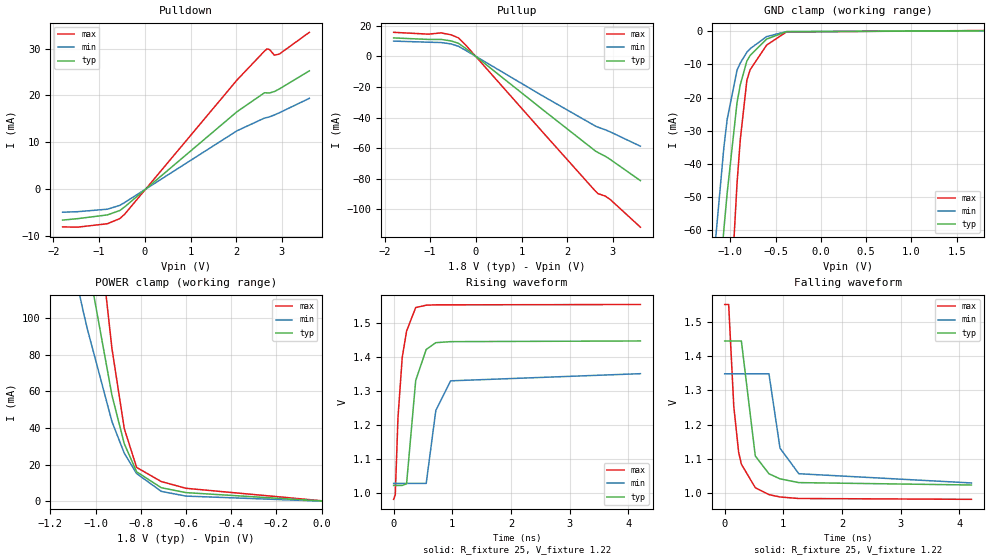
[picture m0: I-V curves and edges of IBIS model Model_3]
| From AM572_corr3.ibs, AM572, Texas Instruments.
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| Model based on original model for BMLBLVDS18_SSCEH
|   Sub model LVDS_TXMODE_5P_1P8
[model]   Model_3
|[Description]  [1.8V-3-STATE-X-8MA, IND, 5%]
|   8MA, ,IND,5%
|[Input Load]
|[Output Drive] 8MA
|Voltage   1.8V
|Mode   3-STATE
Model_type   3-state
Polarity   Non-Inverting
Enable   Active-Low
Cref =   15.0000pF
Rref =   100.0000M
Vref =   0V
Vmeas =   0.9
C_comp   3.4p   3.05p   3.82p
[Temperature Range]   25   125   -40
[Voltage Range]   1.8   1.71   1.89
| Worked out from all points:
|   slope of the pulldown table from 0 to 0.27 V, typ, clamps not added: 120 ohm
|   slope of the pullup table from 0 to 0.27 V, typ, clamps not added: 42.3 ohm
|   GND clamp passes 1 mA (typ) near -0.51 V on its own axis
|   POWER clamp passes 1 mA (typ) near -0.40 V on its own axis
|   rising waveform, R_fixture 25, V_fixture 1.22: 20-80 % time 169ps typ, 202ps min, 132ps max; typ from 1.02 V to 1.45 V
|   falling waveform, R_fixture 25, V_fixture 1.22: 20-80 % time 201ps typ, 234ps min, 166ps max; typ from 1.45 V to 1.02 V
[POWER_clamp]
-1.8V     779.9mA    580mA      1.224A
-1.236V   292.1mA    211mA      460.4mA
-1.145V   217.2mA    155.6mA    341.7mA
-1.127V   202.7mA    145mA      318.5mA
-1.055V   145.7mA    103.9mA    227.2mA
-1.036V   131.7mA    93.92mA    204.8mA
-927.3mV  57.78mA    43.44mA    83.3mA
-872.7mV  31.31mA    26.16mA    39.59mA
-818.2mV  16.05mA    15.09mA    18.44mA
-709.1mV  7.358mA    5.377mA    10.73mA
-600mV    4.702mA    2.805mA    7.054mA
0V        145uA      60.2uA     263.6uA
[Pulldown]
-1.8V     -6.635mA   -4.952mA   -8.093mA
-1.473V   -6.328mA   -4.839mA   -8.146mA
-818.2mV  -5.526mA   -4.308mA   -7.413mA
-545.5mV  -4.576mA   -3.477mA   -6.298mA
-436.4mV  -3.768mA   -2.842mA   -5.315mA
2.018V    16.54mA    12.46mA    23.32mA
2.618V    20.58mA    15.17mA    29.48mA
2.673V    20.56mA    15.28mA    29.95mA
2.727V    20.53mA    15.43mA    29.83mA
2.836V    20.85mA    15.84mA    28.61mA
2.945V    21.4mA     16.31mA    28.86mA
3.6V      25.27mA    19.39mA    33.5mA
[Pullup]
-1.8V     12.04mA    9.955mA    15.69mA
-1.036V   11.05mA    9.232mA    14.5mA
-763.6mV  11.06mA    9.014mA    15.32mA
-545.5mV  10.1mA     8.132mA    14.08mA
-381.8mV  8.512mA    6.562mA    12.05mA
-218.2mV  5.085mA    3.82mA     7.21mA
1.473V    -35.08mA   -26.06mA   -49.88mA
2.618V    -61.9mA    -45.6mA    -88.15mA
2.673V    -62.85mA   -46.29mA   -89.7mA
2.836V    -65.33mA   -48.03mA   -91.35mA
2.945V    -67.45mA   -49.42mA   -93.67mA
3.6V      -81.19mA   -58.71mA   -111.6mA
[GND_clamp]
-1.8V     -321.4mA   -309.3mA   -563.6mA
-1.291V   -133.4mA   -105mA     -247.8mA
-1.218V   -107.9mA   -79mA      -204.2mA
-1.073V   -59.81mA   -35.07mA   -120mA
-1.036V   -48.68mA   -26.51mA   -99.87mA
-927.3mV  -21.51mA   -11.72mA   -45.84mA
-890.9mV  -16.08mA   -9.549mA   -32.59mA
-818.2mV  -8.944mA   -6.334mA   -14.72mA
-781.8mV  -7.267mA   -5.252mA   -11.57mA
-600mV    -2.366mA   -1.611mA   -4.175mA
-381.8mV  -124.6uA   -115.9uA   -225uA
1.8V      145uA      89.85uA    222.6uA
[Ramp]
dV/dt_f 0.25647137/0.20081716n 0.19549562/0.23091708n 0.34546341/0.16608129n
dV/dt_r 0.25611571/0.16843214n 0.19698732/0.20168935n 0.34404226/0.13153623n
R_load =  50
[Rising Waveform]
R_fixture =  25
V_fixture =  1.22
V_fixture_min =  1.18
V_fixture_max =  1.28
0s        1.022V     1.028V     981.3mV
27.4ps    1.022V     1.028V     994.4mV
73.5ps    1.022V     1.028V     1.22V
146.2ps   1.022V     1.028V     1.398V
220.5ps   1.027V     1.028V     1.475V
375.8ps   1.33V      1.028V     1.544V
555.2ps   1.421V     1.028V     1.551V
719ps     1.441V     1.242V     1.552V
971.2ps   1.444V     1.329V     1.552V
4.207ns   1.446V     1.35V      1.553V
[Falling Waveform]
R_fixture =  25
V_fixture =  1.22
V_fixture_min =  1.18
V_fixture_max =  1.28
0s        1.445V     1.349V     1.552V
67.8ps    1.445V     1.349V     1.552V
154.8ps   1.445V     1.349V     1.254V
237.1ps   1.445V     1.349V     1.12V
284.4ps   1.445V     1.349V     1.084V
521.7ps   1.108V     1.349V     1.015V
754.5ps   1.056V     1.349V     994.8mV
943.2ps   1.041V     1.131V     987.9mV
1.264ns   1.03V      1.056V     983.4mV
4.207ns   1.023V     1.029V     981mV
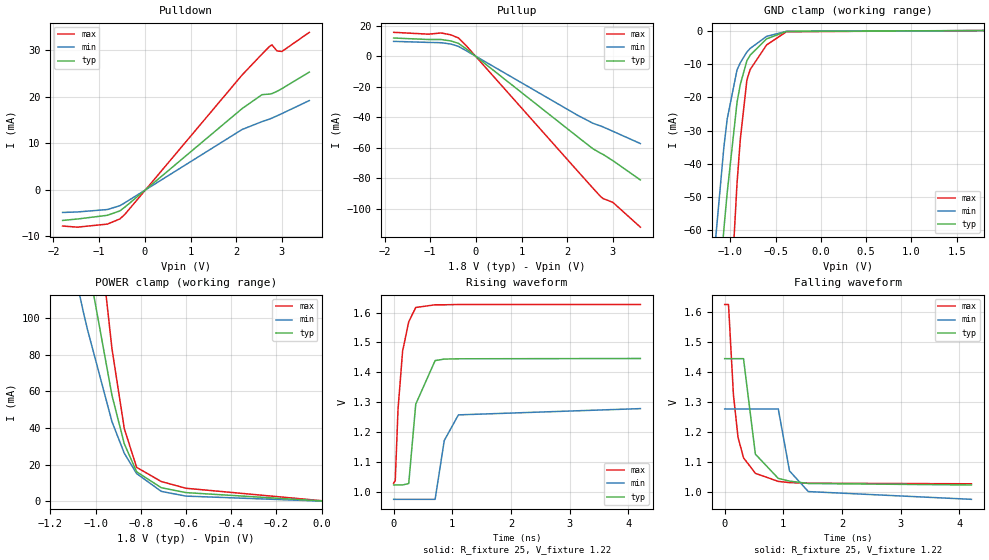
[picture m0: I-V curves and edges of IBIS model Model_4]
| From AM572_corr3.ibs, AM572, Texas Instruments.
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| Model based on original model for BMLBLVDS18_SSCEH
|   Sub model LVDS_TXMODE_10P_1P8
[model]   Model_4
|[Description]  [1.8V-3-STATE-X-8MA, IND, 10%]
|   8MA, ,IND,10%
|[Input Load]
|[Output Drive] 8MA
|Voltage   1.8V
|Mode   3-STATE
Model_type   3-state
Polarity   Non-Inverting
Enable   Active-Low
Cref =   15.0000pF
Rref =   100.0000M
Vref =   0V
Vmeas =   0.9
C_comp   3.4p   3.05p   3.82p
[Temperature Range]   25   125   -40
[Voltage Range]   1.8   1.62   1.98
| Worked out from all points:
|   slope of the pulldown table from 0 to 0.27 V, typ, clamps not added: 120 ohm
|   slope of the pullup table from 0 to 0.27 V, typ, clamps not added: 42.3 ohm
|   GND clamp passes 1 mA (typ) near -0.51 V on its own axis
|   POWER clamp passes 1 mA (typ) near -0.40 V on its own axis
|   rising waveform, R_fixture 25, V_fixture 1.22: 20-80 % time 169ps typ, 199ps min, 133ps max; typ from 1.02 V to 1.45 V
|   falling waveform, R_fixture 25, V_fixture 1.22: 20-80 % time 201ps typ, 230ps min, 167ps max; typ from 1.45 V to 1.02 V
[POWER_clamp]
-1.8V     779.9mA    580mA      1.224A
-1.236V   292.1mA    211mA      460.4mA
-1.145V   217.2mA    155.6mA    341.7mA
-1.127V   202.7mA    145mA      318.5mA
-1.055V   145.7mA    103.9mA    227.2mA
-1.036V   131.7mA    93.91mA    204.8mA
-927.3mV  57.78mA    43.43mA    83.32mA
-872.7mV  31.31mA    26.15mA    39.61mA
-818.2mV  16.05mA    15.08mA    18.46mA
-709.1mV  7.358mA    5.366mA    10.74mA
-600mV    4.702mA    2.795mA    7.071mA
0V        145uA      51.95uA    279uA
[Pulldown]
-1.8V     -6.635mA   -4.922mA   -7.841mA
-1.473V   -6.328mA   -4.812mA   -8.081mA
-818.2mV  -5.526mA   -4.29mA    -7.418mA
-545.5mV  -4.576mA   -3.464mA   -6.304mA
-436.4mV  -3.768mA   -2.831mA   -5.321mA
2.127V    17.4mA     12.91mA    24.62mA
2.564V    20.41mA    14.61mA    29.13mA
2.727V    20.53mA    15.15mA    30.76mA
2.782V    20.64mA    15.37mA    31.11mA
2.891V    21.11mA    15.85mA    29.82mA
3V        21.7mA     16.34mA    29.69mA
3.6V      25.27mA    19.14mA    33.81mA
[Pullup]
-1.8V     12.04mA    9.825mA    15.77mA
-1.036V   11.05mA    9.145mA    14.56mA
-763.6mV  11.06mA    8.945mA    15.36mA
-545.5mV  10.1mA     8.081mA    14.11mA
-381.8mV  8.512mA    6.527mA    12.07mA
-218.2mV  5.085mA    3.802mA    7.215mA
2.236V    -53.09mA   -38.87mA   -75.68mA
2.564V    -60.75mA   -44mA      -86.66mA
2.727V    -63.6mA    -45.71mA   -92.01mA
2.782V    -64.4mA    -46.35mA   -93.39mA
3V        -68.56mA   -49.24mA   -95.96mA
3.6V      -81.19mA   -57.3mA    -112.2mA
[GND_clamp]
-1.8V     -321.4mA   -309.3mA   -563.9mA
-1.291V   -133.4mA   -105mA     -247.9mA
-1.218V   -107.9mA   -79mA      -204.2mA
-1.073V   -59.81mA   -35.07mA   -120mA
-1.036V   -48.68mA   -26.51mA   -99.89mA
-927.3mV  -21.51mA   -11.71mA   -45.86mA
-890.9mV  -16.08mA   -9.545mA   -32.61mA
-818.2mV  -8.944mA   -6.331mA   -14.73mA
-781.8mV  -7.267mA   -5.249mA   -11.59mA
-600mV    -2.366mA   -1.608mA   -4.187mA
-381.8mV  -124.6uA   -112.9uA   -234.8uA
1.8V      145uA      118uA      146.8uA
[Ramp]
dV/dt_f 0.25647119/0.20081769n 0.18465813/0.2297182n 0.36196187/0.16662824n
dV/dt_r  0.2561077/0.16843651n  0.1864017/0.19810172n 0.36039242/0.13273573n
R_load =  50
[Rising Waveform]
R_fixture =  25
V_fixture =  1.22
V_fixture_min =  1.13
V_fixture_max =  1.32
0s        1.022V     973.9mV    1.028V
27.4ps    1.022V     973.9mV    1.037V
74.3ps    1.022V     973.9mV    1.275V
152.8ps   1.022V     973.9mV    1.471V
257ps     1.027V     973.9mV    1.569V
376.8ps   1.293V     973.9mV    1.617V
707ps     1.439V     973.9mV    1.626V
862.9ps   1.444V     1.171V     1.626V
1.104ns   1.445V     1.257V     1.627V
4.207ns   1.446V     1.278V     1.627V
[Falling Waveform]
R_fixture =  25
V_fixture =  1.22
V_fixture_min =  1.13
V_fixture_max =  1.32
0s        1.445V     1.277V     1.626V
64.9ps    1.445V     1.277V     1.626V
149.1ps   1.445V     1.277V     1.324V
227.5ps   1.445V     1.277V     1.182V
321ps     1.445V     1.277V     1.114V
522.9ps   1.126V     1.277V     1.062V
913.9ps   1.045V     1.277V     1.035V
1.105ns   1.036V     1.07V      1.031V
1.426ns   1.028V     1.001V     1.029V
4.207ns   1.023V     975.1mV    1.027V
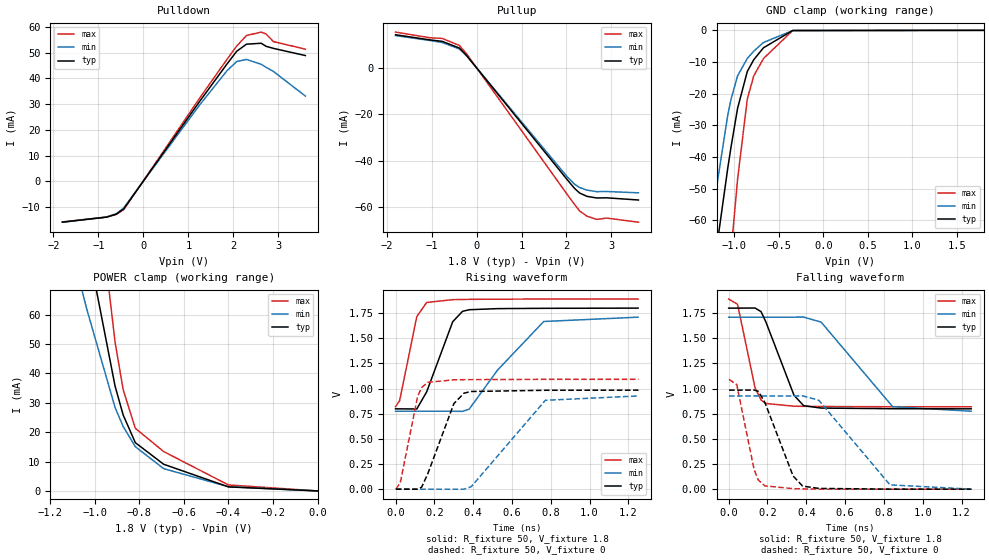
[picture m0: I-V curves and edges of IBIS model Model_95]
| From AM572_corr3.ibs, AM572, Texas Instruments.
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| Model based on original model for DDR_SEIOPB_H
|   Sub model SR011_DRV40_1P8
[model]   Model_95
|[Description]  [1.8V-I/O-X-X]
|   , ,
|[Input Load]
|[Output Drive]
|Voltage   1.8V
|Mode   I/O
Model_type   I/O
Polarity   Non-Inverting
Enable   Active-Low
Vinl =   0.775
Vinh =   1.025
Cref =   15.0000pF
Rref =   100.0000M
Vref =   0V
Vmeas =   0.9
C_comp   2p   2p   2p
[Model Spec]
Vinl   0.78   0.735   0.825
Vinh   1.02   0.975   1.065
[Receiver Thresholds]
Tslew_ac =  0.5n
Vth =  0.9
Vth_max =  0.945
Vth_min =  0.81
Vinh_ac =  0.2
Vinh_dc =  0.125
Vinl_ac =  -0.2
Vinl_dc =  -0.125
[Temperature Range]   25   125   -40
[Voltage Range]   1.8   1.71   1.89
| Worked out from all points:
|   slope of the pulldown table from 0 to 0.27 V, typ, clamps not added: 39.7 ohm
|   slope of the pullup table from 0 to 0.27 V, typ, clamps not added: 41.4 ohm
|   GND clamp passes 1 mA (typ) near -0.48 V on its own axis
|   POWER clamp passes 1 mA (typ) near -0.38 V on its own axis
|   rising waveform, R_fixture 50, V_fixture 1.8: 20-80 % time 115ps typ, 272ps min, 66.2ps max; typ from 0.799 V to 1.8 V
|   rising waveform, R_fixture 50, V_fixture 0: 20-80 % time 112ps typ, 256ps min, 65.7ps max; typ from 0 V to 0.984 V
|   falling waveform, R_fixture 50, V_fixture 1.8: 20-80 % time 119ps typ, 249ps min, 65.8ps max; typ from 1.8 V to 0.799 V
|   falling waveform, R_fixture 50, V_fixture 0: 20-80 % time 116ps typ, 246ps min, 65.9ps max; typ from 0.984 V to 0 V
[POWER_clamp]
-1.8V     464.6mA    344.4mA    740.8mA
-1.273V   197mA      143.3mA    314.4mA
-1.164V   144mA      104.2mA    229mA
-1.145V   135.3mA    97.86mA    215mA
-1.055V   93.25mA    67.59mA    146.5mA
-1.036V   85.18mA    61.89mA    133.3mA
-909.1mV  35.72mA    28.41mA    50.73mA
-872.7mV  25.87mA    21.94mA    34.5mA
-818.2mV  16.45mA    15.08mA    21.33mA
-690.9mV  9.084mA    7.592mA    13.42mA
-400mV    1.38mA     1.43mA     2.039mA
0V        227.3nA    761nA      1.176uA
[Pulldown]
-1.8V     -15.9mA    -15.92mA   -15.81mA
-818.2mV  -13.96mA   -13.89mA   -13.92mA
-600mV    -12.8mA    -12.58mA   -12.84mA
-436.4mV  -10.71mA   -10.33mA   -11.03mA
1.255V    31.16mA    29.78mA    32.45mA
1.855V    45.52mA    42.91mA    47.32mA
2.073V    50.52mA    46.55mA    52.56mA
2.291V    53.3mA     47.36mA    56.66mA
2.618V    53.66mA    45.48mA    58mA
2.727V    52.47mA    44.31mA    57.26mA
2.891V    51.66mA    42.7mA     54.29mA
3.6V      48.88mA    33.12mA    51.37mA
[Pullup]
-1.8V     14.28mA    13.9mA     15.42mA
-1.036V   12.05mA    11.79mA    12.97mA
-763.6mV  11.43mA    10.95mA    12.69mA
-381.8mV  8.556mA    8.124mA    9.674mA
-218.2mV  5.258mA    5.122mA    5.967mA
2.018V    -48.25mA   -46.99mA   -54.63mA
2.182V    -52.02mA   -50.21mA   -58.98mA
2.291V    -53.95mA   -51.57mA   -61.66mA
2.455V    -55.39mA   -52.71mA   -63.95mA
2.673V    -56.09mA   -53.37mA   -65.34mA
2.891V    -56.02mA   -53.3mA    -64.76mA
3.6V      -56.97mA   -53.87mA   -66.53mA
[GND_clamp]
-1.8V     -200.8mA   -187.9mA   -345.9mA
-1.327V   -95.75mA   -76.22mA   -171.1mA
-1.255V   -80.19mA   -60.47mA   -144.9mA
-1.218V   -72.53mA   -52.92mA   -131.9mA
-1.073V   -43.32mA   -26.59mA   -81.54mA
-1.036V   -36.61mA   -21.6mA    -69.55mA
-963.6mV  -24.61mA   -14.37mA   -47.01mA
-854.5mV  -12.98mA   -8.864mA   -21.66mA
-781.8mV  -9.263mA   -6.573mA   -14.36mA
-672.7mV  -5.498mA   -3.827mA   -8.897mA
-345.5mV  -48.81uA   -73.08uA   -79.37uA
1.8V      227.3nA    3.986uA    988nA
[Ramp]
dV/dt_f 0.60157145/0.11917839n 0.56193529/0.24940345n 0.64276181/65.810123p
dV/dt_r 0.59164809/0.11183383n 0.55731319/0.25748775n 0.65630864/65.814305p
R_load =  50
[Rising Waveform]
R_fixture =  50
V_fixture =  1.8
V_fixture_min =  1.71
V_fixture_max =  1.89
0s        798.6mV    774.9mV    820.2mV
21.02ps   798.4mV    774.9mV    879.8mV
109.5ps   797.2mV    774.8mV    1.716V
160.3ps   967.1mV    774.9mV    1.856V
294.7ps   1.665V     774.8mV    1.884V
345.2ps   1.768V     773.1mV    1.886V
379.8ps   1.784V     796.4mV    1.887V
526.2ps   1.795V     1.185V     1.889V
763.6ps   1.798V     1.667V     1.89V
1.25ns    1.8V       1.71V      1.89V
[Rising Waveform]
R_fixture =  50
V_fixture =  0
V_fixture_min =  0
V_fixture_max =  0
1.657ps   0V         0V         0V
24.5ps    0V         0V         64.86mV
113.5ps   0V         0V         919.3mV
134.2ps   18.59mV    0V         1.01V
166ps     152.6mV    0V         1.062V
300.6ps   850.8mV    0V         1.087V
353.1ps   954.7mV    0V         1.089V
389.9ps   971mV      24.27mV    1.089V
772.2ps   983.1mV    883.7mV    1.092V
1.252ns   984.5mV    926.8mV    1.092V
[Falling Waveform]
R_fixture =  50
V_fixture =  1.8
V_fixture_min =  1.71
V_fixture_max =  1.89
0s        1.8V       1.71V      1.89V
45.84ps   1.8V       1.71V      1.838V
135.9ps   1.801V     1.71V      1.008V
166.9ps   1.765V     1.71V      885.6mV
191.7ps   1.663V     1.71V      852mV
336.7ps   933.7mV    1.71V      824.7mV
386.2ps   830.3mV    1.711V     823.2mV
476.4ps   806.1mV    1.661V     821.5mV
845.1ps   799.9mV    820.1mV    819.5mV
1.25ns    798.6mV    774.9mV    819.3mV
[Falling Waveform]
R_fixture =  50
V_fixture =  0
V_fixture_min =  0
V_fixture_max =  0
1.657ps   984.5mV    926.8mV    1.092V
41.72ps   984.7mV    926.8mV    1.039V
131.3ps   985.5mV    926.9mV    192.5mV
153.1ps   972.6mV    926.9mV    89.75mV
186.6ps   862mV      926.8mV    33.17mV
331.9ps   131.2mV    926.6mV    4.76mV
381.1ps   30.54mV    927.3mV    3.153mV
464.5ps   7.614mV    883.9mV    0V
831.3ps   0V         42.71mV    0V
1.252ns   0V         0V         0V
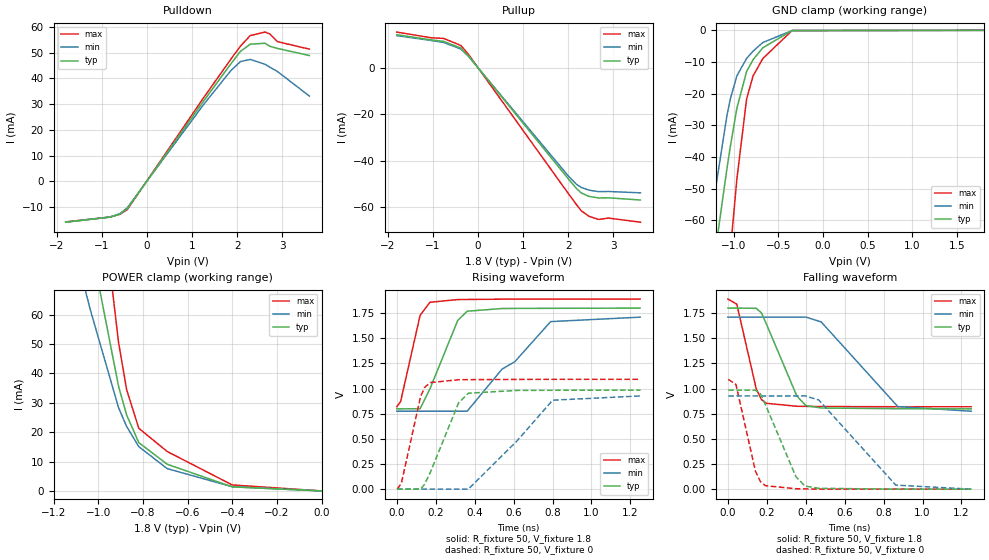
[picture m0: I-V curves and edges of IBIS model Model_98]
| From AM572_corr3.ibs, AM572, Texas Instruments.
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| Model based on original model for DDR_SEIOPB_H
|   Sub model SR100_DRV40_1P8
[model]   Model_98
|[Description]  [1.8V-I/O-X-X]
|   , ,
|[Input Load]
|[Output Drive]
|Voltage   1.8V
|Mode   I/O
Model_type   I/O
Polarity   Non-Inverting
Enable   Active-Low
Vinl =   0.775
Vinh =   1.025
Cref =   15.0000pF
Rref =   100.0000M
Vref =   0V
Vmeas =   0.9
C_comp   2p   2p   2p
[Model Spec]
Vinl   0.78   0.735   0.825
Vinh   1.02   0.975   1.065
[Receiver Thresholds]
Tslew_ac =  0.5n
Vth =  0.9
Vth_max =  0.945
Vth_min =  0.81
Vinh_ac =  0.2
Vinh_dc =  0.125
Vinl_ac =  -0.2
Vinl_dc =  -0.125
[Temperature Range]   25   125   -40
[Voltage Range]   1.8   1.71   1.89
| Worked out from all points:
|   slope of the pulldown table from 0 to 0.27 V, typ, clamps not added: 39.7 ohm
|   slope of the pullup table from 0 to 0.27 V, typ, clamps not added: 41.4 ohm
|   GND clamp passes 1 mA (typ) near -0.48 V on its own axis
|   POWER clamp passes 1 mA (typ) near -0.38 V on its own axis
|   rising waveform, R_fixture 50, V_fixture 1.8: 20-80 % time 128ps typ, 297ps min, 73.7ps max; typ from 0.799 V to 1.8 V
|   rising waveform, R_fixture 50, V_fixture 0: 20-80 % time 123ps typ, 281ps min, 73.1ps max; typ from 0 V to 0.984 V
|   falling waveform, R_fixture 50, V_fixture 1.8: 20-80 % time 132ps typ, 272ps min, 72.6ps max; typ from 1.8 V to 0.799 V
|   falling waveform, R_fixture 50, V_fixture 0: 20-80 % time 129ps typ, 269ps min, 73ps max; typ from 0.984 V to 0 V
[POWER_clamp]
-1.8V     464.6mA    344.4mA    740.8mA
-1.273V   197mA      143.3mA    314.4mA
-1.164V   144mA      104.2mA    229mA
-1.145V   135.3mA    97.86mA    215mA
-1.055V   93.25mA    67.59mA    146.5mA
-1.036V   85.18mA    61.89mA    133.3mA
-909.1mV  35.72mA    28.41mA    50.73mA
-872.7mV  25.87mA    21.94mA    34.5mA
-818.2mV  16.45mA    15.08mA    21.33mA
-690.9mV  9.084mA    7.592mA    13.42mA
-400mV    1.38mA     1.43mA     2.039mA
0V        227.3nA    761nA      1.176uA
[Pulldown]
-1.8V     -15.9mA    -15.92mA   -15.81mA
-818.2mV  -13.96mA   -13.89mA   -13.92mA
-600mV    -12.8mA    -12.58mA   -12.84mA
-436.4mV  -10.71mA   -10.33mA   -11.03mA
1.255V    31.16mA    29.78mA    32.45mA
1.855V    45.52mA    42.91mA    47.32mA
2.073V    50.52mA    46.55mA    52.56mA
2.291V    53.3mA     47.36mA    56.66mA
2.618V    53.66mA    45.48mA    58mA
2.727V    52.47mA    44.31mA    57.26mA
2.891V    51.66mA    42.7mA     54.29mA
3.6V      48.88mA    33.12mA    51.37mA
[Pullup]
-1.8V     14.28mA    13.9mA     15.42mA
-1.036V   12.05mA    11.79mA    12.97mA
-763.6mV  11.43mA    10.95mA    12.69mA
-381.8mV  8.556mA    8.124mA    9.674mA
-218.2mV  5.258mA    5.122mA    5.967mA
2.018V    -48.25mA   -46.99mA   -54.63mA
2.182V    -52.02mA   -50.21mA   -58.98mA
2.291V    -53.95mA   -51.57mA   -61.66mA
2.455V    -55.39mA   -52.71mA   -63.95mA
2.673V    -56.09mA   -53.37mA   -65.34mA
2.891V    -56.02mA   -53.3mA    -64.76mA
3.6V      -56.97mA   -53.87mA   -66.53mA
[GND_clamp]
-1.8V     -200.8mA   -187.9mA   -345.9mA
-1.327V   -95.75mA   -76.22mA   -171.1mA
-1.255V   -80.19mA   -60.47mA   -144.9mA
-1.218V   -72.53mA   -52.92mA   -131.9mA
-1.073V   -43.32mA   -26.59mA   -81.54mA
-1.036V   -36.61mA   -21.6mA    -69.55mA
-963.6mV  -24.61mA   -14.37mA   -47.01mA
-854.5mV  -12.98mA   -8.864mA   -21.66mA
-781.8mV  -9.263mA   -6.573mA   -14.36mA
-672.7mV  -5.498mA   -3.827mA   -8.897mA
-345.5mV  -48.81uA   -73.08uA   -79.37uA
1.8V      227.3nA    3.986uA    988nA
[Ramp]
dV/dt_f 0.60158367/0.13233123n 0.56198752/0.27252795n 0.64280804/72.653265p
dV/dt_r 0.59171008/0.12349822n 0.55737238/0.28198184n 0.65629545/73.206884p
R_load =  50
[Rising Waveform]
R_fixture =  50
V_fixture =  1.8
V_fixture_min =  1.71
V_fixture_max =  1.89
0s        798.6mV    774.9mV    820.2mV
19.64ps   798.5mV    774.9mV    871.6mV
119.7ps   799.7mV    774.8mV    1.728V
170.5ps   998.5mV    774.9mV    1.858V
312.7ps   1.676V     774.7mV    1.885V
361.5ps   1.769V     774.9mV    1.886V
540.6ps   1.796V     1.193V     1.889V
606.6ps   1.797V     1.268V     1.889V
790.5ps   1.798V     1.666V     1.89V
1.25ns    1.8V       1.71V      1.89V
[Rising Waveform]
R_fixture =  50
V_fixture =  0
V_fixture_min =  0
V_fixture_max =  0
1.773ps   0V         0V         0V
23.19ps   0V         0V         56.98mV
122.7ps   0V         0V         924.9mV
143.5ps   50.92mV    0V         1.013V
172.5ps   168.4mV    0V         1.06V
317.3ps   857mV      0V         1.088V
367.5ps   954.2mV    0V         1.089V
615.8ps   981.7mV    476.1mV    1.091V
800.7ps   983.2mV    884.6mV    1.092V
1.252ns   984.5mV    926.8mV    1.092V
[Falling Waveform]
R_fixture =  50
V_fixture =  1.8
V_fixture_min =  1.71
V_fixture_max =  1.89
0s        1.8V       1.71V      1.89V
45.59ps   1.8V       1.71V      1.839V
145.7ps   1.798V     1.71V      996mV
172.2ps   1.753V     1.71V      891.2mV
197.2ps   1.644V     1.71V      853.9mV
354.1ps   926.4mV    1.71V      824.2mV
400.5ps   831.2mV    1.711V     823mV
479.1ps   806.8mV    1.663V     821.5mV
873.1ps   799.8mV    820.9mV    819.5mV
1.25ns    798.6mV    774.9mV    819.3mV
[Falling Waveform]
R_fixture =  50
V_fixture =  0
V_fixture_min =  0
V_fixture_max =  0
1.773ps   984.5mV    926.8mV    1.092V
41.28ps   984.7mV    926.8mV    1.041V
141.3ps   984.1mV    926.9mV    179.9mV
167.6ps   945.1mV    926.8mV    72.73mV
192.9ps   839.6mV    926.8mV    34.57mV
349.1ps   125mV      926.6mV    4.314mV
395.4ps   31.48mV    927.6mV    2.924mV
466.5ps   8.587mV    887.2mV    0V
862.5ps   0V         40.19mV    0V
1.252ns   0V         0V         0V
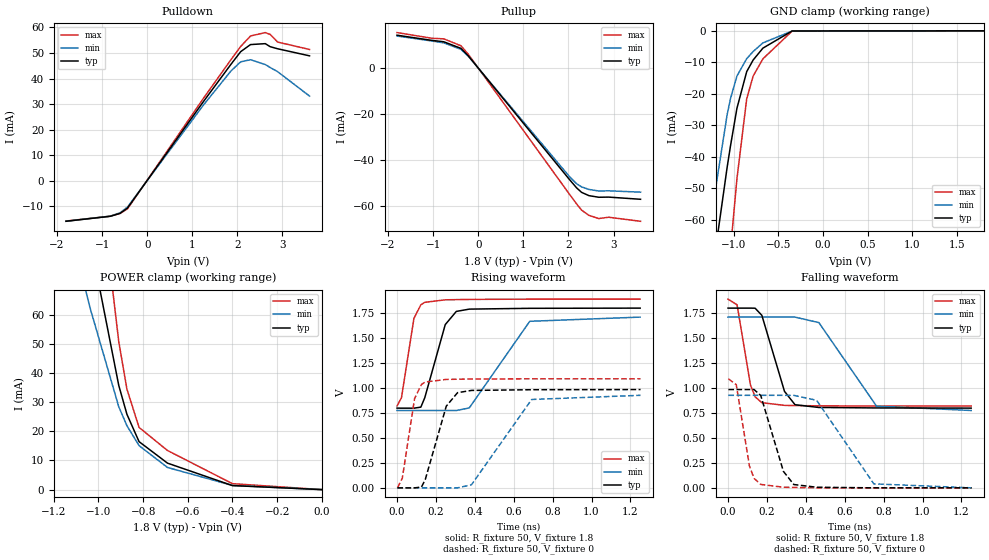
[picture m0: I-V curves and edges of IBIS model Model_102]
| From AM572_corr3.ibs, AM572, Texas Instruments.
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| Model based on original model for DDR_SEIOPB_H
|   Sub model SR000_DRV40_1P8
[model]   Model_102
|[Description]  [1.8V-I/O-X-X]
|   , ,
|[Input Load]
|[Output Drive]
|Voltage   1.8V
|Mode   I/O
Model_type   I/O
Polarity   Non-Inverting
Enable   Active-Low
Vinl =   0.775
Vinh =   1.025
Cref =   15.0000pF
Rref =   100.0000M
Vref =   0V
Vmeas =   0.9
C_comp   2p   2p   2p
[Model Spec]
Vinl   0.78   0.735   0.825
Vinh   1.02   0.975   1.065
[Receiver Thresholds]
Tslew_ac =  0.5n
Vth =  0.9
Vth_max =  0.945
Vth_min =  0.81
Vinh_ac =  0.2
Vinh_dc =  0.125
Vinl_ac =  -0.2
Vinl_dc =  -0.125
[Temperature Range]   25   125   -40
[Voltage Range]   1.8   1.71   1.89
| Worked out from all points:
|   slope of the pulldown table from 0 to 0.27 V, typ, clamps not added: 39.7 ohm
|   slope of the pullup table from 0 to 0.27 V, typ, clamps not added: 41.4 ohm
|   GND clamp passes 1 mA (typ) near -0.48 V on its own axis
|   POWER clamp passes 1 mA (typ) near -0.38 V on its own axis
|   rising waveform, R_fixture 50, V_fixture 1.8: 20-80 % time 83.9ps typ, 201ps min, 49.9ps max; typ from 0.799 V to 1.8 V
|   rising waveform, R_fixture 50, V_fixture 0: 20-80 % time 82.9ps typ, 191ps min, 49.8ps max; typ from 0 V to 0.984 V
|   falling waveform, R_fixture 50, V_fixture 1.8: 20-80 % time 87.8ps typ, 186ps min, 51.9ps max; typ from 1.8 V to 0.799 V
|   falling waveform, R_fixture 50, V_fixture 0: 20-80 % time 85.8ps typ, 182ps min, 51.3ps max; typ from 0.984 V to 0 V
[POWER_clamp]
-1.8V     464.6mA    344.4mA    740.8mA
-1.273V   197mA      143.3mA    314.4mA
-1.164V   144mA      104.2mA    229mA
-1.145V   135.3mA    97.86mA    215mA
-1.055V   93.25mA    67.59mA    146.5mA
-1.036V   85.18mA    61.89mA    133.3mA
-909.1mV  35.72mA    28.41mA    50.73mA
-872.7mV  25.87mA    21.94mA    34.5mA
-818.2mV  16.45mA    15.08mA    21.33mA
-690.9mV  9.084mA    7.592mA    13.42mA
-400mV    1.38mA     1.43mA     2.039mA
0V        227.3nA    761nA      1.176uA
[Pulldown]
-1.8V     -15.9mA    -15.92mA   -15.81mA
-818.2mV  -13.96mA   -13.89mA   -13.92mA
-600mV    -12.8mA    -12.58mA   -12.84mA
-436.4mV  -10.71mA   -10.33mA   -11.03mA
1.255V    31.16mA    29.78mA    32.45mA
1.855V    45.52mA    42.91mA    47.32mA
2.073V    50.52mA    46.55mA    52.56mA
2.291V    53.3mA     47.36mA    56.66mA
2.618V    53.66mA    45.48mA    58mA
2.727V    52.47mA    44.31mA    57.26mA
2.891V    51.66mA    42.7mA     54.29mA
3.6V      48.88mA    33.12mA    51.37mA
[Pullup]
-1.8V     14.28mA    13.9mA     15.42mA
-1.036V   12.05mA    11.79mA    12.97mA
-763.6mV  11.43mA    10.95mA    12.69mA
-381.8mV  8.556mA    8.124mA    9.674mA
-218.2mV  5.258mA    5.122mA    5.967mA
2.018V    -48.25mA   -46.99mA   -54.63mA
2.182V    -52.02mA   -50.21mA   -58.98mA
2.291V    -53.95mA   -51.57mA   -61.66mA
2.455V    -55.39mA   -52.71mA   -63.95mA
2.673V    -56.09mA   -53.37mA   -65.34mA
2.891V    -56.02mA   -53.3mA    -64.76mA
3.6V      -56.97mA   -53.87mA   -66.53mA
[GND_clamp]
-1.8V     -200.8mA   -187.9mA   -345.9mA
-1.327V   -95.75mA   -76.22mA   -171.1mA
-1.255V   -80.19mA   -60.47mA   -144.9mA
-1.218V   -72.53mA   -52.92mA   -131.9mA
-1.073V   -43.32mA   -26.59mA   -81.54mA
-1.036V   -36.61mA   -21.6mA    -69.55mA
-963.6mV  -24.61mA   -14.37mA   -47.01mA
-854.5mV  -12.98mA   -8.864mA   -21.66mA
-781.8mV  -9.263mA   -6.573mA   -14.36mA
-672.7mV  -5.498mA   -3.827mA   -8.897mA
-345.5mV  -48.81uA   -73.08uA   -79.37uA
1.8V      227.3nA    3.986uA    988nA
[Ramp]
dV/dt_f 0.60152695/87.856657p 0.56188703/0.18590935n 0.64274256/51.891391p
dV/dt_r 0.59179499/83.073453p 0.55709331/0.19106712n 0.65655366/49.898971p
R_load =  50
[Rising Waveform]
R_fixture =  50
V_fixture =  1.8
V_fixture_min =  1.71
V_fixture_max =  1.89
0s        798.6mV    774.9mV    820.1mV
22.93ps   798.1mV    774.8mV    902.7mV
86.93ps   797.8mV    774.8mV    1.697V
122.5ps   808.4mV    774.8mV    1.833V
142.8ps   902.9mV    774.8mV    1.858V
248ps     1.635V     774.6mV    1.883V
304.9ps   1.767V     774.1mV    1.885V
371.5ps   1.79V      800.7mV    1.887V
682.4ps   1.798V     1.668V     1.89V
1.25ns    1.8V       1.71V      1.89V
[Rising Waveform]
R_fixture =  50
V_fixture =  0
V_fixture_min =  0
V_fixture_max =  0
1.951ps   0V         0V         0V
27.09ps   0V         0V         94.7mV
90.25ps   0V         0V         894.2mV
125.6ps   7.783mV    0V         1.035V
145.2ps   82.49mV    0V         1.06V
253.2ps   817.8mV    0V         1.086V
311.1ps   953.1mV    0V         1.088V
382.6ps   975.8mV    30.5mV     1.09V
692.2ps   982.8mV    885.1mV    1.092V
1.252ns   984.5mV    926.8mV    1.092V
[Falling Waveform]
R_fixture =  50
V_fixture =  1.8
V_fixture_min =  1.71
V_fixture_max =  1.89
0s        1.8V       1.71V      1.89V
46.56ps   1.8V       1.71V      1.833V
115.5ps   1.8V       1.71V      1.029V
139.3ps   1.799V     1.71V      911.9mV
173.9ps   1.728V     1.71V      852.8mV
290.4ps   966.1mV    1.71V      826.1mV
344.5ps   832.6mV    1.71V      824mV
467ps     805mV      1.655V     821.4mV
763.5ps   800.3mV    818.1mV    819.6mV
1.25ns    798.6mV    774.9mV    819.3mV
[Falling Waveform]
R_fixture =  50
V_fixture =  0
V_fixture_min =  0
V_fixture_max =  0
1.951ps   984.5mV    926.8mV    1.092V
42.52ps   984.7mV    926.9mV    1.033V
110ps     984.3mV    926.9mV    219.7mV
133.8ps   984.9mV    926.9mV    95.32mV
168.3ps   924.8mV    926.8mV    34.21mV
284.8ps   165.1mV    926.8mV    6.377mV
338.4ps   33.29mV    926.5mV    4.066mV
455.5ps   6.319mV    876.8mV    0V
749.5ps   0V         40.08mV    0V
1.252ns   0V         0V         0V
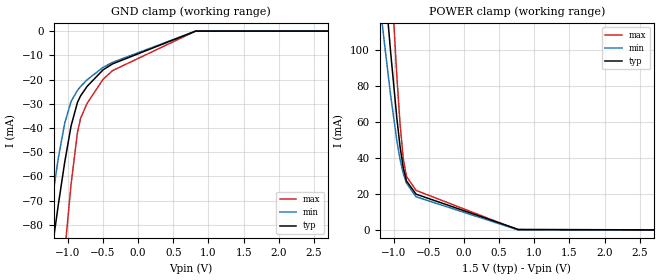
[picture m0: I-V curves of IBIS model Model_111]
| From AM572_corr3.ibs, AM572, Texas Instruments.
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| Model based on original model for DDR_SEIOPB_H
|   Sub model DDR3_ODT_80_1P5
[model]   Model_111
|[Description]  [1.5V-INPUT-X-X]
|   , ,
|[Input Load]
|[Output Drive]
|Voltage   1.5V
|Mode   INPUT
Model_type   Input
Polarity   Non-Inverting
Vinl =  0.65
Vinh =  0.85
C_comp   1p   0.5p   1.75p
[Receiver Thresholds]
Tslew_ac =  0.5n
Vth =  0.75
Vth_max =  0.7875
Vth_min =  0.675
Vinh_ac =  0.175
Vinh_dc =  0.1
Vinl_ac =  -0.175
Vinl_dc =  -0.1
[Temperature Range]   25   125   -40
[Voltage Range]   1.5   1.425   1.575
[POWER_clamp]
-1.5V     321.5mA    239.1mA    504.1mA
-1.273V   207.5mA    154mA      322.2mA
-1.182V   163.2mA    121.3mA    251mA
-1.136V   141.5mA    105.5mA    215.9mA
-1.045V   99.69mA    75.49mA    147.8mA
-954.5mV  61.97mA    49.55mA    85.22mA
-909.1mV  46.34mA    39.28mA    58.86mA
-863.6mV  34.59mA    31.51mA    39.68mA
-818.2mV  27.29mA    26.07mA    29.85mA
-681.8mV  19.94mA    18.49mA    22.04mA
772.7mV   298.5uA    0A         0A
3V        0A         0A         0A
[GND_clamp]
-1.5V     -149.8mA   -131mA     -254mA
-1.273V   -100.1mA   -79.6mA    -170.8mA
-1.136V   -71.71mA   -52.39mA   -122.3mA
-1.045V   -54.15mA   -38.06mA   -91.43mA
-954.5mV  -39.16mA   -29.03mA   -63.18mA
-863.6mV  -29.44mA   -24.45mA   -41.86mA
-818.2mV  -26.69mA   -22.85mA   -35.96mA
-727.3mV  -22.86mA   -20.13mA   -29.89mA
-500mV    -16.02mA   -14.99mA   -19.91mA
-363.6mV  -13.53mA   -12.9mA    -16.31mA
818.2mV   0A         0A         0A
3V        0A         0A         0A
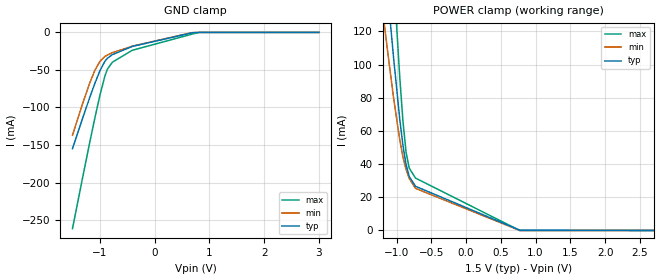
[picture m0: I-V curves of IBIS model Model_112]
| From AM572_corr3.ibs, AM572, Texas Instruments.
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| Model based on original model for DDR_SEIOPB_H
|   Sub model DDR3_ODT_60_1P5
[model]   Model_112
|[Description]  [1.5V-INPUT-X-X]
|   , ,
|[Input Load]
|[Output Drive]
|Voltage   1.5V
|Mode   INPUT
Model_type   Input
Polarity   Non-Inverting
Vinl =  0.65
Vinh =  0.85
C_comp   1p   0.5p   1.75p
[Receiver Thresholds]
Tslew_ac =  0.5n
Vth =  0.75
Vth_max =  0.7875
Vth_min =  0.675
Vinh_ac =  0.175
Vinh_dc =  0.1
Vinl_ac =  -0.175
Vinl_dc =  -0.1
[Temperature Range]   25   125   -40
[Voltage Range]   1.5   1.425   1.575
[POWER_clamp]
-1.5V     326.8mA    243.6mA    511.7mA
-1.273V   212.8mA    158.9mA    329.7mA
-1.182V   168.5mA    126.3mA    258.4mA
-1.136V   146.8mA    110.5mA    223.4mA
-1.045V   105mA      80.6mA     155.2mA
-954.5mV  67.22mA    54.75mA    92.67mA
-909.1mV  51.6mA     44.53mA    66.37mA
-863.6mV  39.88mA    36.8mA     47.32mA
-818.2mV  32.6mA     31.4mA     37.6mA
-727.3mV  26.63mA    25.37mA    31.57mA
772.7mV   163.5uA    0A         0A
3V        0A         0A         0A
[GND_clamp]
-1.5V     -155mA     -137.1mA   -261.5mA
-1.318V   -115.1mA   -95.5mA    -194.6mA
-1.182V   -86.12mA   -66.87mA   -145.6mA
-1.091V   -67.85mA   -50.57mA   -114mA
-1V       -51.29mA   -38.67mA   -84.1mA
-909.1mV  -38.58mA   -32.19mA   -58.44mA
-863.6mV  -34.54mA   -30.21mA   -49.17mA
-772.7mV  -29.68mA   -27.09mA   -39.76mA
-409.1mV  -18.72mA   -18.39mA   -23.84mA
681.8mV   -586.4uA   -300uA     -2.343mA
818.2mV   0A         0A         0A
3V        0A         0A         0A
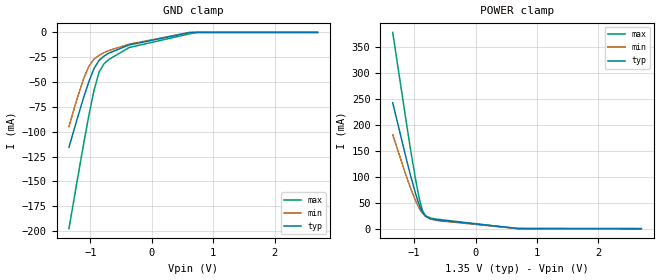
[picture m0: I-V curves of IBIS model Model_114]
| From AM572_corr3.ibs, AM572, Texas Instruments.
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| Model based on original model for DDR_SEIOPB_H
|   Sub model DDR3L_ODT_80_1P35
[model]   Model_114
|[Description]  [1.35V-INPUT-X-X]
|   , ,
|[Input Load]
|[Output Drive]
|Voltage   1.35V
|Mode   INPUT
Model_type   Input
Polarity   Non-Inverting
Vinl =  0.585
Vinh =  0.765
C_comp   1p   0.5p   1.75p
[Receiver Thresholds]
Tslew_ac =  5n
Vth =  0.675
Vth_max =  0.709
Vth_min =  0.608
Vinh_ac =  0.175
Vinh_dc =  0.1
Vinl_ac =  -0.175
Vinl_dc =  -0.1
[Temperature Range]   25   125   -40
[Voltage Range]   1.35   1.2825   1.4175
[POWER_clamp]
-1.35V    242.9mA    181.2mA    378.4mA
-1.145V   142.6mA    107mA      217.7mA
-1.064V   104.6mA    79.6mA     156mA
-981.8mV  69.39mA    54.98mA    98.09mA
-940.9mV  53.78mA    44.47mA    71.92mA
-900mV    40.49mA    35.74mA    49.52mA
-859.1mV  30.56mA    29.07mA    33.54mA
-818.2mV  24.29mA    24.28mA    25.28mA
-736.4mV  19.06mA    18.69mA    20.43mA
-613.6mV  16.66mA    15.53mA    18.01mA
695.5mV   302.9uA    0A         33.14uA
2.7V      0A         0A         0A
[GND_clamp]
-1.35V    -115.6mA   -94.89mA   -197.5mA
-1.227V   -89.36mA   -68.54mA   -153.1mA
-1.105V   -64.31mA   -45.5mA    -110mA
-1.023V   -49.02mA   -33.92mA   -82.75mA
-940.9mV  -36.24mA   -26.85mA   -58.09mA
-859.1mV  -28.07mA   -23.04mA   -39.84mA
-777.3mV  -23.77mA   -20.37mA   -31.48mA
-695.5mV  -20.72mA   -18.12mA   -27.05mA
-368.2mV  -12.61mA   -11.9mA    -15.17mA
613.6mV   -211.8uA   -17.74uA   -1.47mA
736.4mV   0A         0A         0A
2.7V      0A         0A         0A
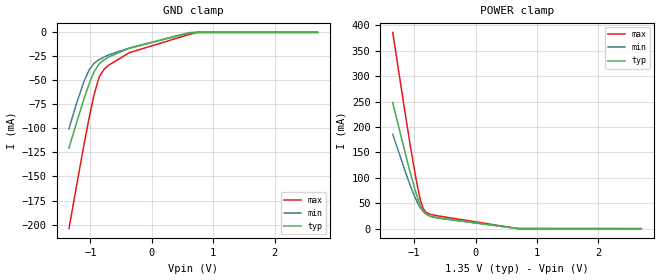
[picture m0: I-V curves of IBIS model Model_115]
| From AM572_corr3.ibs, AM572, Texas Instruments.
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| Model based on original model for DDR_SEIOPB_H
|   Sub model DDR3L_ODT_60_1P35
[model]   Model_115
|[Description]  [1.35V-INPUT-X-X]
|   , ,
|[Input Load]
|[Output Drive]
|Voltage   1.35V
|Mode   INPUT
Model_type   Input
Polarity   Non-Inverting
Vinl =  0.585
Vinh =  0.765
C_comp   1p   0.5p   1.75p
[Receiver Thresholds]
Tslew_ac =  5n
Vth =  0.675
Vth_max =  0.709
Vth_min =  0.608
Vinh_ac =  0.175
Vinh_dc =  0.1
Vinl_ac =  -0.175
Vinl_dc =  -0.1
[Temperature Range]   25   125   -40
[Voltage Range]   1.35   1.2825   1.4175
[POWER_clamp]
-1.35V    248.3mA    186mA      386.1mA
-1.145V   147.9mA    112.1mA    225.3mA
-1.064V   109.9mA    84.74mA    163.7mA
-981.8mV  74.73mA    60.2mA     105.7mA
-940.9mV  59.11mA    49.74mA    79.54mA
-900mV    45.83mA    41.05mA    57.19mA
-859.1mV  35.91mA    34.42mA    41.31mA
-818.2mV  29.64mA    29.66mA    33.12mA
-736.4mV  24.31mA    24.06mA    28.13mA
-613.6mV  21.57mA    20.69mA    25.17mA
695.5mV   192.5uA    0A         46.51uA
2.7V      0A         0A         0A
[GND_clamp]
-1.35V    -120.4mA   -100.3mA   -204.3mA
-1.227V   -94.15mA   -73.96mA   -159.9mA
-1.105V   -69.07mA   -50.89mA   -116.8mA
-1.023V   -53.77mA   -39.29mA   -89.53mA
-940.9mV  -40.99mA   -32.2mA    -64.86mA
-859.1mV  -32.82mA   -28.33mA   -46.64mA
-777.3mV  -28.49mA   -25.59mA   -38.29mA
-695.5mV  -25.39mA   -23.24mA   -33.8mA
-368.2mV  -16.65mA   -16.22mA   -21.15mA
613.6mV   -480.4uA   -182uA     -2.055mA
736.4mV   0A         0A         0A
2.7V      0A         0A         0A
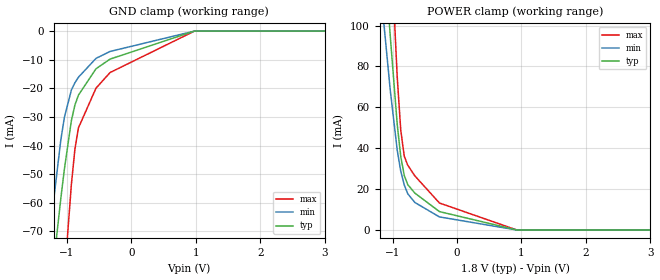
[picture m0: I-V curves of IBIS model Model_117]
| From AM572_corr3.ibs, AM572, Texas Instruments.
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| Model based on original model for DDR_SEIOPB_H
|   Sub model DDR2_ODT_120_1P8
[model]   Model_117
|[Description]  [1.8V-INPUT-X-X]
|   , ,
|[Input Load]
|[Output Drive]
|Voltage   1.8V
|Mode   INPUT
Model_type   Input
Polarity   Non-Inverting
Vinl =   0.775
Vinh =   1.025
C_comp   1p   0.5p   1.75p
[Receiver Thresholds]
Tslew_ac =  0.5n
Vth =  0.9
Vth_max =  0.945
Vth_min =  0.81
Vinh_ac =  0.2
Vinh_dc =  0.125
Vinl_ac =  -0.2
Vinl_dc =  -0.125
[Temperature Range]   25   125   -40
[Voltage Range]   1.8   1.71   1.89
[POWER_clamp]
-1.8V     474.5mA    350.2mA    754.4mA
-1.255V   198.1mA    143.2mA    313.9mA
-1.145V   145.3mA    104.5mA    228.9mA
-1.036V   95.16mA    68.6mA     147.2mA
-927.3mV  51.66mA    39.06mA    74.83mA
-872.7mV  35.98mA    28.8mA     48.91mA
-818.2mV  26.63mA    21.98mA    36.05mA
-763.6mV  22.16mA    17.7mA     31.65mA
-654.5mV  18.06mA    13.46mA    26.48mA
-272.7mV  8.986mA    6.385mA    13.19mA
927.3mV   0A         0A         0A
3.6V      0A         0A         0A
[GND_clamp]
-1.8V     -212.7mA   -196.7mA   -362.9mA
-1.364V   -115.4mA   -92.95mA   -201.1mA
-1.255V   -91.86mA   -69.05mA   -161.6mA
-1.091V   -58.37mA   -37.94mA   -104.2mA
-1.036V   -48.16mA   -30.14mA   -86.07mA
-927.3mV  -31.24mA   -20.56mA   -53.45mA
-872.7mV  -25.81mA   -18.04mA   -41.24mA
-818.2mV  -22.39mA   -16.12mA   -33.81mA
-545.5mV  -13.16mA   -9.523mA   -19.93mA
-327.3mV  -9.78mA    -7.117mA   -14.48mA
981.8mV   0A         0A         0A
3.6V      0A         0A         0A
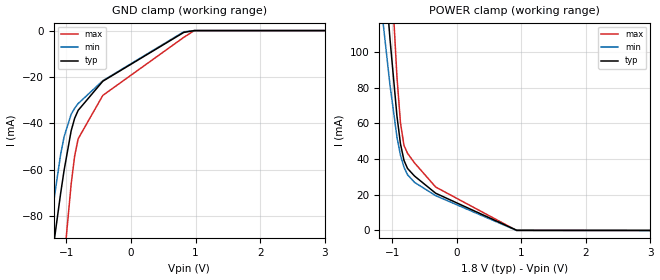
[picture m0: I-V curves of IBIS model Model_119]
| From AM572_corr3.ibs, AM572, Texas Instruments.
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| Model based on original model for DDR_SEIOPB_H
|   Sub model DDR2_ODT_60_1P8
[model]   Model_119
|[Description]  [1.8V-INPUT-X-X]
|   , ,
|[Input Load]
|[Output Drive]
|Voltage   1.8V
|Mode   INPUT
Model_type   Input
Polarity   Non-Inverting
Vinl =   0.775
Vinh =   1.025
C_comp   1p   0.5p   1.75p
[Receiver Thresholds]
Tslew_ac =  0.5n
Vth =  0.9
Vth_max =  0.945
Vth_min =  0.81
Vinh_ac =  0.2
Vinh_dc =  0.125
Vinl_ac =  -0.2
Vinl_dc =  -0.125
[Temperature Range]   25   125   -40
[Voltage Range]   1.8   1.71   1.89
[POWER_clamp]
-1.8V     487.3mA    361.5mA    766.2mA
-1.255V   210.7mA    155.8mA    325.3mA
-1.145V   157.9mA    117.3mA    240.2mA
-1.036V   107.6mA    81.63mA    158.4mA
-927.3mV  64.13mA    52.3mA     86.06mA
-872.7mV  48.51mA    42.14mA    60.31mA
-818.2mV  39.22mA    35.41mA    47.62mA
-763.6mV  34.73mA    31.19mA    43.2mA
-654.5mV  30.45mA    26.93mA    37.81mA
-327.3mV  20.84mA    19.47mA    24.31mA
927.3mV   112.6uA    0A         0A
3.6V      0A         0A         0A
[GND_clamp]
-1.8V     -225.3mA   -213.2mA   -377.3mA
-1.364V   -127.7mA   -109mA     -214.7mA
-1.255V   -104.1mA   -84.92mA   -175mA
-1.091V   -70.51mA   -53.64mA   -117.4mA
-1.036V   -60.27mA   -45.81mA   -99.14mA
-927.3mV  -43.31mA   -36.14mA   -66.38mA
-872.7mV  -37.87mA   -33.53mA   -54.14mA
-818.2mV  -34.42mA   -31.49mA   -46.7mA
-436.4mV  -21.86mA   -21.64mA   -27.98mA
818.2mV   -789.7uA   -517.4uA   -2.91mA
981.8mV   0A         0A         0A
3.6V      0A         0A         0A
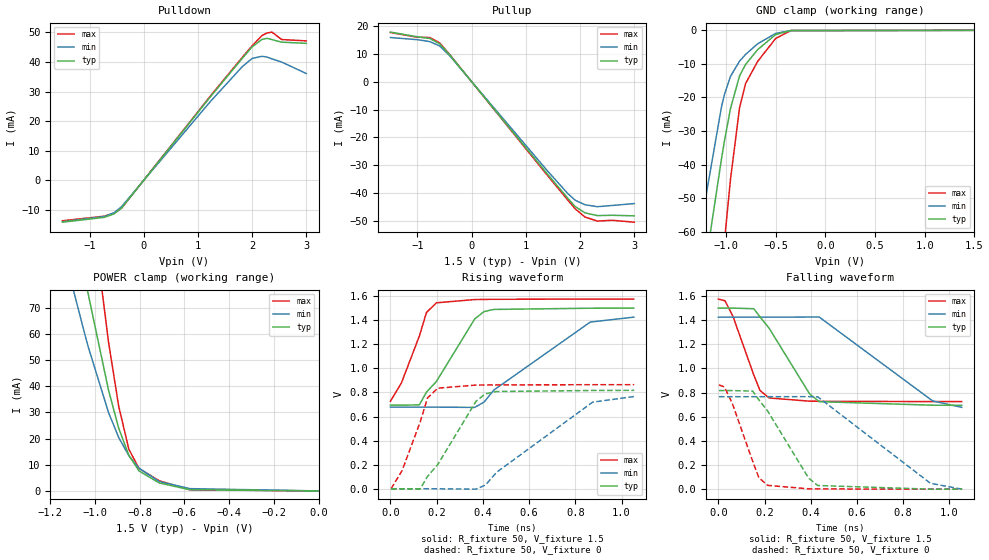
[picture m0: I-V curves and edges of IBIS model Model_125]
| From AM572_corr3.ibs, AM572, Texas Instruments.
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| Model based on original model for DDR_SEIOPB_H
|   Sub model SR111_DRV40_1P5
[model]   Model_125
|[Description]  [1.5V-I/O-X-X]
|   , ,
|[Input Load]
|[Output Drive]
|Voltage   1.5V
|Mode   I/O
Model_type   I/O
Polarity   Non-Inverting
Enable   Active-Low
Vinl =   0.65
Vinh =   0.85
Cref =   15.0000pF
Rref =   100.0000M
Vref =   0V
Vmeas =   0.75
C_comp   2p   2p   2p
[Model Spec]
Vinl   0.65   0.6125   0.6875
Vinh   0.85   0.8125   0.8875
[Receiver Thresholds]
Tslew_ac =  0.5n
Vth =  0.75
Vth_max =  0.7875
Vth_min =  0.675
Vinh_ac =  0.175
Vinh_dc =  0.1
Vinl_ac =  -0.175
Vinl_dc =  -0.1
[Temperature Range]   25   125   -40
[Voltage Range]   1.5   1.425   1.575
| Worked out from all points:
|   slope of the pulldown table from 0 to 0.225 V, typ, clamps not added: 43 ohm
|   slope of the pullup table from 0 to 0.225 V, typ, clamps not added: 41.7 ohm
|   GND clamp passes 1 mA (typ) near -0.48 V on its own axis
|   POWER clamp passes 1 mA (typ) near -0.62 V on its own axis
|   rising waveform, R_fixture 50, V_fixture 1.5: 20-80 % time 165ps typ, 358ps min, 92.8ps max; typ from 0.695 V to 1.5 V
|   rising waveform, R_fixture 50, V_fixture 0: 20-80 % time 162ps typ, 350ps min, 92.7ps max; typ from 0 V to 0.817 V
|   falling waveform, R_fixture 50, V_fixture 1.5: 20-80 % time 160ps typ, 327ps min, 92.2ps max; typ from 1.5 V to 0.695 V
|   falling waveform, R_fixture 50, V_fixture 0: 20-80 % time 162ps typ, 339ps min, 92.9ps max; typ from 0.817 V to 0 V
[POWER_clamp]
-1.5V     302.8mA    223.9mA    484.4mA
-1.242V   174.3mA    127.3mA    279.1mA
-1.136V   123.3mA    89.68mA    196.8mA
-1.045V   81.65mA    59.62mA    128.8mA
-1.03V    75mA       54.92mA    117.8mA
-939.4mV  38.44mA    29.91mA    56.84mA
-893.9mV  23.93mA    20.41mA    32.31mA
-848.5mV  13.61mA    13.43mA    15.91mA
-803mV    7.623mA    8.663mA    8.564mA
-712.1mV  3.022mA    3.561mA    3.877mA
-575.8mV  470.5uA    872uA      449uA
0V        112.6nA    435.6nA    613.8nA
[Pulldown]
-1.5V     -14.18mA   -14.05mA   -13.7mA
-727.3mV  -12.54mA   -12.27mA   -12.15mA
-545.5mV  -11.35mA   -10.95mA   -11.1mA
-409.1mV  -9.378mA   -8.925mA   -9.416mA
1.227V    28.16mA    26.58mA    28.43mA
1.818V    41.23mA    38.42mA    41.56mA
2V        45.11mA    41.2mA     45.49mA
2.182V    47.62mA    41.92mA    48.94mA
2.273V    47.99mA    41.65mA    49.78mA
2.364V    47.57mA    41.06mA    50.1mA
2.545V    46.7mA     39.96mA    47.58mA
3V        46.28mA    36.09mA    47.12mA
[Pullup]
-1.5V     17.97mA    16.01mA    17.82mA
-1V       16.28mA    15.23mA    16.1mA
-772.7mV  15.66mA    14.54mA    16.02mA
-590.9mV  13.75mA    12.97mA    14.08mA
-409.1mV  9.799mA    9.534mA    9.955mA
1.409V    -33.42mA   -32.26mA   -33.94mA
1.773V    -41.87mA   -40.19mA   -42.52mA
1.909V    -44.87mA   -42.6mA    -45.68mA
2.091V    -47.15mA   -44.23mA   -48.65mA
2.318V    -48.13mA   -44.93mA   -50.11mA
2.591V    -48.02mA   -44.49mA   -49.82mA
3V        -48.22mA   -43.8mA    -50.51mA
[GND_clamp]
-1.5V     -133.6mA   -115.7mA   -234.3mA
-1.288V   -87.29mA   -67.59mA   -156.8mA
-1.197V   -68.11mA   -48.64mA   -124.4mA
-1.045V   -38.25mA   -22.77mA   -72.51mA
-1.015V   -32.88mA   -19.1mA    -62.74mA
-954.5mV  -23.3mA    -13.72mA   -44.4mA
-863.6mV  -13.6mA    -9.192mA   -23.11mA
-803mV    -10.18mA   -7.193mA   -15.89mA
-681.8mV  -5.771mA   -4.027mA   -9.287mA
-500mV    -1.264mA   -914.7uA   -2.429mA
-348.5mV  -52.39uA   -75.11uA   -85.87uA
1.5V      112.6nA    528.1nA    514.5nA
[Ramp]
dV/dt_f 0.48384451/0.16049541n 0.44934776/0.32888063n 0.51011652/92.273319p
dV/dt_r 0.49182961/0.16302577n 0.46154893/0.35197798n  0.5195987/92.892453p
R_load =  50
[Rising Waveform]
R_fixture =  50
V_fixture =  1.5
V_fixture_min =  1.425
V_fixture_max =  1.575
0s        694.7mV    677.7mV    726.4mV
47.82ps   694.1mV    677.6mV    879.5mV
125.2ps   696.7mV    677.6mV    1.267V
156.2ps   802.7mV    677.6mV    1.464V
199.2ps   891.1mV    677.7mV    1.544V
364.8ps   1.41V      675.7mV    1.571V
404.9ps   1.471V     719.4mV    1.572V
447.9ps   1.489V     819.9mV    1.573V
864.6ps   1.499V     1.384V     1.575V
1.053ns   1.5V       1.425V     1.575V
[Rising Waveform]
R_fixture =  50
V_fixture =  0
V_fixture_min =  0
V_fixture_max =  0
2.649ps   0V         0V         0V
50.37ps   0V         0V         150.4mV
129.3ps   0V         0V         556.2mV
160.4ps   102.5mV    0V         753.3mV
204.5ps   200mV      0V         835.2mV
370.6ps   727mV      -3.13mV    861.1mV
411.6ps   789.3mV    31.55mV    861.8mV
459.9ps   807.4mV    137.8mV    862.4mV
874.9ps   816.2mV    719.2mV    864mV
1.055ns   817.1mV    766.1mV    864.1mV
[Falling Waveform]
R_fixture =  50
V_fixture =  1.5
V_fixture_min =  1.425
V_fixture_max =  1.575
0s        1.5V       1.425V     1.575V
28.72ps   1.5V       1.425V     1.561V
63.22ps   1.5V       1.425V     1.433V
153.5ps   1.495V     1.425V     945.8mV
180ps     1.428V     1.425V     818.4mV
219.3ps   1.335V     1.425V     755.8mV
394.6ps   790.3mV    1.426V     729mV
436.6ps   724.8mV    1.426V     728.1mV
927ps     695.6mV    731.3mV    725.5mV
1.053ns   694.7mV    677.7mV    725.4mV
[Falling Waveform]
R_fixture =  50
V_fixture =  0
V_fixture_min =  0
V_fixture_max =  0
2.649ps   817.1mV    766.1mV    864.1mV
26.41ps   817.2mV    766.1mV    846.4mV
60.32ps   817.2mV    766.1mV    711.9mV
149.1ps   812mV      766.2mV    228.9mV
175.8ps   739.1mV    766.1mV    94.06mV
213.8ps   646.5mV    766.1mV    31.37mV
390.6ps   91.49mV    766.4mV    2.84mV
430.2ps   30.35mV    764.7mV    2.009mV
917.7ps   0V         48.58mV    0V
1.055ns   0V         0V         0V
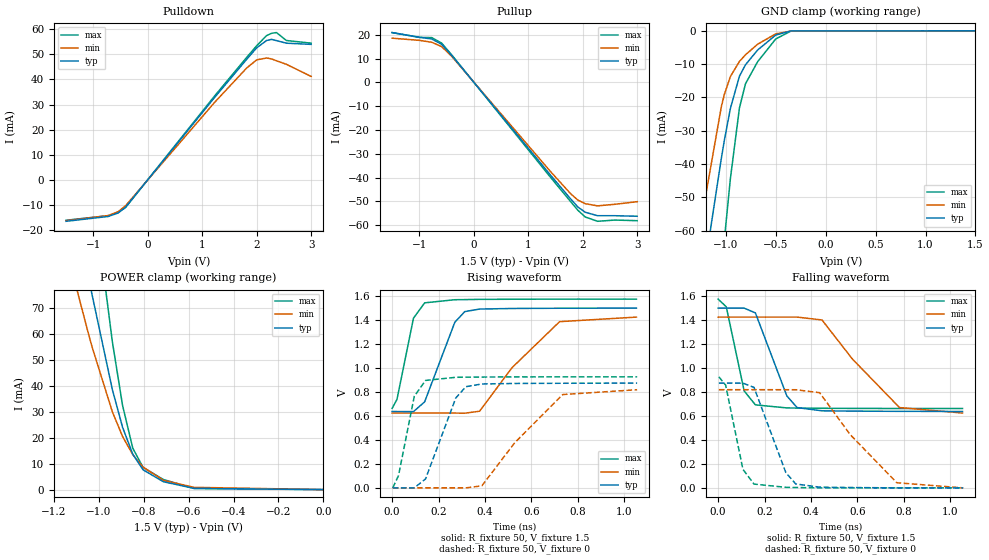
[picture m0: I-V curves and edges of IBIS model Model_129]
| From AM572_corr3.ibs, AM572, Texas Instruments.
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| Model based on original model for DDR_SEIOPB_H
|   Sub model SR010_DRV34_1P5
[model]   Model_129
|[Description]  [1.5V-I/O-X-X]
|   , ,
|[Input Load]
|[Output Drive]
|Voltage   1.5V
|Mode   I/O
Model_type   I/O
Polarity   Non-Inverting
Enable   Active-Low
Vinl =   0.65
Vinh =   0.85
Cref =   15.0000pF
Rref =   100.0000M
Vref =   0V
Vmeas =   0.75
C_comp   2p   2p   2p
[Model Spec]
Vinl   0.65   0.6125   0.6875
Vinh   0.85   0.8125   0.8875
[Receiver Thresholds]
Tslew_ac =  0.5n
Vth =  0.75
Vth_max =  0.7875
Vth_min =  0.675
Vinh_ac =  0.175
Vinh_dc =  0.1
Vinl_ac =  -0.175
Vinl_dc =  -0.1
[Temperature Range]   25   125   -40
[Voltage Range]   1.5   1.425   1.575
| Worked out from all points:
|   slope of the pulldown table from 0 to 0.225 V, typ, clamps not added: 36.8 ohm
|   slope of the pullup table from 0 to 0.225 V, typ, clamps not added: 35.8 ohm
|   GND clamp passes 1 mA (typ) near -0.48 V on its own axis
|   POWER clamp passes 1 mA (typ) near -0.62 V on its own axis
|   rising waveform, R_fixture 50, V_fixture 1.5: 20-80 % time 100ps typ, 242ps min, 55.8ps max; typ from 0.637 V to 1.5 V
|   rising waveform, R_fixture 50, V_fixture 0: 20-80 % time 99.3ps typ, 236ps min, 56ps max; typ from 0 V to 0.874 V
|   falling waveform, R_fixture 50, V_fixture 1.5: 20-80 % time 99.7ps typ, 222ps min, 57.6ps max; typ from 1.5 V to 0.637 V
|   falling waveform, R_fixture 50, V_fixture 0: 20-80 % time 99.9ps typ, 227ps min, 57.1ps max; typ from 0.874 V to 0 V
[POWER_clamp]
-1.5V     302.8mA    223.9mA    484.4mA
-1.242V   174.3mA    127.3mA    279.1mA
-1.136V   123.3mA    89.68mA    196.8mA
-1.045V   81.65mA    59.62mA    128.8mA
-1.03V    75mA       54.92mA    117.8mA
-939.4mV  38.44mA    29.91mA    56.84mA
-893.9mV  23.93mA    20.41mA    32.31mA
-848.5mV  13.61mA    13.43mA    15.91mA
-803mV    7.623mA    8.663mA    8.564mA
-712.1mV  3.022mA    3.561mA    3.877mA
-575.8mV  470.5uA    872uA      449uA
0V        112.6nA    435.6nA    613.8nA
[Pulldown]
-1.5V     -16.54mA   -16.32mA   -16.11mA
-727.3mV  -14.62mA   -14.26mA   -14.29mA
-545.5mV  -13.24mA   -12.72mA   -13.05mA
-409.1mV  -10.94mA   -10.36mA   -11.07mA
1.227V    32.84mA    30.87mA    33.41mA
1.818V    48.09mA    44.61mA    48.84mA
2V        52.62mA    47.82mA    53.46mA
2.182V    55.55mA    48.58mA    57.5mA
2.273V    55.99mA    48.2mA     58.42mA
2.364V    55.5mA     47.46mA    58.71mA
2.545V    54.48mA    46.06mA    55.55mA
3V        54mA       41.23mA    54.49mA
[Pullup]
-1.5V     20.96mA    18.6mA     20.95mA
-1V       19mA       17.69mA    18.93mA
-772.7mV  18.26mA    16.89mA    18.84mA
-590.9mV  16.04mA    15.07mA    16.54mA
-409.1mV  11.43mA    11.07mA    11.7mA
1.409V    -38.97mA   -37.46mA   -39.88mA
1.773V    -48.83mA   -46.66mA   -49.96mA
1.909V    -52.33mA   -49.44mA   -53.68mA
2.045V    -54.57mA   -50.97mA   -56.55mA
2.273V    -56.03mA   -51.89mA   -58.38mA
2.591V    -56.03mA   -51.23mA   -57.86mA
3V        -56.26mA   -50.14mA   -58.12mA
[GND_clamp]
-1.5V     -133.6mA   -115.7mA   -234.3mA
-1.288V   -87.29mA   -67.59mA   -156.8mA
-1.197V   -68.11mA   -48.64mA   -124.4mA
-1.045V   -38.25mA   -22.77mA   -72.51mA
-1.015V   -32.88mA   -19.1mA    -62.74mA
-954.5mV  -23.3mA    -13.72mA   -44.4mA
-863.6mV  -13.6mA    -9.192mA   -23.11mA
-803mV    -10.18mA   -7.193mA   -15.89mA
-681.8mV  -5.771mA   -4.027mA   -9.287mA
-500mV    -1.264mA   -914.7uA   -2.429mA
-348.5mV  -52.39uA   -75.11uA   -85.87uA
1.5V      112.6nA    528.1nA    514.5nA
[Ramp]
dV/dt_f 0.51818867/99.763667p 0.48136236/0.22283151n 0.54803399/57.607376p
dV/dt_r 0.52646955/99.76841p  0.49342891/0.23750758n 0.55793354/56.100375p
R_load =  50
[Rising Waveform]
R_fixture =  50
V_fixture =  1.5
V_fixture_min =  1.425
V_fixture_max =  1.575
0s        637.3mV    624.3mV    663.1mV
21.04ps   636.8mV    624.2mV    738.2mV
92.12ps   636.3mV    624.2mV    1.416V
140.2ps   717.7mV    624.2mV    1.544V
270.3ps   1.382V     624.1mV    1.57V
313.2ps   1.471V     623.1mV    1.571V
376.7ps   1.492V     639.5mV    1.573V
516.9ps   1.497V     1.003V     1.574V
721.7ps   1.499V     1.387V     1.575V
1.053ns   1.5V       1.425V     1.575V
[Rising Waveform]
R_fixture =  50
V_fixture =  0
V_fixture_min =  0
V_fixture_max =  0
2.954ps   0V         0V         0V
27.64ps   0V         0V         102.4mV
95.61ps   0V         0V         764.4mV
144.2ps   74.87mV    0V         896.6mV
274.4ps   749.8mV    0V         922.5mV
317.8ps   844.3mV    0V         923.7mV
386.8ps   866.9mV    16.92mV    924.8mV
528ps     871.2mV    375.6mV    926mV
735.3ps   872.9mV    778.8mV    926.5mV
1.056ns   874.1mV    819mV      926.7mV
[Falling Waveform]
R_fixture =  50
V_fixture =  1.5
V_fixture_min =  1.425
V_fixture_max =  1.575
0s        1.5V       1.425V     1.575V
35.09ps   1.5V       1.425V     1.511V
112.1ps   1.5V       1.425V     809.3mV
160.6ps   1.46V      1.425V     692.6mV
296.2ps   766.9mV    1.425V     667.1mV
340.4ps   669.7mV    1.425V     665.9mV
447.6ps   643.1mV    1.401V     664.1mV
579.1ps   640.3mV    1.074V     663mV
781.6ps   638.6mV    670.1mV    662.5mV
1.053ns   637.3mV    624.3mV    662.3mV
[Falling Waveform]
R_fixture =  50
V_fixture =  0
V_fixture_min =  0
V_fixture_max =  0
2.954ps   874.1mV    819mV      926.7mV
32.39ps   874.3mV    819.1mV    857.4mV
106.9ps   873.9mV    819.1mV    154.5mV
154.7ps   838.3mV    819.1mV    31.55mV
291.9ps   126.8mV    819mV      4.347mV
334.5ps   32.42mV    818.8mV    3.031mV
437.3ps   5.854mV    794.2mV    0V
569.4ps   2.773mV    443.8mV    0V
770.1ps   0V         42.46mV    0V
1.056ns   0V         0V         0V
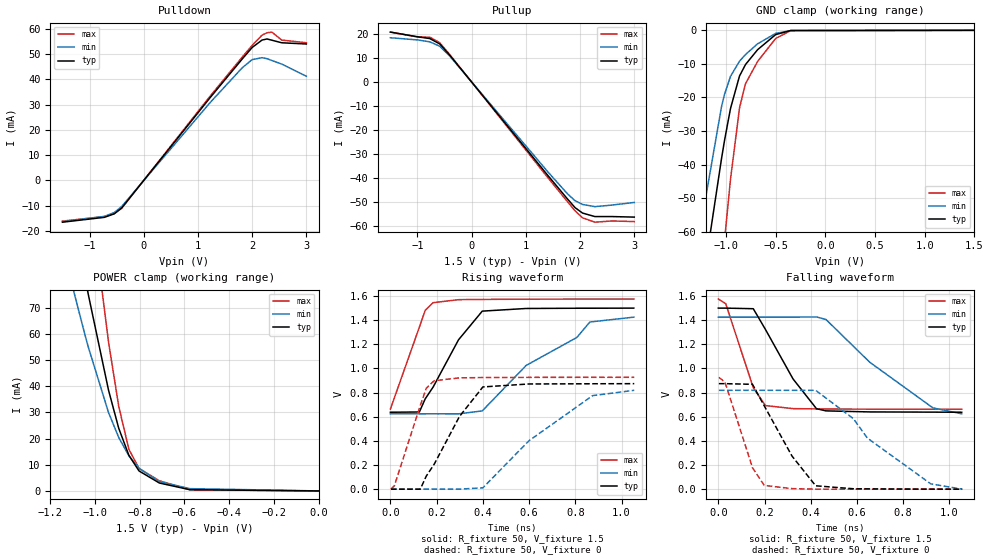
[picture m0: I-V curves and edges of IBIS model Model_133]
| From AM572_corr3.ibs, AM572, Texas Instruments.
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| Model based on original model for DDR_SEIOPB_H
|   Sub model SR111_DRV34_1P5
[model]   Model_133
|[Description]  [1.5V-I/O-X-X]
|   , ,
|[Input Load]
|[Output Drive]
|Voltage   1.5V
|Mode   I/O
Model_type   I/O
Polarity   Non-Inverting
Enable   Active-Low
Vinl =   0.65
Vinh =   0.85
Cref =   15.0000pF
Rref =   100.0000M
Vref =   0V
Vmeas =   0.75
C_comp   2p   2p   2p
[Model Spec]
Vinl   0.65   0.6125   0.6875
Vinh   0.85   0.8125   0.8875
[Receiver Thresholds]
Tslew_ac =  0.5n
Vth =  0.75
Vth_max =  0.7875
Vth_min =  0.675
Vinh_ac =  0.175
Vinh_dc =  0.1
Vinl_ac =  -0.175
Vinl_dc =  -0.1
[Temperature Range]   25   125   -40
[Voltage Range]   1.5   1.425   1.575
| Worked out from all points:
|   slope of the pulldown table from 0 to 0.225 V, typ, clamps not added: 36.8 ohm
|   slope of the pullup table from 0 to 0.225 V, typ, clamps not added: 35.8 ohm
|   GND clamp passes 1 mA (typ) near -0.48 V on its own axis
|   POWER clamp passes 1 mA (typ) near -0.62 V on its own axis
|   rising waveform, R_fixture 50, V_fixture 1.5: 20-80 % time 173ps typ, 368ps min, 93.9ps max; typ from 0.637 V to 1.5 V
|   rising waveform, R_fixture 50, V_fixture 0: 20-80 % time 170ps typ, 362ps min, 92.8ps max; typ from 0 V to 0.874 V
|   falling waveform, R_fixture 50, V_fixture 1.5: 20-80 % time 166ps typ, 346ps min, 92.9ps max; typ from 1.5 V to 0.637 V
|   falling waveform, R_fixture 50, V_fixture 0: 20-80 % time 168ps typ, 352ps min, 93.2ps max; typ from 0.874 V to 0 V
[POWER_clamp]
-1.5V     302.8mA    223.9mA    484.4mA
-1.242V   174.3mA    127.3mA    279.1mA
-1.136V   123.3mA    89.68mA    196.8mA
-1.045V   81.65mA    59.62mA    128.8mA
-1.03V    75mA       54.92mA    117.8mA
-939.4mV  38.44mA    29.91mA    56.84mA
-893.9mV  23.93mA    20.41mA    32.31mA
-848.5mV  13.61mA    13.43mA    15.91mA
-803mV    7.623mA    8.663mA    8.564mA
-712.1mV  3.022mA    3.561mA    3.877mA
-575.8mV  470.5uA    872uA      449uA
0V        112.6nA    435.6nA    613.8nA
[Pulldown]
-1.5V     -16.54mA   -16.32mA   -16.11mA
-727.3mV  -14.62mA   -14.26mA   -14.29mA
-545.5mV  -13.24mA   -12.72mA   -13.05mA
-409.1mV  -10.94mA   -10.36mA   -11.07mA
1.227V    32.84mA    30.87mA    33.41mA
1.818V    48.09mA    44.61mA    48.84mA
2V        52.62mA    47.82mA    53.46mA
2.182V    55.55mA    48.58mA    57.5mA
2.273V    55.99mA    48.2mA     58.42mA
2.364V    55.5mA     47.46mA    58.71mA
2.545V    54.48mA    46.06mA    55.55mA
3V        54mA       41.23mA    54.49mA
[Pullup]
-1.5V     20.96mA    18.6mA     20.95mA
-1V       19mA       17.69mA    18.93mA
-772.7mV  18.26mA    16.89mA    18.84mA
-590.9mV  16.04mA    15.07mA    16.54mA
-409.1mV  11.43mA    11.07mA    11.7mA
1.409V    -38.97mA   -37.46mA   -39.88mA
1.773V    -48.83mA   -46.66mA   -49.96mA
1.909V    -52.33mA   -49.44mA   -53.68mA
2.045V    -54.57mA   -50.97mA   -56.55mA
2.273V    -56.03mA   -51.89mA   -58.38mA
2.591V    -56.03mA   -51.23mA   -57.86mA
3V        -56.26mA   -50.14mA   -58.12mA
[GND_clamp]
-1.5V     -133.6mA   -115.7mA   -234.3mA
-1.288V   -87.29mA   -67.59mA   -156.8mA
-1.197V   -68.11mA   -48.64mA   -124.4mA
-1.045V   -38.25mA   -22.77mA   -72.51mA
-1.015V   -32.88mA   -19.1mA    -62.74mA
-954.5mV  -23.3mA    -13.72mA   -44.4mA
-863.6mV  -13.6mA    -9.192mA   -23.11mA
-803mV    -10.18mA   -7.193mA   -15.89mA
-681.8mV  -5.771mA   -4.027mA   -9.287mA
-500mV    -1.264mA   -914.7uA   -2.429mA
-348.5mV  -52.39uA   -75.11uA   -85.87uA
1.5V      112.6nA    528.1nA    514.5nA
[Ramp]
dV/dt_f  0.5184208/0.16650507n 0.48157253/0.34697508n 0.54815265/93.048661p
dV/dt_r 0.52643212/0.17117935n 0.49371973/0.36366008n 0.55768225/93.202655p
R_load =  50
[Rising Waveform]
R_fixture =  50
V_fixture =  1.5
V_fixture_min =  1.425
V_fixture_max =  1.575
0s        637.3mV    624.3mV    663.3mV
125.3ps   639.4mV    624.2mV    1.342V
150.7ps   748.5mV    624.2mV    1.482V
184.8ps   845.7mV    624.3mV    1.545V
294.6ps   1.237V     624.1mV    1.57V
397.4ps   1.475V     648.4mV    1.572V
587.2ps   1.497V     1.025V     1.574V
806.7ps   1.499V     1.257V     1.575V
863ps     1.499V     1.385V     1.575V
1.053ns   1.5V       1.425V     1.575V
[Rising Waveform]
R_fixture =  50
V_fixture =  0
V_fixture_min =  0
V_fixture_max =  0
2.527ps   0V         0V         0V
17.3ps    0V         0V         28.41mV
129.3ps   0V         0V         692.7mV
155.4ps   108.7mV    0V         836.6mV
189.3ps   206mV      0V         898.3mV
298.9ps   602.4mV    0V         922.3mV
400.2ps   847mV      11.22mV    924.6mV
598.9ps   871.5mV    400.3mV    926.2mV
874.9ps   873.3mV    775mV      926.6mV
1.055ns   874.1mV    819mV      926.7mV
[Falling Waveform]
R_fixture =  50
V_fixture =  1.5
V_fixture_min =  1.425
V_fixture_max =  1.575
0s        1.5V       1.425V     1.575V
32.03ps   1.5V       1.425V     1.537V
151.3ps   1.495V     1.425V     840.6mV
203.7ps   1.324V     1.425V     692.6mV
323.2ps   913.4mV    1.425V     667.3mV
424.6ps   667mV      1.427V     664.8mV
465.6ps   648.6mV    1.406V     664.2mV
655ps     640mV      1.052V     662.8mV
928.1ps   638.2mV    673.7mV    662.4mV
1.053ns   637.3mV    624.3mV    662.3mV
[Falling Waveform]
R_fixture =  50
V_fixture =  0
V_fixture_min =  0
V_fixture_max =  0
2.527ps   874.1mV    819mV      926.7mV
29.11ps   874.2mV    819mV      886mV
147.9ps   868.5mV    819.1mV    177.5mV
198.6ps   690.9mV    819mV      31.08mV
319ps     273.7mV    818.8mV    4.462mV
421.2ps   27.92mV    819mV      0V
584ps     3.393mV    584.3mV    0V
645ps     2.456mV    423.3mV    0V
918.9ps   0V         44.12mV    0V
1.055ns   0V         0V         0V
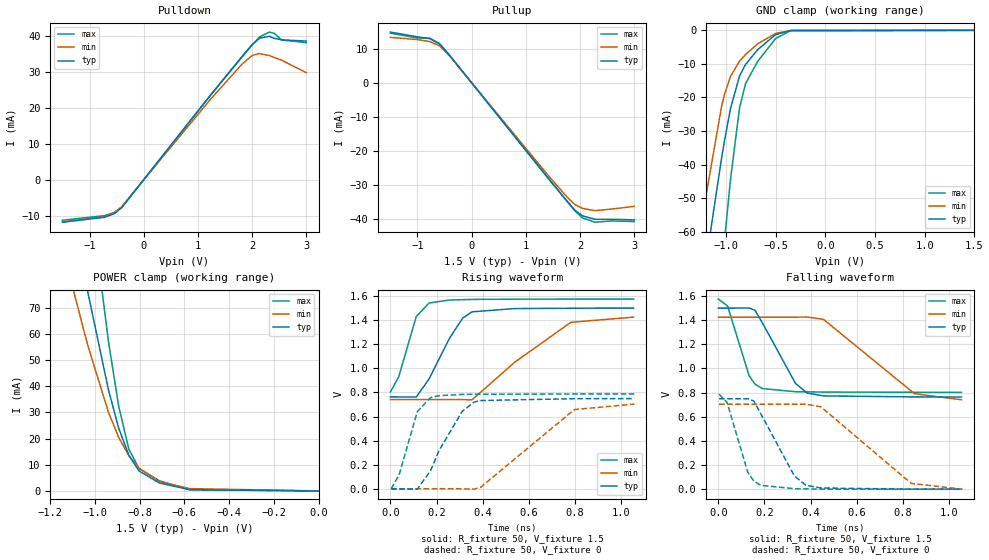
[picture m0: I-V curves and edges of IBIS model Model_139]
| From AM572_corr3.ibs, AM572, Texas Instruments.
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| Model based on original model for DDR_SEIOPB_H
|   Sub model SR100_DRV48_1P5
[model]   Model_139
|[Description]  [1.5V-I/O-X-X]
|   , ,
|[Input Load]
|[Output Drive]
|Voltage   1.5V
|Mode   I/O
Model_type   I/O
Polarity   Non-Inverting
Enable   Active-Low
Vinl =   0.65
Vinh =   0.85
Cref =   15.0000pF
Rref =   100.0000M
Vref =   0V
Vmeas =   0.75
C_comp   2p   2p   2p
[Model Spec]
Vinl   0.65   0.6125   0.6875
Vinh   0.85   0.8125   0.8875
[Receiver Thresholds]
Tslew_ac =  0.5n
Vth =  0.75
Vth_max =  0.7875
Vth_min =  0.675
Vinh_ac =  0.175
Vinh_dc =  0.1
Vinl_ac =  -0.175
Vinl_dc =  -0.1
[Temperature Range]   25   125   -40
[Voltage Range]   1.5   1.425   1.575
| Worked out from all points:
|   slope of the pulldown table from 0 to 0.225 V, typ, clamps not added: 51.5 ohm
|   slope of the pullup table from 0 to 0.225 V, typ, clamps not added: 50.1 ohm
|   GND clamp passes 1 mA (typ) near -0.48 V on its own axis
|   POWER clamp passes 1 mA (typ) near -0.62 V on its own axis
|   rising waveform, R_fixture 50, V_fixture 1.5: 20-80 % time 126ps typ, 301ps min, 69.5ps max; typ from 0.763 V to 1.5 V
|   rising waveform, R_fixture 50, V_fixture 0: 20-80 % time 125ps typ, 295ps min, 69.8ps max; typ from 0 V to 0.749 V
|   falling waveform, R_fixture 50, V_fixture 1.5: 20-80 % time 125ps typ, 281ps min, 71ps max; typ from 1.5 V to 0.763 V
|   falling waveform, R_fixture 50, V_fixture 0: 20-80 % time 126ps typ, 287ps min, 70.4ps max; typ from 0.749 V to 0 V
[POWER_clamp]
-1.5V     302.8mA    223.9mA    484.4mA
-1.242V   174.3mA    127.3mA    279.1mA
-1.136V   123.3mA    89.68mA    196.8mA
-1.045V   81.65mA    59.62mA    128.8mA
-1.03V    75mA       54.92mA    117.8mA
-939.4mV  38.44mA    29.91mA    56.84mA
-893.9mV  23.93mA    20.41mA    32.31mA
-848.5mV  13.61mA    13.43mA    15.91mA
-803mV    7.623mA    8.663mA    8.564mA
-712.1mV  3.022mA    3.561mA    3.877mA
-575.8mV  470.5uA    872uA      449uA
0V        112.6nA    435.6nA    613.8nA
[Pulldown]
-1.5V     -11.81mA   -11.79mA   -11.27mA
-727.3mV  -10.45mA   -10.3mA    -10mA
-545.5mV  -9.463mA   -9.189mA   -9.136mA
-409.1mV  -7.817mA   -7.49mA    -7.751mA
1.227V    23.47mA    22.31mA    23.4mA
1.818V    34.37mA    32.24mA    34.22mA
2V        37.61mA    34.55mA    37.45mA
2.136V    39.37mA    35.1mA     39.71mA
2.318V    39.9mA     34.55mA    41.07mA
2.409V    39.32mA    34mA       40.72mA
2.545V    38.91mA    33.26mA    38.88mA
3V        38.57mA    29.76mA    38.14mA
[Pullup]
-1.5V     14.98mA    13.43mA    14.66mA
-1V       13.57mA    12.78mA    13.25mA
-772.7mV  13.05mA    12.2mA     13.19mA
-590.9mV  11.46mA    10.89mA    11.59mA
-409.1mV  8.169mA    8.001mA    8.195mA
1.409V    -27.86mA   -27.07mA   -27.94mA
1.773V    -34.91mA   -33.72mA   -35mA
1.909V    -37.4mA    -35.72mA   -37.61mA
2.045V    -38.99mA   -36.82mA   -39.6mA
2.273V    -40.02mA   -37.48mA   -40.87mA
2.591V    -40.02mA   -37mA      -40.5mA
3V        -40.19mA   -36.21mA   -40.69mA
[GND_clamp]
-1.5V     -133.6mA   -115.7mA   -234.3mA
-1.288V   -87.29mA   -67.59mA   -156.8mA
-1.197V   -68.11mA   -48.64mA   -124.4mA
-1.045V   -38.25mA   -22.77mA   -72.51mA
-1.015V   -32.88mA   -19.1mA    -62.74mA
-954.5mV  -23.3mA    -13.72mA   -44.4mA
-863.6mV  -13.6mA    -9.192mA   -23.11mA
-803mV    -10.18mA   -7.193mA   -15.89mA
-681.8mV  -5.771mA   -4.027mA   -9.287mA
-500mV    -1.264mA   -914.7uA   -2.429mA
-348.5mV  -52.39uA   -75.11uA   -85.87uA
1.5V      112.6nA    528.1nA    514.5nA
[Ramp]
dV/dt_f 0.44251968/0.12525455n 0.41138958/0.28219457n 0.46379358/71.007829p
dV/dt_r 0.45069069/0.12510149n 0.42380059/0.29644022n  0.4737608/69.91952p
R_load =  50
[Rising Waveform]
R_fixture =  50
V_fixture =  1.5
V_fixture_min =  1.425
V_fixture_max =  1.575
0s        763.3mV    740.8mV    803.2mV
35.8ps    762.6mV    740.7mV    928.9mV
112ps     761.6mV    740.7mV    1.43V
167.2ps   911.3mV    740.8mV    1.542V
255.2ps   1.247V     740.4mV    1.567V
313.2ps   1.417V     740.3mV    1.57V
353.7ps   1.469V     738.8mV    1.572V
538.5ps   1.496V     1.051V     1.574V
781.4ps   1.499V     1.382V     1.575V
1.053ns   1.5V       1.425V     1.575V
[Rising Waveform]
R_fixture =  50
V_fixture =  0
V_fixture_min =  0
V_fixture_max =  0
3.237ps   0V         0V         0V
38.52ps   0V         0V         119.7mV
116.4ps   -2.411mV   0V         640.4mV
173.3ps   147.5mV    0V         756.4mV
211.1ps   319mV      0V         773.5mV
310.3ps   640.7mV    0V         783.2mV
361.1ps   719mV      -3.069mV   784.6mV
390.4ps   732.7mV    12.1mV     785.1mV
796.6ps   747.7mV    657.5mV    787.2mV
1.056ns   748.7mV    703.3mV    787.3mV
[Falling Waveform]
R_fixture =  50
V_fixture =  1.5
V_fixture_min =  1.425
V_fixture_max =  1.575
0s        1.5V       1.425V     1.575V
40.04ps   1.5V       1.425V     1.518V
133.6ps   1.501V     1.425V     938.2mV
159.1ps   1.482V     1.425V     869.7mV
190.5ps   1.379V     1.425V     833.6mV
334.3ps   876.1mV    1.425V     807.3mV
385.1ps   795.9mV    1.426V     805.9mV
455.3ps   772.7mV    1.407V     804.6mV
849.7ps   764.4mV    790.7mV    802.7mV
1.053ns   763.3mV    740.8mV    802.5mV
[Falling Waveform]
R_fixture =  50
V_fixture =  0
V_fixture_min =  0
V_fixture_max =  0
3.237ps   748.7mV    703.3mV    787.3mV
38.01ps   748.9mV    703.3mV    718.8mV
127.6ps   749mV      703.3mV    140.3mV
153.7ps   730.9mV    703.3mV    67.46mV
183.9ps   624.8mV    703.3mV    31.81mV
329.6ps   109.3mV    703.1mV    4.025mV
379.1ps   32mV       703.6mV    2.58mV
444ps     9.837mV    682.7mV    0V
835.1ps   0V         47.74mV    0V
1.056ns   0V         0V         0V
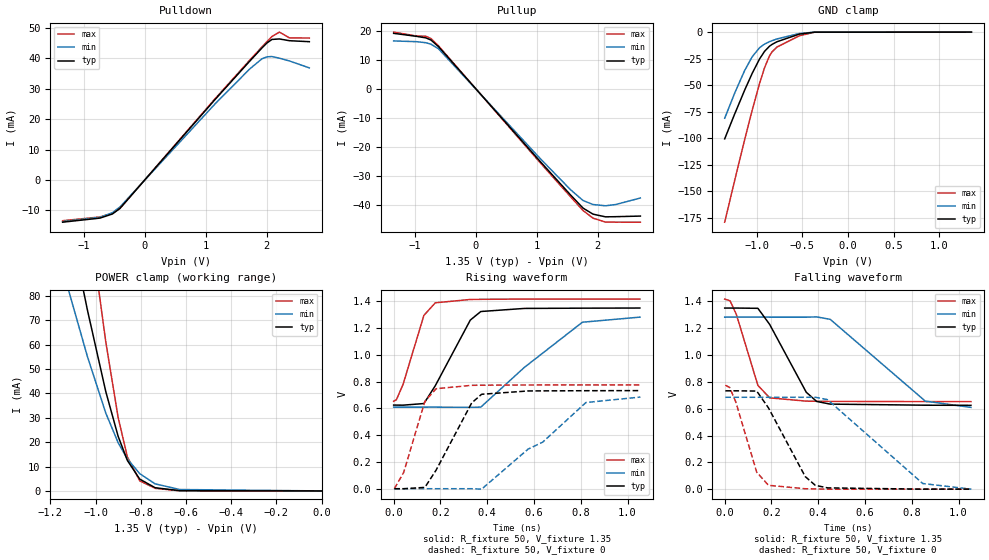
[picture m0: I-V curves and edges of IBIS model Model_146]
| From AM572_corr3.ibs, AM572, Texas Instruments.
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| Model based on original model for DDR_SEIOPB_H
|   Sub model SR101_DRV40_1P35
[model]   Model_146
|[Description]  [1.35V-I/O-X-X]
|   , ,
|[Input Load]
|[Output Drive]
|Voltage   1.35V
|Mode   I/O
Model_type   I/O
Polarity   Non-Inverting
Enable   Active-Low
Vinl =   0.585
Vinh =   0.765
Cref =   15.0000pF
Rref =   100.0000M
Vref =   0V
Vmeas =   0.675
C_comp   2p   2p   2p
[Model Spec]
Vinl   0.585   0.55125   0.61875
Vinh   0.765   0.73125   0.79875
[Receiver Thresholds]
Tslew_ac =  5n
Vth =  0.675
Vth_max =  0.709
Vth_min =  0.608
Vinh_ac =  0.175
Vinh_dc =  0.1
Vinl_ac =  -0.175
Vinl_dc =  -0.1
[Temperature Range]   25   125   -40
[Voltage Range]   1.35   1.2825   1.4175
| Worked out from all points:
|   slope of the pulldown table from 0 to 0.203 V, typ, clamps not added: 43 ohm
|   slope of the pullup table from 0 to 0.203 V, typ, clamps not added: 42 ohm
|   GND clamp passes 1 mA (typ) near -0.48 V on its own axis
|   POWER clamp passes 1 mA (typ) near -0.72 V on its own axis
|   rising waveform, R_fixture 50, V_fixture 1.35: 20-80 % time 135ps typ, 304ps min, 78ps max; typ from 0.625 V to 1.35 V
|   rising waveform, R_fixture 50, V_fixture 0: 20-80 % time 134ps typ, 294ps min, 77.9ps max; typ from 0 V to 0.733 V
|   falling waveform, R_fixture 50, V_fixture 1.35: 20-80 % time 133ps typ, 278ps min, 77.7ps max; typ from 1.35 V to 0.625 V
|   falling waveform, R_fixture 50, V_fixture 0: 20-80 % time 134ps typ, 288ps min, 77.8ps max; typ from 0.733 V to 0 V
[POWER_clamp]
-1.35V    224.4mA    165.8mA    358.5mA
-1.214V   157mA      115.5mA    250.8mA
-1.132V   117.8mA    86.59mA    187.7mA
-1.118V   111.4mA    81.92mA    177.3mA
-1.036V   74.26mA    55.16mA    116.8mA
-954.5mV  40.7mA     31.91mA    61.06mA
-900mV    22.42mA    19.79mA    30.14mA
-859.1mV  12.48mA    13.09mA    13.96mA
-804.5mV  4.85mA     7.084mA    4.132mA
-736.4mV  1.313mA    2.9mA      1.073mA
-627.3mV  101.6uA    577.3uA    45.9uA
0V        75.63nA    322.4nA    418.5nA
[Pulldown]
-1.35V    -13.93mA   -13.71mA   -13.45mA
-736.4mV  -12.58mA   -12.32mA   -12.19mA
-531.8mV  -11.22mA   -10.8mA    -10.99mA
-409.1mV  -9.378mA   -8.926mA   -9.416mA
1.145V    26.32mA    24.88mA    26.57mA
1.718V    39.05mA    36.49mA    39.37mA
1.923V    43.49mA    39.91mA    43.83mA
2.005V    45.12mA    40.54mA    45.58mA
2.086V    46.28mA    40.65mA    47.24mA
2.209V    46.44mA    40.1mA     48.7mA
2.373V    45.86mA    39.19mA    46.8mA
2.7V      45.54mA    36.91mA    46.74mA
[Pullup]
-1.35V    19.14mA    16.53mA    19.57mA
-981.8mV  18.13mA    16.28mA    18.23mA
-818.2mV  17.57mA    15.91mA    18.13mA
-736.4mV  16.82mA    15.4mA     17.33mA
-613.6mV  14.56mA    13.83mA    14.83mA
1.064V    -25.08mA   -24.06mA   -25.52mA
1.555V    -36.41mA   -34.6mA    -37.03mA
1.759V    -40.9mA    -38.29mA   -41.73mA
1.923V    -42.98mA   -39.67mA   -44.36mA
2.127V    -43.9mA    -40.1mA    -45.7mA
2.291V    -43.85mA   -39.69mA   -45.73mA
2.7V      -43.64mA   -37.43mA   -45.74mA
[GND_clamp]
-1.35V    -100.7mA   -81.27mA   -179.3mA
-1.241V   -77.31mA   -57.61mA   -140mA
-1.132V   -54.83mA   -36.31mA   -101.6mA
-1.05V    -39.08mA   -23.36mA   -74mA
-968.2mV  -25.28mA   -14.71mA   -48.34mA
-913.6mV  -18.13mA   -11.32mA   -33.52mA
-859.1mV  -13.28mA   -9.024mA   -22.35mA
-831.8mV  -11.61mA   -8.091mA   -18.64mA
-777.3mV  -9.078mA   -6.444mA   -14.07mA
-531.8mV  -1.871mA   -1.307mA   -3.441mA
-368.2mV  -88.76uA   -111.2uA   -158uA
1.35V     75.63nA    385.5nA    349.4nA
[Ramp]
dV/dt_f  0.4356587/0.13353681n  0.4049041/0.27902799n 0.45939591/77.72189p
dV/dt_r 0.44156972/0.13493078n 0.41316128/0.29739635n 0.46698286/78.200743p
R_load =  50
[Rising Waveform]
R_fixture =  50
V_fixture =  1.35
V_fixture_min =  1.2825
V_fixture_max =  1.4175
0s        624.9mV    609.4mV    653.2mV
11.86ps   624.8mV    609.3mV    665.2mV
40.03ps   624.3mV    609.3mV    778.4mV
129.3ps   636.3mV    609.3mV    1.295V
178ps     769.6mV    609.4mV    1.389V
327.8ps   1.26V      608.4mV    1.414V
372.6ps   1.324V     609.6mV    1.415V
558.4ps   1.347V     905.8mV    1.417V
807.1ps   1.349V     1.244V     1.417V
1.053ns   1.35V      1.282V     1.417V
[Rising Waveform]
R_fixture =  50
V_fixture =  0
V_fixture_min =  0
V_fixture_max =  0
2.737ps   0V         0V         0V
42.6ps    0V         0V         120.3mV
133.5ps   9.957mV    0V         652.4mV
181.3ps   138.1mV    0V         747.2mV
333.6ps   640.8mV    0V         772.5mV
376ps     705.6mV    -3.334mV   773.4mV
574.8ps   730.4mV    295.8mV    775.1mV
637.6ps   731.1mV    348.2mV    775.3mV
822.1ps   732.2mV    643.9mV    775.6mV
1.055ns   733mV      684.9mV    775.7mV
[Falling Waveform]
R_fixture =  50
V_fixture =  1.35
V_fixture_min =  1.2825
V_fixture_max =  1.4175
0s        1.35V      1.282V     1.417V
23.06ps   1.35V      1.283V     1.404V
49.72ps   1.35V      1.283V     1.303V
142ps     1.348V     1.283V     773.4mV
192.3ps   1.228V     1.282V     680.7mV
348.7ps   722.6mV    1.282V     656.2mV
393.4ps   653.7mV    1.284V     655.2mV
451.2ps   634mV      1.266V     654.4mV
857.7ps   625.8mV    656.4mV    652.6mV
1.053ns   624.9mV    609.4mV    652.5mV
[Falling Waveform]
R_fixture =  50
V_fixture =  0
V_fixture_min =  0
V_fixture_max =  0
2.737ps   733mV      684.9mV    774.8mV
21.1ps    733.1mV    685mV      758.2mV
46.79ps   733.2mV    685mV      653.2mV
136.9ps   731.2mV    685mV      126.3mV
187.1ps   606mV      684.9mV    28.84mV
344.5ps   93.55mV    684.8mV    3.117mV
387.3ps   28.56mV    685.3mV    2.142mV
439.6ps   9.697mV    667.4mV    0V
847ps     0V         42.05mV    0V
1.055ns   0V         0V         0V
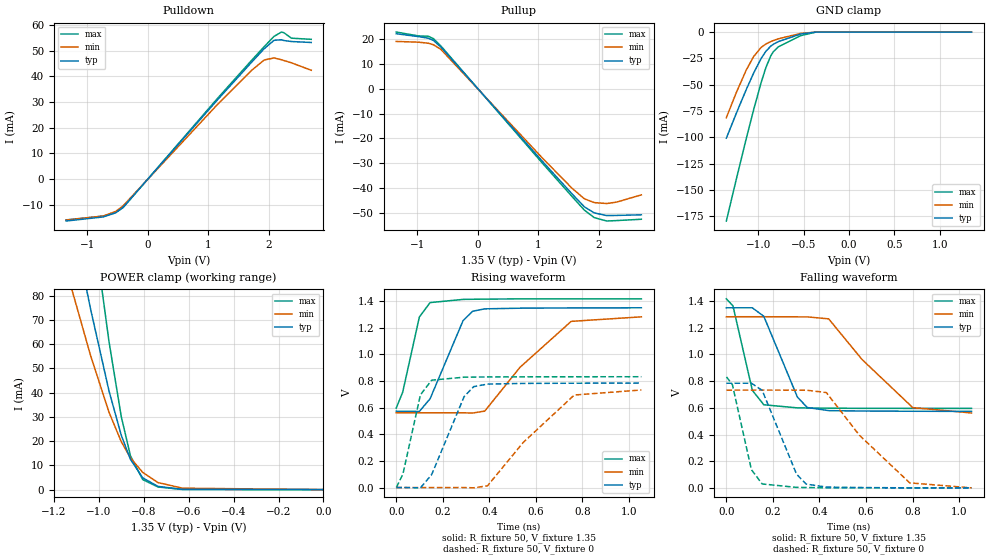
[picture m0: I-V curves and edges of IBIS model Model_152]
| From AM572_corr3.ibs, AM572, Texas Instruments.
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| Model based on original model for DDR_SEIOPB_H
|   Sub model SR011_DRV34_1P35
[model]   Model_152
|[Description]  [1.35V-I/O-X-X]
|   , ,
|[Input Load]
|[Output Drive]
|Voltage   1.35V
|Mode   I/O
Model_type   I/O
Polarity   Non-Inverting
Enable   Active-Low
Vinl =   0.585
Vinh =   0.765
Cref =   15.0000pF
Rref =   100.0000M
Vref =   0V
Vmeas =   0.675
C_comp   2p   2p   2p
[Model Spec]
Vinl   0.585   0.55125   0.61875
Vinh   0.765   0.73125   0.79875
[Receiver Thresholds]
Tslew_ac =  5n
Vth =  0.675
Vth_max =  0.709
Vth_min =  0.608
Vinh_ac =  0.175
Vinh_dc =  0.1
Vinl_ac =  -0.175
Vinl_dc =  -0.1
[Temperature Range]   25   125   -40
[Voltage Range]   1.35   1.2825   1.4175
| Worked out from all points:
|   slope of the pulldown table from 0 to 0.203 V, typ, clamps not added: 36.8 ohm
|   slope of the pullup table from 0 to 0.203 V, typ, clamps not added: 36 ohm
|   GND clamp passes 1 mA (typ) near -0.48 V on its own axis
|   POWER clamp passes 1 mA (typ) near -0.72 V on its own axis
|   rising waveform, R_fixture 50, V_fixture 1.35: 20-80 % time 112ps typ, 264ps min, 61.3ps max; typ from 0.573 V to 1.35 V
|   rising waveform, R_fixture 50, V_fixture 0: 20-80 % time 110ps typ, 257ps min, 61.5ps max; typ from 0 V to 0.784 V
|   falling waveform, R_fixture 50, V_fixture 1.35: 20-80 % time 110ps typ, 244ps min, 62.6ps max; typ from 1.35 V to 0.573 V
|   falling waveform, R_fixture 50, V_fixture 0: 20-80 % time 111ps typ, 250ps min, 62.3ps max; typ from 0.784 V to 0 V
[POWER_clamp]
-1.35V    224.4mA    165.8mA    358.5mA
-1.214V   157mA      115.5mA    250.8mA
-1.132V   117.8mA    86.59mA    187.7mA
-1.118V   111.4mA    81.92mA    177.3mA
-1.036V   74.26mA    55.16mA    116.8mA
-954.5mV  40.7mA     31.91mA    61.06mA
-900mV    22.42mA    19.79mA    30.14mA
-859.1mV  12.48mA    13.09mA    13.96mA
-804.5mV  4.85mA     7.084mA    4.132mA
-736.4mV  1.313mA    2.9mA      1.073mA
-627.3mV  101.6uA    577.3uA    45.9uA
0V        75.63nA    322.4nA    418.5nA
[Pulldown]
-1.35V    -16.25mA   -15.93mA   -15.81mA
-736.4mV  -14.67mA   -14.31mA   -14.33mA
-531.8mV  -13.09mA   -12.54mA   -12.91mA
-409.1mV  -10.94mA   -10.36mA   -11.07mA
1.145V    30.69mA    28.89mA    31.23mA
1.718V    45.54mA    42.37mA    46.27mA
1.923V    50.72mA    46.33mA    51.51mA
2.086V    53.98mA    47.12mA    55.52mA
2.209V    54.19mA    46.41mA    57.19mA
2.25V     53.89mA    46.1mA     56.9mA
2.373V    53.5mA     45.23mA    54.8mA
2.7V      53.13mA    42.33mA    54.36mA
[Pullup]
-1.35V    22.33mA    19.2mA     23.01mA
-981.8mV  21.15mA    18.91mA    21.43mA
-818.2mV  20.5mA     18.48mA    21.31mA
-736.4mV  19.62mA    17.88mA    20.36mA
-613.6mV  16.97mA    16.06mA    17.42mA
1.064V    -29.25mA   -27.93mA   -29.99mA
1.555V    -42.46mA   -40.17mA   -43.52mA
1.759V    -47.7mA    -44.45mA   -49.03mA
1.923V    -50.14mA   -45.98mA   -52.07mA
2.127V    -51.21mA   -46.35mA   -53.42mA
2.291V    -51.16mA   -45.77mA   -53.24mA
2.7V      -50.91mA   -42.85mA   -52.71mA
[GND_clamp]
-1.35V    -100.7mA   -81.27mA   -179.3mA
-1.241V   -77.31mA   -57.61mA   -140mA
-1.132V   -54.83mA   -36.31mA   -101.6mA
-1.05V    -39.08mA   -23.36mA   -74mA
-968.2mV  -25.28mA   -14.71mA   -48.34mA
-913.6mV  -18.13mA   -11.32mA   -33.52mA
-859.1mV  -13.28mA   -9.024mA   -22.35mA
-831.8mV  -11.61mA   -8.091mA   -18.64mA
-777.3mV  -9.078mA   -6.444mA   -14.07mA
-531.8mV  -1.871mA   -1.307mA   -3.441mA
-368.2mV  -88.76uA   -111.2uA   -158uA
1.35V     75.63nA    385.5nA    349.4nA
[Ramp]
dV/dt_f 0.46672115/0.11007541n 0.43377401/0.24462721n 0.49354383/62.641404p
dV/dt_r 0.47300492/0.11067813n 0.44212263/0.2589168n 0.50141977/61.686788p
R_load =  50
[Rising Waveform]
R_fixture =  50
V_fixture =  1.35
V_fixture_min =  1.2825
V_fixture_max =  1.4175
0s        573.3mV    561.4mV    596.7mV
27.72ps   572.5mV    561.3mV    715.2mV
99.5ps    571.6mV    561.3mV    1.281V
145.6ps   667mV      561.3mV    1.389V
287ps     1.253V     561.3mV    1.413V
328ps     1.324V     559.5mV    1.414V
380.2ps   1.342V     573.9mV    1.415V
532.1ps   1.347V     903.7mV    1.417V
751.5ps   1.349V     1.248V     1.417V
1.053ns   1.35V      1.282V     1.417V
[Rising Waveform]
R_fixture =  50
V_fixture =  0
V_fixture_min =  0
V_fixture_max =  0
545.6fs   0V         0V         0V
28.9ps    0V         0V         101.1mV
104ps     -2.399mV   0V         696.6mV
152.4ps   97.06mV    0V         806.3mV
291.7ps   683mV      0V         828.8mV
332.7ps   757.7mV    -2.182mV   829.6mV
392.2ps   777.1mV    12.89mV    830.5mV
545ps     781.9mV    337.3mV    831.5mV
764.8ps   783.5mV    694.8mV    832mV
1.053ns   784.4mV    732.7mV    832.1mV
[Falling Waveform]
R_fixture =  50
V_fixture =  1.35
V_fixture_min =  1.2825
V_fixture_max =  1.4175
0s        1.35V      1.282V     1.417V
28.39ps   1.35V      1.283V     1.365V
111.7ps   1.35V      1.283V     731.1mV
161.1ps   1.286V     1.283V     622.9mV
305.1ps   681.2mV    1.282V     599.7mV
347.6ps   602.2mV    1.282V     598.7mV
439.6ps   579.1mV    1.267V     597.3mV
582.8ps   576mV      962.5mV    596.3mV
800.8ps   574.3mV    601.5mV    595.8mV
1.053ns   573.3mV    561.4mV    595.7mV
[Falling Waveform]
R_fixture =  50
V_fixture =  0
V_fixture_min =  0
V_fixture_max =  0
545.6fs   784.4mV    732.7mV    832.1mV
26ps      784.6mV    732.7mV    773.8mV
107.7ps   784.3mV    732.8mV    136.2mV
154.1ps   730.7mV    732.8mV    29.11mV
301.4ps   103.2mV    732.6mV    3.484mV
342.5ps   28.23mV    732.6mV    2.451mV
429.5ps   5.832mV    714.4mV    0V
571.6ps   2.449mV    394.2mV    0V
787.7ps   0V         37.36mV    0V
1.053ns   0V         0V         0V
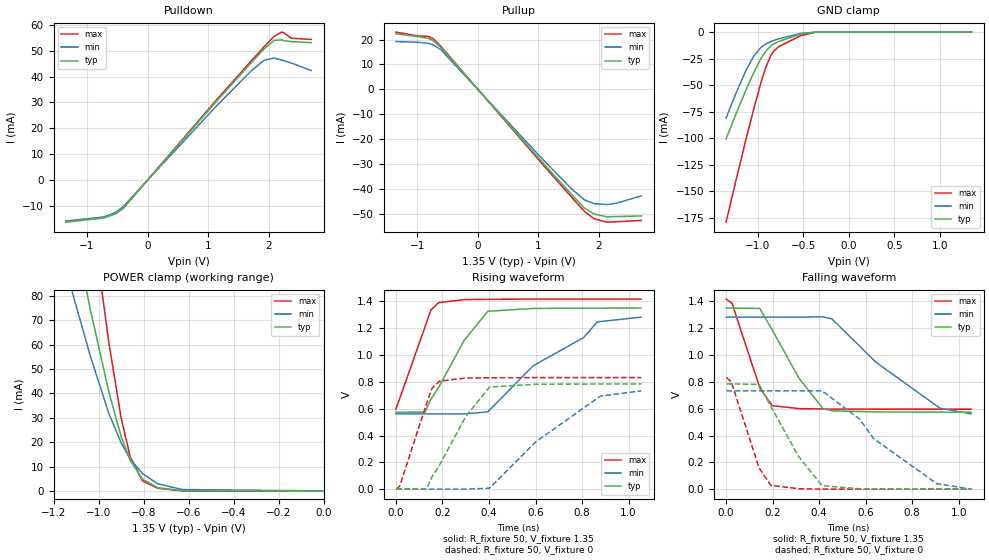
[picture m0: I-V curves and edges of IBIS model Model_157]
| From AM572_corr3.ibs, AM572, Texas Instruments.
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| Model based on original model for DDR_SEIOPB_H
|   Sub model SR111_DRV34_1P35
[model]   Model_157
|[Description]  [1.35V-I/O-X-X]
|   , ,
|[Input Load]
|[Output Drive]
|Voltage   1.35V
|Mode   I/O
Model_type   I/O
Polarity   Non-Inverting
Enable   Active-Low
Vinl =   0.585
Vinh =   0.765
Cref =   15.0000pF
Rref =   100.0000M
Vref =   0V
Vmeas =   0.675
C_comp   2p   2p   2p
[Model Spec]
Vinl   0.585   0.55125   0.61875
Vinh   0.765   0.73125   0.79875
[Receiver Thresholds]
Tslew_ac =  5n
Vth =  0.675
Vth_max =  0.709
Vth_min =  0.608
Vinh_ac =  0.175
Vinh_dc =  0.1
Vinl_ac =  -0.175
Vinl_dc =  -0.1
[Temperature Range]   25   125   -40
[Voltage Range]   1.35   1.2825   1.4175
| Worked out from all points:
|   slope of the pulldown table from 0 to 0.203 V, typ, clamps not added: 36.8 ohm
|   slope of the pullup table from 0 to 0.203 V, typ, clamps not added: 36 ohm
|   GND clamp passes 1 mA (typ) near -0.48 V on its own axis
|   POWER clamp passes 1 mA (typ) near -0.72 V on its own axis
|   rising waveform, R_fixture 50, V_fixture 1.35: 20-80 % time 172ps typ, 365ps min, 93.5ps max; typ from 0.573 V to 1.35 V
|   rising waveform, R_fixture 50, V_fixture 0: 20-80 % time 169ps typ, 359ps min, 92.2ps max; typ from 0 V to 0.784 V
|   falling waveform, R_fixture 50, V_fixture 1.35: 20-80 % time 166ps typ, 346ps min, 92.5ps max; typ from 1.35 V to 0.573 V
|   falling waveform, R_fixture 50, V_fixture 0: 20-80 % time 169ps typ, 352ps min, 93ps max; typ from 0.784 V to 0 V
[POWER_clamp]
-1.35V    224.4mA    165.8mA    358.5mA
-1.214V   157mA      115.5mA    250.8mA
-1.132V   117.8mA    86.59mA    187.7mA
-1.118V   111.4mA    81.92mA    177.3mA
-1.036V   74.26mA    55.16mA    116.8mA
-954.5mV  40.7mA     31.91mA    61.06mA
-900mV    22.42mA    19.79mA    30.14mA
-859.1mV  12.48mA    13.09mA    13.96mA
-804.5mV  4.85mA     7.084mA    4.132mA
-736.4mV  1.313mA    2.9mA      1.073mA
-627.3mV  101.6uA    577.3uA    45.9uA
0V        75.63nA    322.4nA    418.5nA
[Pulldown]
-1.35V    -16.25mA   -15.93mA   -15.81mA
-736.4mV  -14.67mA   -14.31mA   -14.33mA
-531.8mV  -13.09mA   -12.54mA   -12.91mA
-409.1mV  -10.94mA   -10.36mA   -11.07mA
1.145V    30.69mA    28.89mA    31.23mA
1.718V    45.54mA    42.37mA    46.27mA
1.923V    50.72mA    46.33mA    51.51mA
2.086V    53.98mA    47.12mA    55.52mA
2.209V    54.19mA    46.41mA    57.19mA
2.25V     53.89mA    46.1mA     56.9mA
2.373V    53.5mA     45.23mA    54.8mA
2.7V      53.13mA    42.33mA    54.36mA
[Pullup]
-1.35V    22.33mA    19.2mA     23.01mA
-981.8mV  21.15mA    18.91mA    21.43mA
-818.2mV  20.5mA     18.48mA    21.31mA
-736.4mV  19.62mA    17.88mA    20.36mA
-613.6mV  16.97mA    16.06mA    17.42mA
1.064V    -29.25mA   -27.93mA   -29.99mA
1.555V    -42.46mA   -40.17mA   -43.52mA
1.759V    -47.7mA    -44.45mA   -49.03mA
1.923V    -50.14mA   -45.98mA   -52.07mA
2.127V    -51.21mA   -46.35mA   -53.42mA
2.291V    -51.16mA   -45.77mA   -53.24mA
2.7V      -50.91mA   -42.85mA   -52.71mA
[GND_clamp]
-1.35V    -100.7mA   -81.27mA   -179.3mA
-1.241V   -77.31mA   -57.61mA   -140mA
-1.132V   -54.83mA   -36.31mA   -101.6mA
-1.05V    -39.08mA   -23.36mA   -74mA
-968.2mV  -25.28mA   -14.71mA   -48.34mA
-913.6mV  -18.13mA   -11.32mA   -33.52mA
-859.1mV  -13.28mA   -9.024mA   -22.35mA
-831.8mV  -11.61mA   -8.091mA   -18.64mA
-777.3mV  -9.078mA   -6.444mA   -14.07mA
-531.8mV  -1.871mA   -1.307mA   -3.441mA
-368.2mV  -88.76uA   -111.2uA   -158uA
1.35V     75.63nA    385.5nA    349.4nA
[Ramp]
dV/dt_f 0.46691983/0.16666767n 0.43398012/0.34713634n 0.49366203/92.612673p
dV/dt_r 0.47297721/0.17035039n 0.44240153/0.36100759n 0.50126717/92.733963p
R_load =  50
[Rising Waveform]
R_fixture =  50
V_fixture =  1.35
V_fixture_min =  1.2825
V_fixture_max =  1.4175
0s        573.3mV    561.4mV    596.5mV
125.6ps   574.8mV    561.3mV    1.212V
150.2ps   670.1mV    561.3mV    1.335V
183.6ps   757.8mV    561.4mV    1.39V
293.6ps   1.11V      561.2mV    1.413V
395.3ps   1.326V     576.1mV    1.415V
589.2ps   1.347V     919.3mV    1.417V
806.9ps   1.349V     1.13V      1.417V
865.8ps   1.349V     1.247V     1.417V
1.053ns   1.35V      1.282V     1.417V
[Rising Waveform]
R_fixture =  50
V_fixture =  0
V_fixture_min =  0
V_fixture_max =  0
2.047ps   0V         0V         0V
16.53ps   0V         0V         24.55mV
130.9ps   0V         0V         633.4mV
154.9ps   92.09mV    0V         751.2mV
187.4ps   179mV      0V         805.3mV
298.7ps   537.9mV    0V         828.2mV
402.1ps   760.9mV    7.129mV    830.3mV
603.2ps   782.1mV    355.8mV    831.7mV
879.5ps   783.7mV    694.2mV    832.1mV
1.055ns   784.4mV    732.7mV    832.1mV
[Falling Waveform]
R_fixture =  50
V_fixture =  1.35
V_fixture_min =  1.2825
V_fixture_max =  1.4175
0s        1.35V      1.282V     1.417V
25.54ps   1.35V      1.283V     1.386V
145.2ps   1.347V     1.283V     755.1mV
197.8ps   1.189V     1.282V     622.8mV
314.6ps   823.9mV    1.282V     600.2mV
417.4ps   600mV      1.285V     597.9mV
455.3ps   584.1mV    1.269V     597.4mV
644.3ps   575.8mV    946.2mV    596.2mV
918.8ps   574mV      604.5mV    595.8mV
1.053ns   573.3mV    561.4mV    595.7mV
[Falling Waveform]
R_fixture =  50
V_fixture =  0
V_fixture_min =  0
V_fixture_max =  0
2.047ps   784.4mV    732.7mV    832.1mV
22.57ps   784.5mV    732.7mV    799.4mV
141.9ps   780.5mV    732.8mV    158.6mV
192.6ps   617.1mV    732.7mV    27.77mV
311.1ps   245.8mV    732.6mV    4.011mV
412.4ps   26.14mV    732.8mV    0V
574.1ps   3.055mV    522.4mV    0V
634.2ps   2.212mV    377.1mV    0V
905.2ps   0V         41.56mV    0V
1.055ns   0V         0V         0V
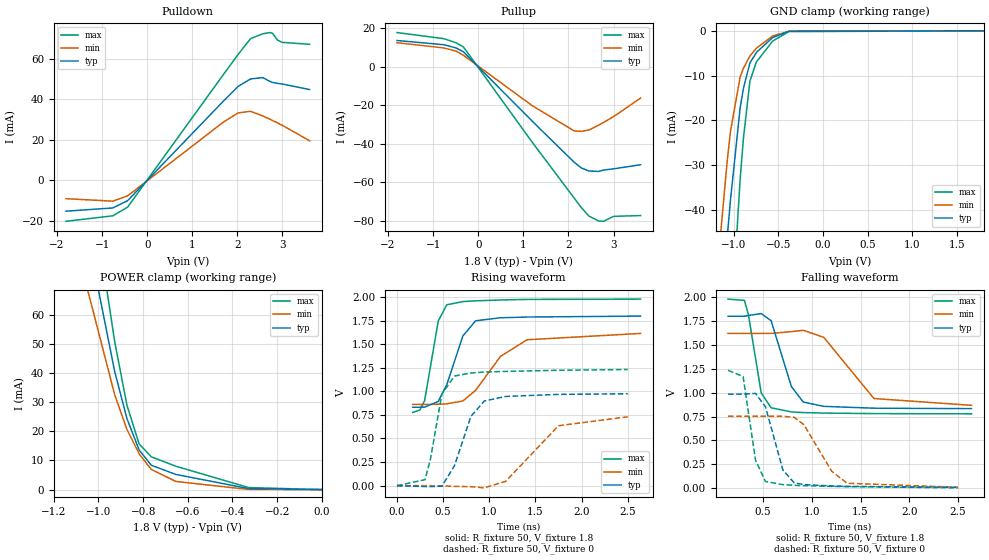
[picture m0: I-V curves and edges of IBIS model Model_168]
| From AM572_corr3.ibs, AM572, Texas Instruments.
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| Model based on original model for BC1833DV40DCPBFBP1811_SSCEH
|   Sub model BC40D_H_10P_!SC1_1P8
[model]   Model_168
|[Description]  [1.8V-I/O-X-40D CLASS MODE FAST MODE, IND, 10 PERCENT%]
|   40D CLASS MODE FAST MODE, ,IND,10 PERCENT%
|[Input Load]
|[Output Drive] 40D CLASS MODE FAST MODE
|Voltage   1.8V
|Mode   I/O
Model_type   I/O
Polarity   Non-Inverting
Enable   Active-Low
Vinl =   0.63
Vinh =   1.17
Cref =   15pF
Rref =   100.0000M
Vref =   0V
Vmeas =   0.9
C_comp   2.29p   1.81p   2.77p
[Model Spec]
Vinl   0.63   0.567   0.693
Vinh   1.17   1.053   1.287
D_overshoot_ampl_h 0.36 0.36 0.36
D_overshoot_ampl_l 0.36 0.36 0.36
D_overshoot_area_h 0.33n 0.33n 0.33n
D_overshoot_area_l 0.33n 0.33n 0.33n
D_overshoot_high 2.16 2.16 2.16
D_overshoot_low -0.36 -0.36 -0.36
D_overshoot_time 1n 1n 1n
S_overshoot_high 1.8 1.8 1.8
S_overshoot_low 0 0 0
[Temperature Range]   25   125   -40
[Voltage Range]   1.8   1.62   1.98
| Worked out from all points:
|   slope of the pulldown table from 0 to 0.27 V, typ, clamps not added: 42.1 ohm
|   slope of the pullup table from 0 to 0.27 V, typ, clamps not added: 41.1 ohm
|   GND clamp passes 1 mA (typ) near -0.52 V on its own axis
|   POWER clamp passes 1 mA (typ) near -0.39 V on its own axis
|   rising waveform, R_fixture 50, V_fixture 1.8: 20-80 % time 200ps typ, 395ps min, 119ps max; typ from 0.832 V to 1.8 V
|   rising waveform, R_fixture 50, V_fixture 0: 20-80 % time 207ps typ, 379ps min, 135ps max; typ from -0.001 V to 0.975 V
|   falling waveform, R_fixture 50, V_fixture 1.8: 20-80 % time 171ps typ, 314ps min, 113ps max; typ from 1.8 V to 0.833 V
|   falling waveform, R_fixture 50, V_fixture 0: 20-80 % time 157ps typ, 265ps min, 101ps max; typ from 0.985 V to 0.01 V
[POWER_clamp]
-1.8V     435.3mA    358.7mA    550.4mA
-1.182V   145.1mA    115.2mA    186mA
-1.164V   136.9mA    108.6mA    175.7mA
-1.109V   112.9mA    89.04mA    145.1mA
-1.055V   89.59mA    70.35mA    115.1mA
-927.3mV  40.44mA    32.49mA    50.68mA
-872.7mV  24.38mA    20.69mA    29mA
-818.2mV  13.61mA    12.29mA    15.69mA
-763.6mV  8.369mA    6.955mA    11.25mA
-654.5mV  5.219mA    2.81mA     8.042mA
-327.3mV  349.6uA    49.2uA     692.7uA
0V        2.268uA    679.7nA    6.102uA
[Pulldown]
-1.8V     -15.33mA   -9.14mA    -20.33mA
-763.6mV  -13.73mA   -10.37mA   -17.62mA
-436.4mV  -10.18mA   -7.79mA    -13.39mA
1.691V    39.13mA    28.75mA    52.28mA
2.018V    46.42mA    33.29mA    62.25mA
2.291V    50.07mA    34.07mA    69.98mA
2.564V    50.73mA    31.75mA    72.43mA
2.727V    48.74mA    30.06mA    73mA
2.782V    48.33mA    29.5mA     72.56mA
2.891V    47.87mA    28.33mA    69.24mA
3V        47.56mA    27.08mA    68.14mA
3.6V      44.82mA    19.5mA     67.2mA
[Pullup]
-1.8V     13.52mA    12.37mA    17.64mA
-763.6mV  11.34mA    9.658mA    14.48mA
-490.9mV  9.653mA    8.014mA    12.35mA
-327.3mV  7.63mA     5.831mA    10.16mA
1.2V      -28.46mA   -20.36mA   -39.39mA
2.127V    -49.69mA   -33.41mA   -68.31mA
2.291V    -52.74mA   -33.68mA   -73.37mA
2.455V    -54.25mA   -32.94mA   -77.67mA
2.673V    -54.49mA   -30.44mA   -80.24mA
2.782V    -53.74mA   -28.99mA   -80.39mA
3V        -53.15mA   -26.05mA   -77.82mA
3.6V      -51.01mA   -16.37mA   -77.4mA
[GND_clamp]
-1.8V     -241.7mA   -231.6mA   -367.4mA
-1.255V   -91.62mA   -71.7mA    -149.9mA
-1.182V   -72.85mA   -53.19mA   -122mA
-1.073V   -46.19mA   -29.16mA   -81.51mA
-1.036V   -37.83mA   -22.49mA   -68.45mA
-927.3mV  -17.13mA   -10.25mA   -33.06mA
-890.9mV  -12.84mA   -8.372mA   -24.01mA
-818.2mV  -7.187mA   -5.618mA   -11.22mA
-745.5mV  -4.828mA   -3.892mA   -6.943mA
-563.6mV  -1.493mA   -1.146mA   -2.288mA
-381.8mV  -98.54uA   -88.38uA   -167.6uA
1.8V      2.268uA    1.69uA     5.679uA
[Ramp]
dV/dt_f   0.598188/0.1761616n   0.47937/0.33312052n   0.734418/0.11520802n
dV/dt_r  0.5998296/0.21395821n   0.467568/0.41234441n   0.747435/0.13680708n
R_load =  50
[Rising Waveform]
R_fixture =  50
V_fixture =  1.8
V_fixture_min =  1.62
V_fixture_max =  1.98
170.3ps   831.8mV    861.1mV    776.7mV
248.9ps   831.8mV    861.1mV    803.1mV
299.3ps   832.5mV    861.1mV    902.7mV
447.1ps   893.2mV    863.2mV    1.747V
539.2ps   1.071V     867.5mV    1.919V
713.2ps   1.587V     898mV      1.953V
850.9ps   1.749V     1.01V      1.961V
1.121ns   1.781V     1.371V     1.97V
1.41ns    1.789V     1.548V     1.976V
2.639ns   1.799V     1.615V     1.979V
[Rising Waveform]
R_fixture =  50
V_fixture =  0
V_fixture_min =  0
V_fixture_max =  0
0s        -803.9uV   -555.5uV   -671.6uV
303.6ps   -10.07mV   -555.5uV   62.82mV
362.4ps   -10.43mV   -781.2uV   279.7mV
486ps     -6.689mV   -2.602mV   970.8mV
623.1ps   211.6mV    -8.259mV   1.163V
800.8ps   734.6mV    -11.44mV   1.195V
945.6ps   897.6mV    -24.07mV   1.205V
1.177ns   946.2mV    44.99mV    1.212V
1.75ns    968.1mV    635.4mV    1.224V
2.5ns     974.5mV    730.1mV    1.232V
[Falling Waveform]
R_fixture =  50
V_fixture =  1.8
V_fixture_min =  1.62
V_fixture_max =  1.98
139.5ps   1.8V       1.62V      1.979V
307.8ps   1.8V       1.62V      1.966V
349ps     1.808V     1.62V      1.816V
480ps     1.828V     1.62V      997.6mV
581.9ps   1.753V     1.62V      841.5mV
790ps     1.064V     1.639V     798.6mV
912.8ps   901.3mV    1.653V     791.6mV
1.123ns   856.5mV    1.578V     786.1mV
1.637ns   837.5mV    938.7mV    780.9mV
2.639ns   832.7mV    867.3mV    778.5mV
[Falling Waveform]
R_fixture =  50
V_fixture =  0
V_fixture_min =  0
V_fixture_max =  0
139.7ps   985mV      752.9mV    1.234V
294.4ps   985mV      752.9mV    1.169V
421.8ps   992.4mV    752.9mV    292.8mV
524ps     851.6mV    752.9mV    70.23mV
702.8ps   190.8mV    752.9mV    37.24mV
818.7ps   56.37mV    742.1mV    30.3mV
918.4ps   37.43mV    664.7mV    26.37mV
1.203ns   23.29mV    178.3mV    19.25mV
1.361ns   18.77mV    51.75mV    16.84mV
2.5ns     9.698mV    9.733mV    3.625mV
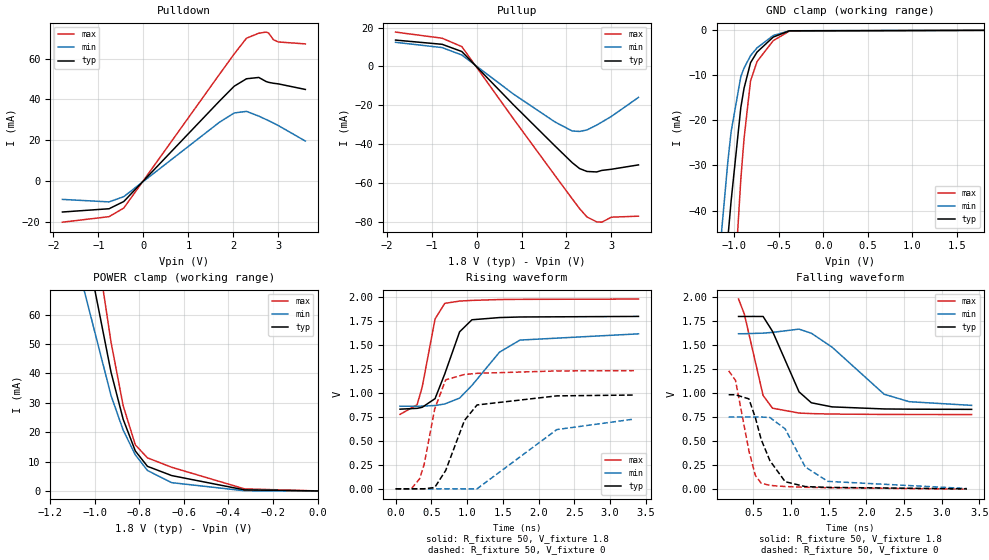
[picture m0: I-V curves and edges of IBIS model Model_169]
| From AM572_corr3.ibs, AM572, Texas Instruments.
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| Model based on original model for BC1833DV40DCPBFBP1811_SSCEH
|   Sub model BC40D_H_10P_SC1_1P8
[model]   Model_169
|[Description]  [1.8V-I/O-X-40C CLASS MODE SLOW MODE, IND, 10 PERCENT%]
|   40C CLASS MODE SLOW MODE, ,IND,10 PERCENT%
|[Input Load]
|[Output Drive] 40C CLASS MODE SLOW MODE
|Voltage   1.8V
|Mode   I/O
Model_type   I/O
Polarity   Non-Inverting
Enable   Active-Low
Vinl =   0.63
Vinh =   1.17
Cref =   15pF
Rref =   100.0000M
Vref =   0V
Vmeas =   0.9
C_comp   2.29p   1.81p   2.77p
[Model Spec]
Vinl   0.63   0.567   0.693
Vinh   1.17   1.053   1.287
D_overshoot_ampl_h 0.36 0.36 0.36
D_overshoot_ampl_l 0.36 0.36 0.36
D_overshoot_area_h 0.33n 0.33n 0.33n
D_overshoot_area_l 0.33n 0.33n 0.33n
D_overshoot_high 2.16 2.16 2.16
D_overshoot_low -0.36 -0.36 -0.36
D_overshoot_time 1n 1n 1n
S_overshoot_high 1.8 1.8 1.8
S_overshoot_low 0 0 0
[Temperature Range]   25   125   -40
[Voltage Range]   1.8   1.62   1.98
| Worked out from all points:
|   slope of the pulldown table from 0 to 0.27 V, typ, clamps not added: 42.1 ohm
|   slope of the pullup table from 0 to 0.27 V, typ, clamps not added: 41.1 ohm
|   GND clamp passes 1 mA (typ) near -0.52 V on its own axis
|   POWER clamp passes 1 mA (typ) near -0.39 V on its own axis
|   rising waveform, R_fixture 50, V_fixture 1.8: 20-80 % time 272ps typ, 525ps min, 182ps max; typ from 0.831 V to 1.8 V
|   rising waveform, R_fixture 50, V_fixture 0: 20-80 % time 316ps typ, 681ps min, 204ps max; typ from 0 V to 0.979 V
|   falling waveform, R_fixture 50, V_fixture 1.8: 20-80 % time 321ps typ, 619ps min, 206ps max; typ from 1.8 V to 0.832 V
|   falling waveform, R_fixture 50, V_fixture 0: 20-80 % time 285ps typ, 355ps min, 186ps max; typ from 0.985 V to 0.004 V
[POWER_clamp]
-1.8V     435.3mA    358.7mA    550.4mA
-1.182V   145.1mA    115.2mA    186mA
-1.164V   136.9mA    108.6mA    175.7mA
-1.109V   112.9mA    89.04mA    145.1mA
-1.055V   89.59mA    70.35mA    115.1mA
-927.3mV  40.44mA    32.49mA    50.68mA
-872.7mV  24.38mA    20.69mA    29mA
-818.2mV  13.61mA    12.29mA    15.69mA
-763.6mV  8.369mA    6.955mA    11.25mA
-654.5mV  5.219mA    2.81mA     8.042mA
-327.3mV  349.6uA    49.2uA     692.6uA
0V        2.268uA    677.1nA    6.102uA
[Pulldown]
-1.8V     -15.33mA   -9.14mA    -20.33mA
-763.6mV  -13.73mA   -10.37mA   -17.62mA
-436.4mV  -10.18mA   -7.79mA    -13.39mA
1.691V    39.13mA    28.75mA    52.28mA
2.018V    46.42mA    33.29mA    62.25mA
2.291V    50.08mA    34.08mA    69.99mA
2.564V    50.73mA    31.76mA    72.44mA
2.727V    48.74mA    30.08mA    73mA
2.782V    48.34mA    29.52mA    72.57mA
2.891V    47.88mA    28.34mA    69.24mA
3V        47.57mA    27.1mA     68.15mA
3.6V      44.84mA    19.51mA    67.21mA
[Pullup]
-1.8V     13.52mA    12.37mA    17.64mA
-763.6mV  11.34mA    9.658mA    14.48mA
-327.3mV  7.63mA     5.831mA    10.16mA
818.2mV   -19.75mA   -14.25mA   -26.96mA
1.745V    -41.04mA   -28.68mA   -56.27mA
2.127V    -49.63mA   -33.31mA   -68.26mA
2.291V    -52.67mA   -33.55mA   -73.31mA
2.455V    -54.17mA   -32.78mA   -77.6mA
2.673V    -54.4mA    -30.24mA   -80.15mA
2.782V    -53.64mA   -28.77mA   -80.3mA
3V        -53.02mA   -25.78mA   -77.71mA
3.6V      -50.78mA   -16mA      -77.2mA
[GND_clamp]
-1.8V     -241.7mA   -231.6mA   -367.4mA
-1.255V   -91.62mA   -71.7mA    -149.9mA
-1.182V   -72.85mA   -53.19mA   -122mA
-1.073V   -46.19mA   -29.16mA   -81.51mA
-1.036V   -37.83mA   -22.49mA   -68.45mA
-927.3mV  -17.13mA   -10.25mA   -33.06mA
-890.9mV  -12.84mA   -8.372mA   -24.01mA
-818.2mV  -7.187mA   -5.618mA   -11.22mA
-745.5mV  -4.828mA   -3.892mA   -6.943mA
-563.6mV  -1.493mA   -1.146mA   -2.288mA
-381.8mV  -98.54uA   -88.38uA   -167.6uA
1.8V      2.268uA    1.69uA     5.679uA
[Ramp]
dV/dt_f   0.60786/0.33658904n   0.485022/0.67689754n   0.734136/0.21016618n
dV/dt_r 0.59655024/0.32255753n  0.4585296/0.72528553n 0.74531052/0.20572598n
R_load =  50
[Rising Waveform]
R_fixture =  50
V_fixture =  1.8
V_fixture_min =  1.62
V_fixture_max =  1.98
62.4ps    831.2mV    861.7mV    776.7mV
301.9ps   839.8mV    861.7mV    878mV
372.6ps   850.7mV    863mV      1.062V
552.3ps   941.1mV    869.2mV    1.772V
687.5ps   1.198V     885.4mV    1.935V
895.3ps   1.638V     946.8mV    1.959V
1.068ns   1.764V     1.079V     1.966V
1.453ns   1.787V     1.426V     1.975V
1.739ns   1.793V     1.552V     1.977V
3.396ns   1.799V     1.617V     1.98V
[Rising Waveform]
R_fixture =  50
V_fixture =  0
V_fixture_min =  0
V_fixture_max =  0
0s        211.6uV    170.7uV    -794.3uV
215.9ps   211.6uV    170.7uV    -3.557mV
336.3ps   211.6uV    170.7uV    104.8mV
399.4ps   211.6uV    170.7uV    252.5mV
547.5ps   13.93mV    170.7uV    834.2mV
700.2ps   190.7mV    170.7uV    1.137V
963.7ps   714.1mV    170.7uV    1.193V
1.139ns   875mV      170.7uV    1.205V
2.255ns   969.9mV    618.4mV    1.23V
3.333ns   978.6mV    727.5mV    1.233V
[Falling Waveform]
R_fixture =  50
V_fixture =  1.8
V_fixture_min =  1.62
V_fixture_max =  1.98
304ps     1.8V       1.62V      1.981V
380.2ps   1.8V       1.62V      1.826V
629.3ps   1.8V       1.626V     977.4mV
754.4ps   1.645V     1.634V     844.3mV
1.106ns   1.015V     1.668V     793.7mV
1.27ns    900.6mV    1.625V     788mV
1.545ns   858mV      1.48V      783.2mV
2.236ns   836.4mV    989.5mV    779.2mV
2.57ns    834.2mV    911.8mV    778.7mV
3.396ns   832.1mV    873.7mV    778.1mV
[Falling Waveform]
R_fixture =  50
V_fixture =  0
V_fixture_min =  0
V_fixture_max =  0
172.8ps   984.5mV    752.2mV    1.234V
263.8ps   984.5mV    752.2mV    1.133V
441ps     941.3mV    752.2mV    401.5mV
527.9ps   742.6mV    752.2mV    142.2mV
604ps     518.6mV    752.2mV    63.48mV
719.9ps   297.6mV    747.4mV    39.92mV
922.4ps   78.78mV    628.8mV    28.37mV
1.189ns   27.81mV    232.3mV    20.65mV
1.489ns   19.62mV    81.99mV    15.83mV
3.333ns   4.016mV    7.702mV    914.8uV
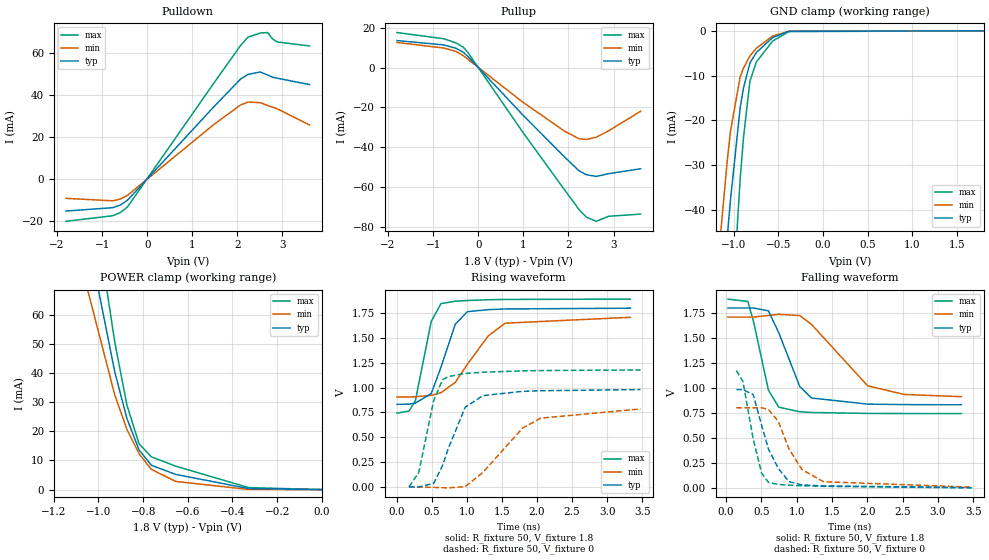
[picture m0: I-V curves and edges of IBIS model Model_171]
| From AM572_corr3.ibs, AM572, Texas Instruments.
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| Model based on original model for BC1833DV40DCPBFBP1811_SSCEH
|   Sub model BC40D_H_5P_SC1_1P8
[model]   Model_171
|[Description]  [1.8V-I/O-X-40C CLASS MODE SLOW MODE, IND, 5 PERCENT%]
|   40C CLASS MODE SLOW MODE, ,IND,5 PERCENT%
|[Input Load]
|[Output Drive] 40C CLASS MODE SLOW MODE
|Voltage   1.8V
|Mode   I/O
Model_type   I/O
Polarity   Non-Inverting
Enable   Active-Low
Vinl =   0.63
Vinh =   1.17
Cref =   15pF
Rref =   100.0000M
Vref =   0V
Vmeas =   0.9
C_comp   2.29p   1.81p   2.77p
[Model Spec]
Vinl   0.63   0.5985   0.6615
Vinh   1.17   1.1115   1.2285
D_overshoot_ampl_h 0.36 0.36 0.36
D_overshoot_ampl_l 0.36 0.36 0.36
D_overshoot_area_h 0.33n 0.33n 0.33n
D_overshoot_area_l 0.33n 0.33n 0.33n
D_overshoot_high 2.16 2.16 2.16
D_overshoot_low -0.36 -0.36 -0.36
D_overshoot_time 1n 1n 1n
S_overshoot_high 1.8 1.8 1.8
S_overshoot_low 0 0 0
[Temperature Range]   25   125   -40
[Voltage Range]   1.8   1.71   1.89
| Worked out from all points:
|   slope of the pulldown table from 0 to 0.27 V, typ, clamps not added: 42.1 ohm
|   slope of the pullup table from 0 to 0.27 V, typ, clamps not added: 41.1 ohm
|   GND clamp passes 1 mA (typ) near -0.52 V on its own axis
|   POWER clamp passes 1 mA (typ) near -0.39 V on its own axis
|   rising waveform, R_fixture 50, V_fixture 1.8: 20-80 % time 272ps typ, 495ps min, 183ps max; typ from 0.831 V to 1.8 V
|   rising waveform, R_fixture 50, V_fixture 0: 20-80 % time 317ps typ, 645ps min, 207ps max; typ from 0 V to 0.98 V
|   falling waveform, R_fixture 50, V_fixture 1.8: 20-80 % time 321ps typ, 572ps min, 212ps max; typ from 1.8 V to 0.832 V
|   falling waveform, R_fixture 50, V_fixture 0: 20-80 % time 286ps typ, 349ps min, 196ps max; typ from 0.984 V to 0.003 V
[POWER_clamp]
-1.8V     435.3mA    358.7mA    550.4mA
-1.182V   145.1mA    115.2mA    186mA
-1.164V   136.9mA    108.6mA    175.7mA
-1.109V   112.9mA    89.05mA    145.1mA
-1.055V   89.59mA    70.36mA    115.1mA
-927.3mV  40.44mA    32.49mA    50.68mA
-872.7mV  24.38mA    20.7mA     29mA
-818.2mV  13.61mA    12.29mA    15.69mA
-763.6mV  8.369mA    6.958mA    11.24mA
-654.5mV  5.219mA    2.811mA    8.041mA
-327.3mV  349.6uA    49.45uA    691.6uA
0V        2.268uA    902.8nA    4.994uA
[Pulldown]
-1.8V     -15.33mA   -9.29mA    -20.21mA
-763.6mV  -13.73mA   -10.46mA   -17.56mA
-600mV    -12.51mA   -9.657mA   -16.14mA
-436.4mV  -10.18mA   -7.846mA   -13.35mA
1.473V    34.18mA    25.79mA    45.4mA
2.073V    47.54mA    35.2mA     63.55mA
2.236V    49.7mA     36.52mA    67.46mA
2.509V    50.85mA    36.26mA    69.4mA
2.673V    49.39mA    34.88mA    69.61mA
2.782V    48.34mA    34.07mA    66.5mA
2.891V    47.88mA    33.26mA    65.11mA
3.6V      44.84mA    25.64mA    63.24mA
[Pullup]
-1.8V     13.52mA    12.56mA    17.53mA
-763.6mV  11.34mA    9.77mA     14.43mA
-490.9mV  9.653mA    8.093mA    12.32mA
-327.3mV  7.63mA     5.886mA    10.14mA
-218.2mV  5.3mA      3.95mA     7.201mA
981.8mV   -23.64mA   -17.25mA   -32.22mA
1.909V    -44.75mA   -31.83mA   -61.2mA
2.236V    -51.82mA   -35.76mA   -71.26mA
2.4V      -53.81mA   -36.05mA   -75.08mA
2.618V    -54.62mA   -34.97mA   -77.14mA
2.891V    -53.26mA   -31.76mA   -74.62mA
3.6V      -50.78mA   -21.96mA   -73.53mA
[GND_clamp]
-1.8V     -241.7mA   -231.6mA   -367.4mA
-1.255V   -91.62mA   -71.7mA    -149.9mA
-1.182V   -72.85mA   -53.19mA   -122mA
-1.073V   -46.19mA   -29.16mA   -81.51mA
-1.036V   -37.83mA   -22.49mA   -68.45mA
-927.3mV  -17.13mA   -10.25mA   -33.06mA
-890.9mV  -12.84mA   -8.372mA   -24.01mA
-818.2mV  -7.187mA   -5.618mA   -11.22mA
-745.5mV  -4.828mA   -3.893mA   -6.943mA
-563.6mV  -1.493mA   -1.147mA   -2.288mA
-381.8mV  -98.54uA   -88.42uA   -167.6uA
1.8V      2.268uA    1.016uA    4.793uA
[Ramp]
dV/dt_f   0.60792/0.33665136n   0.513522/0.6205334n   0.701736/0.2159947n
dV/dt_r 0.59654946/0.32261461n   0.487767/0.681746n  0.71105388/0.20869963n
R_load =  50
[Rising Waveform]
R_fixture =  50
V_fixture =  1.8
V_fixture_min =  1.71
V_fixture_max =  1.89
0s        831.2mV    904.4mV    742.9mV
170.6ps   833.2mV    905.5mV    763.3mV
261.8ps   842.8mV    907.3mV    865.8mV
488.9ps   939.7mV    921.8mV    1.665V
627.8ps   1.204V     948.3mV    1.845V
832.9ps   1.638V     1.053V     1.869V
1.006ns   1.764V     1.235V     1.876V
1.302ns   1.784V     1.519V     1.884V
1.545ns   1.791V     1.648V     1.887V
3.333ns   1.799V     1.707V     1.89V
[Rising Waveform]
R_fixture =  50
V_fixture =  0
V_fixture_min =  0
V_fixture_max =  0
170.4ps   212.9uV    -996.3uV   -11.16uV
310.2ps   212.9uV    -2.725mV   144.2mV
522.8ps   35.37mV    -4.885mV   865.9mV
649.9ps   214.2mV    -7.495mV   1.079V
731.4ps   384.4mV    -9.625mV   1.11V
974ps     802.4mV    2.339mV    1.142V
1.227ns   918.9mV    146.4mV    1.154V
1.792ns   961.8mV    591.7mV    1.168V
2.052ns   967.9mV    691.9mV    1.171V
3.478ns   979.8mV    784.6mV    1.177V
[Falling Waveform]
R_fixture =  50
V_fixture =  1.8
V_fixture_min =  1.71
V_fixture_max =  1.89
27.36ps   1.801V     1.71V      1.89V
308.3ps   1.801V     1.71V      1.867V
389.4ps   1.801V     1.711V     1.664V
600.6ps   1.772V     1.726V     976.9mV
746.1ps   1.554V     1.738V     808.6mV
1.044ns   1.015V     1.725V     762.3mV
1.209ns   900.4mV    1.638V     755.1mV
2.006ns   838.8mV    1.022V     745.8mV
2.524ns   834.2mV    935.8mV    744.6mV
3.333ns   832.1mV    913.5mV    744mV
[Falling Waveform]
R_fixture =  50
V_fixture =  0
V_fixture_min =  0
V_fixture_max =  0
144.4ps   984.4mV    802mV      1.176V
238ps     984.4mV    802mV      1.067V
384.6ps   934.2mV    802.2mV    488.1mV
502.9ps   627.8mV    803.6mV    147.8mV
601.3ps   387.9mV    784.2mV    55.03mV
739.7ps   195.2mV    667.3mV    34.75mV
890.3ps   63.02mV    391.5mV    27.29mV
1.074ns   30.37mV    183.6mV    21.66mV
1.382ns   20.02mV    61.96mV    15.97mV
3.478ns   3.035mV    7.773mV    614.5uV
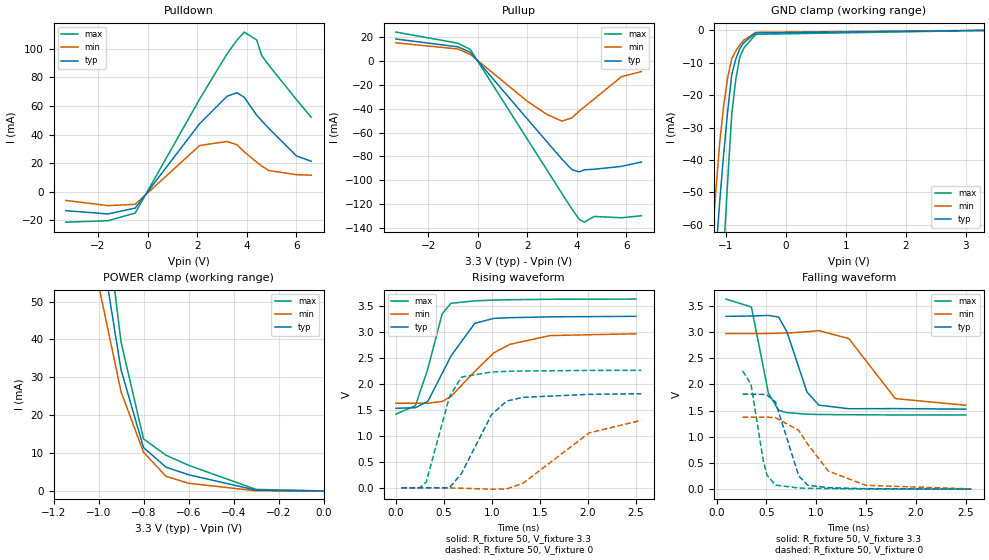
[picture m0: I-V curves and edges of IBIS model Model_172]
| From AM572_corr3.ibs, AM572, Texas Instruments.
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| Model based on original model for BC1833DV40DCPBFBP1811_SSCEH
|   Sub model BC40D_H_10P_!SC1_3P3
[model]   Model_172
|[Description]  [3.3V-I/O-X-40D CLASS MODE FAST MODE, IND, 10 PERCENT%]
|   40D CLASS MODE FAST MODE, ,IND,10 PERCENT%
|[Input Load]
|[Output Drive] 40D CLASS MODE FAST MODE
|Voltage   3.3V
|Mode   I/O
Model_type   I/O
Polarity   Non-Inverting
Enable   Active-Low
Vinl =   0.8V
Vinh =   2V
Cref =   15pF
Rref =   100.0000M
Vref =   0V
Vmeas =   1.65
C_comp   2.155p   1.84p   2.47p
[Model Spec]
Vinl   0.8V   0.8V   0.8V
Vinh   2V   2V   2V
D_overshoot_ampl_h 0.66 0.66 0.66
D_overshoot_ampl_l 0.66 0.66 0.66
D_overshoot_area_h 0.33n 0.33n 0.33n
D_overshoot_area_l 0.33n 0.33n 0.33n
D_overshoot_high 3.96 3.96 3.96
D_overshoot_low -0.66 -0.66 -0.66
D_overshoot_time 1n 1n 1n
S_overshoot_high 3.3 3.3 3.3
S_overshoot_low 0 0 0
[Temperature Range]   25   125   -40
[Voltage Range]   3.3   2.97   3.63
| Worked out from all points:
|   slope of the pulldown table from 0 to 0.495 V, typ, clamps not added: 41.8 ohm
|   slope of the pullup table from 0 to 0.495 V, typ, clamps not added: 40.8 ohm
|   GND clamp passes 1 mA (typ) near -0.52 V on its own axis
|   POWER clamp passes 1 mA (typ) near -0.39 V on its own axis
|   rising waveform, R_fixture 50, V_fixture 3.3: 20-80 % time 324ps typ, 450ps min, 197ps max; typ from 1.53 V to 3.3 V
|   rising waveform, R_fixture 50, V_fixture 0: 20-80 % time 304ps typ, 541ps min, 191ps max; typ from 0.001 V to 1.81 V
|   falling waveform, R_fixture 50, V_fixture 3.3: 20-80 % time 184ps typ, 303ps min, 127ps max; typ from 3.3 V to 1.53 V
|   falling waveform, R_fixture 50, V_fixture 0: 20-80 % time 169ps typ, 342ps min, 115ps max; typ from 1.81 V to 0.002 V
[POWER_clamp]
-3.3V     1.165A     1.155A     1.459A
-1.2V     153.4mA    122mA      196.7mA
-1.167V   138.6mA    109.9mA    177.9mA
-1.1V     109.1mA    85.82mA    140.3mA
-1.067V   95.17mA    74.8mA     122.3mA
-1.033V   81.28mA    63.79mA    104.4mA
-900mV    31.99mA    26.19mA    39.32mA
-800mV    11.44mA    10.22mA    13.73mA
-700mV    6.266mA    3.856mA    9.428mA
-600mV    4.272mA    2.023mA    6.777mA
-300mV    202.9uA    25.56uA    396.8uA
0V        3.057uA    1.011uA    8.442uA
[Pulldown]
-3.3V     -13.13mA   -5.97mA    -21.19mA
-1.6V     -15.43mA   -9.62mA    -20.17mA
-500mV    -11.32mA   -8.666mA   -14.78mA
2.1V      47.73mA    32.41mA    64.9mA
3.2V      66.79mA    35.22mA    96.36mA
3.6V      69.29mA    32.97mA    106mA
3.9V      66.11mA    27.98mA    111.7mA
4.4V      53.6mA     20.79mA    106.2mA
4.6V      49.78mA    18.11mA    95.41mA
4.9V      44.25mA    14.88mA    88.3mA
6V        25.16mA    12.04mA    64.58mA
6.6V      21.4mA     11.7mA     52.2mA
[Pullup]
-3.3V     18.3mA     15.1mA     24.1mA
-800mV    11.75mA    9.951mA    14.8mA
-300mV    7.208mA    5.408mA    9.602mA
2V        -48.63mA   -33.81mA   -65.56mA
2.8V      -67.89mA   -44.94mA   -91.55mA
3.4V      -82.31mA   -50.42mA   -111.1mA
3.8V      -91.08mA   -47.66mA   -124mA
4.1V      -92.88mA   -41.94mA   -132.8mA
4.3V      -91.19mA   -38.5mA    -135mA
4.7V      -90.68mA   -31.83mA   -130.2mA
5.8V      -88.29mA   -13.18mA   -131.3mA
6.6V      -84.62mA   -8.98mA    -129.6mA
[GND_clamp]
-3.3V     -675.1mA   -811.6mA   -985.9mA
-1.233V   -86.22mA   -66.38mA   -141.8mA
-1.167V   -69.2mA    -49.86mA   -116.5mA
-1.1V     -52.6mA    -34.38mA   -91.45mA
-1.033V   -37.65mA   -22.94mA   -67.83mA
-966.7mV  -24.63mA   -14.38mA   -45.95mA
-900mV    -13.56mA   -8.681mA   -25.81mA
-833.3mV  -8.843mA   -6.325mA   -15.09mA
-766.7mV  -5.582mA   -4.435mA   -8.297mA
-700mV    -3.779mA   -3.011mA   -5.442mA
-500mV    -752.8uA   -575uA     -1.188mA
3.3V      3.057uA    52.54uA    8.238uA
[Ramp]
dV/dt_f   1.07604/0.18643003n   0.85734/0.31669656n   1.33506/0.1273343n
dV/dt_r  1.0997358/0.30901203n  0.8429166/0.60758873n   1.362369/0.19249339n
R_load =  50
[Rising Waveform]
R_fixture =  50
V_fixture =  3.3
V_fixture_min =  2.97
V_fixture_max =  3.63
0s        1.528V     1.625V     1.416V
203.3ps   1.539V     1.625V     1.578V
331.9ps   1.66V      1.625V     2.284V
481.4ps   2.196V     1.659V     3.342V
572.7ps   2.531V     1.753V     3.546V
821.6ps   3.162V     2.238V     3.594V
1.021ns   3.257V     2.595V     3.609V
1.188ns   3.27V      2.758V     3.615V
1.605ns   3.286V     2.926V     3.624V
2.5ns     3.296V     2.961V     3.628V
[Rising Waveform]
R_fixture =  50
V_fixture =  0
V_fixture_min =  0
V_fixture_max =  0
57.25ps   717uV      -896.2uV   -137uV
247.4ps   717uV      -896.2uV   -1.986mV
315.9ps   717uV      -896.2uV   111.2mV
558.1ps   821.5uV    -4.384mV   1.753V
683ps     273.5mV    -9.093mV   2.128V
997.5ps   1.41V      -26.99mV   2.226V
1.153ns   1.666V     -23.08mV   2.237V
1.326ns   1.739V     88.83mV    2.245V
2.013ns   1.796V     1.055V     2.256V
2.557ns   1.807V     1.296V     2.258V
[Falling Waveform]
R_fixture =  50
V_fixture =  3.3
V_fixture_min =  2.97
V_fixture_max =  3.63
95.23ps   3.3V       2.97V      3.629V
349.7ps   3.305V     2.97V      3.478V
520.3ps   3.317V     2.972V     1.833V
622.2ps   3.285V     2.977V     1.507V
705.9ps   3.006V     2.981V     1.462V
906.3ps   1.857V     3.005V     1.432V
1.026ns   1.605V     3.027V     1.426V
1.327ns   1.536V     2.874V     1.422V
1.793ns   1.539V     1.73V      1.417V
2.5ns     1.528V     1.602V     1.417V
[Falling Waveform]
R_fixture =  50
V_fixture =  0
V_fixture_min =  0
V_fixture_max =  0
260.7ps   1.815V     1.374V     2.26V
345.4ps   1.815V     1.374V     2.005V
468.8ps   1.81V      1.374V     544.4mV
506.2ps   1.799V     1.374V     266.7mV
590.4ps   1.667V     1.367V     79.03mV
824.5ps   253.1mV    1.122V     23.39mV
913.6ps   77.92mV    860.3mV    17.71mV
1.122ns   28.88mV    346.5mV    12.97mV
1.497ns   11.07mV    74.27mV    4.826mV
2.557ns   2mV        5.918mV    1.072mV
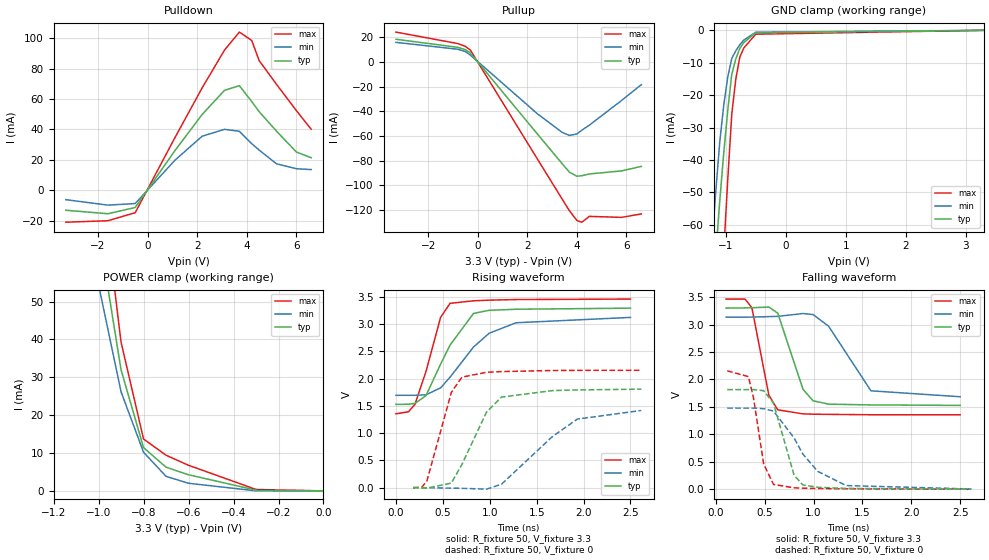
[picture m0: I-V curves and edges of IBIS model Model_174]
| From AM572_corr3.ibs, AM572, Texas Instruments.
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| Model based on original model for BC1833DV40DCPBFBP1811_SSCEH
|   Sub model BC40D_H_5P_!SC1_3P3
[model]   Model_174
|[Description]  [3.3V-I/O-X-40D CLASS MODE FAST MODE, IND, 5 PERCENT%]
|   40D CLASS MODE FAST MODE, ,IND,5 PERCENT%
|[Input Load]
|[Output Drive] 40D CLASS MODE FAST MODE
|Voltage   3.3V
|Mode   I/O
Model_type   I/O
Polarity   Non-Inverting
Enable   Active-Low
Vinl =   0.8V
Vinh =   2V
Cref =   15pF
Rref =   100.0000M
Vref =   0V
Vmeas =   1.65
C_comp   2.155p   1.84p   2.47p
[Model Spec]
Vinl   0.8V   0.8V   0.8V
Vinh   2V   2V   2V
D_overshoot_ampl_h 0.66 0.66 0.66
D_overshoot_ampl_l 0.66 0.66 0.66
D_overshoot_area_h 0.33n 0.33n 0.33n
D_overshoot_area_l 0.33n 0.33n 0.33n
D_overshoot_high 3.96 3.96 3.96
D_overshoot_low -0.66 -0.66 -0.66
D_overshoot_time 1n 1n 1n
S_overshoot_high 3.3 3.3 3.3
S_overshoot_low 0 0 0
[Temperature Range]   25   125   -40
[Voltage Range]   3.3   3.135   3.465
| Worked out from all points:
|   slope of the pulldown table from 0 to 0.495 V, typ, clamps not added: 41.8 ohm
|   slope of the pullup table from 0 to 0.495 V, typ, clamps not added: 40.8 ohm
|   GND clamp passes 1 mA (typ) near -0.52 V on its own axis
|   POWER clamp passes 1 mA (typ) near -0.39 V on its own axis
|   rising waveform, R_fixture 50, V_fixture 3.3: 20-80 % time 324ps typ, 444ps min, 207ps max; typ from 1.53 V to 3.3 V
|   rising waveform, R_fixture 50, V_fixture 0: 20-80 % time 305ps typ, 525ps min, 197ps max; typ from 0 V to 1.81 V
|   falling waveform, R_fixture 50, V_fixture 3.3: 20-80 % time 185ps typ, 286ps min, 128ps max; typ from 3.3 V to 1.53 V
|   falling waveform, R_fixture 50, V_fixture 0: 20-80 % time 169ps typ, 340ps min, 114ps max; typ from 1.81 V to 0.002 V
[POWER_clamp]
-3.3V     1.165A     1.199A     1.459A
-1.2V     153.4mA    122mA      196.7mA
-1.167V   138.6mA    109.9mA    177.9mA
-1.1V     109.1mA    85.82mA    140.3mA
-1.067V   95.17mA    74.81mA    122.3mA
-1.033V   81.28mA    63.8mA     104.4mA
-900mV    31.99mA    26.2mA     39.32mA
-800mV    11.44mA    10.23mA    13.72mA
-700mV    6.266mA    3.859mA    9.425mA
-600mV    4.272mA    2.025mA    6.774mA
-300mV    202.9uA    25.89uA    394.5uA
0V        3.057uA    1.331uA    6.945uA
[Pulldown]
-3.3V     -13.13mA   -6.18mA    -20.99mA
-1.6V     -15.43mA   -9.77mA    -20.04mA
-500mV    -11.32mA   -8.73mA    -14.74mA
1.1V      26.03mA    19.72mA    34.55mA
2.2V      49.83mA    35.55mA    67.32mA
3.1V      65.68mA    40.06mA    92.1mA
3.7V      68.78mA    38.8mA     104mA
4.2V      58.33mA    30.64mA    98.5mA
4.5V      51.67mA    26.43mA    85.24mA
5.2V      38.85mA    17.39mA    69.62mA
6V        25.16mA    14.15mA    52.41mA
6.6V      21.4mA     13.6mA     40.1mA
[Pullup]
-3.3V     18.3mA     15.8mA     24.1mA
-800mV    11.75mA    10.2mA     14.79mA
-500mV    9.91mA     8.354mA    12.52mA
-300mV    7.208mA    5.513mA    9.598mA
2.4V      -58.24mA   -41.91mA   -78.45mA
3.4V      -82.31mA   -57.05mA   -110.9mA
3.7V      -89.31mA   -59.59mA   -120.6mA
4V        -92.6mA    -58.33mA   -128.4mA
4.2V      -92.18mA   -55.34mA   -129.8mA
4.5V      -90.75mA   -51.28mA   -125.1mA
5.8V      -88.29mA   -31.29mA   -125.9mA
6.6V      -84.62mA   -18.44mA   -123.1mA
[GND_clamp]
-3.3V     -675.1mA   -831.9mA   -985.9mA
-1.233V   -86.22mA   -66.38mA   -141.8mA
-1.167V   -69.2mA    -49.86mA   -116.5mA
-1.1V     -52.6mA    -34.38mA   -91.44mA
-1.033V   -37.65mA   -22.95mA   -67.83mA
-966.7mV  -24.63mA   -14.38mA   -45.95mA
-900mV    -13.56mA   -8.682mA   -25.81mA
-833.3mV  -8.843mA   -6.325mA   -15.09mA
-766.7mV  -5.582mA   -4.435mA   -8.297mA
-700mV    -3.779mA   -3.012mA   -5.442mA
-500mV    -752.8uA   -575.1uA   -1.188mA
3.3V      3.057uA    1.928uA    6.853uA
[Ramp]
dV/dt_f   1.07646/0.18731449n   0.91584/0.30391339n   1.2726/0.12886354n
dV/dt_r  1.0997856/0.30956779n  0.9056646/0.57462292n  1.3004274/0.19818034n
R_load =  50
[Rising Waveform]
R_fixture =  50
V_fixture =  3.3
V_fixture_min =  3.135
V_fixture_max =  3.465
0s        1.528V     1.695V     1.356V
132.9ps   1.531V     1.695V     1.392V
204ps     1.547V     1.695V     1.531V
320ps     1.689V     1.705V     2.13V
476.2ps   2.268V     1.832V     3.127V
577.3ps   2.617V     2.029V     3.385V
826.4ps   3.198V     2.581V     3.431V
992.4ps   3.256V     2.834V     3.443V
1.281ns   3.276V     3.028V     3.454V
2.5ns     3.296V     3.126V     3.463V
[Rising Waveform]
R_fixture =  50
V_fixture =  0
V_fixture_min =  0
V_fixture_max =  0
183.3ps   -483.3uV   -978.3uV   -429.4uV
277.9ps   -8.366mV   -978.3uV   8.785mV
330.5ps   -9.395mV   -1.195mV   123.5mV
590.6ps   82.46mV    -9.766mV   1.749V
703.1ps   424.6mV    -13.18mV   2.029V
966.8ps   1.39V      -28.66mV   2.118V
1.126ns   1.663V     63.54mV    2.131V
1.669ns   1.782V     939.4mV    2.151V
1.933ns   1.794V     1.258V     2.153V
2.616ns   1.808V     1.417V     2.155V
[Falling Waveform]
R_fixture =  50
V_fixture =  3.3
V_fixture_min =  3.135
V_fixture_max =  3.465
104ps     3.3V       3.135V     3.465V
297.8ps   3.304V     3.135V     3.465V
368.4ps   3.307V     3.137V     3.307V
542.1ps   3.319V     3.145V     1.713V
633.3ps   3.208V     3.15V      1.447V
891.5ps   1.821V     3.201V     1.373V
994.1ps   1.612V     3.183V     1.367V
1.154ns   1.55V      2.969V     1.364V
1.587ns   1.536V     1.793V     1.357V
2.5ns     1.527V     1.685V     1.356V
[Falling Waveform]
R_fixture =  50
V_fixture =  0
V_fixture_min =  0
V_fixture_max =  0
116.2ps   1.815V     1.478V     2.157V
333.3ps   1.815V     1.478V     2.052V
385.3ps   1.815V     1.478V     1.661V
489ps     1.796V     1.467V     458.2mV
589.8ps   1.566V     1.425V     86.86mV
800.9ps   253.1mV    932.6mV    25.54mV
890ps     77.9mV     640.9mV    18.68mV
1.043ns   35.1mV     324.8mV    12.66mV
1.333ns   14.56mV    66.57mV    7.56mV
2.616ns   1.717mV    4.231mV    934.2uV
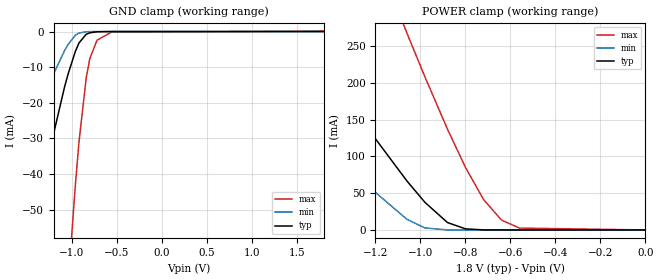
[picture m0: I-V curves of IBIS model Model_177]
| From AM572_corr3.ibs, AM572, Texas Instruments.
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| Model based on original model for GANGARX
|   Sub model usb3rx
[model]   Model_177
|[Description]  [1.8000V-INPUT-X-X]
|   , ,
|[Input Load]
|[Output Drive]
|Voltage   1.8000V
|Mode   INPUT
Model_type   Input
Polarity   Non-Inverting
Enable   Active-High
C_comp   0.01pF   0.01pF   0.01pF
Vinl =   0.01
Vinh =   0.01
[Temperature Range]   25.0000   -40.0000   0.1250k
[Voltage Range]   1.8000V   1.9800V   1.3500V
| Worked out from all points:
|   GND clamp passes 1 mA (typ) near -0.85 V on its own axis
|   POWER clamp passes 1 mA (typ) near -0.79 V on its own axis
[GND_clamp]
-1.8V     -94.42mA   -44.78mA   -407.2mA
-1.64V    -76.09mA   -35.61mA   -332.4mA
-1.6V     -71.54mA   -33.33mA   -313.9mA
-1.08V    -15.48mA   -5.315mA   -85.93mA
-1.04V    -11.82mA   -3.587mA   -70.68mA
-960mV    -5.522mA   -1.018mA   -42.86mA
-920mV    -3.191mA   -409.9uA   -30.92mA
-840mV    -763.4uA   -65uA      -13mA
-800mV    -361.7uA   -21.77uA   -7.598mA
-720mV    -72.92uA   -883.1nA   -2.432mA
-560mV    -457.7nA   -1.023nA   -180.3uA
1.8V      43.22pA    38.88pA    132.4uA
[POWER_clamp]
-1.8V     384mA      225.1mA    857.4mA
-1.3V     165mA      77.13mA    454.1mA
-1.06V    66.6mA     14.48mA    267.8mA
-980mV    37.54mA    2.746mA    208.2mA
-880mV    10.11mA    50.91uA    137.2mA
-800mV    1.482mA    1.034uA    85.17mA
-720mV    89.22uA    24.39nA    41.65mA
-640mV    4.421uA    721.7pA    13.51mA
-560mV    238.4nA    92.59pA    2.567mA
0V        43.22pA    47.52pA    315.5pA
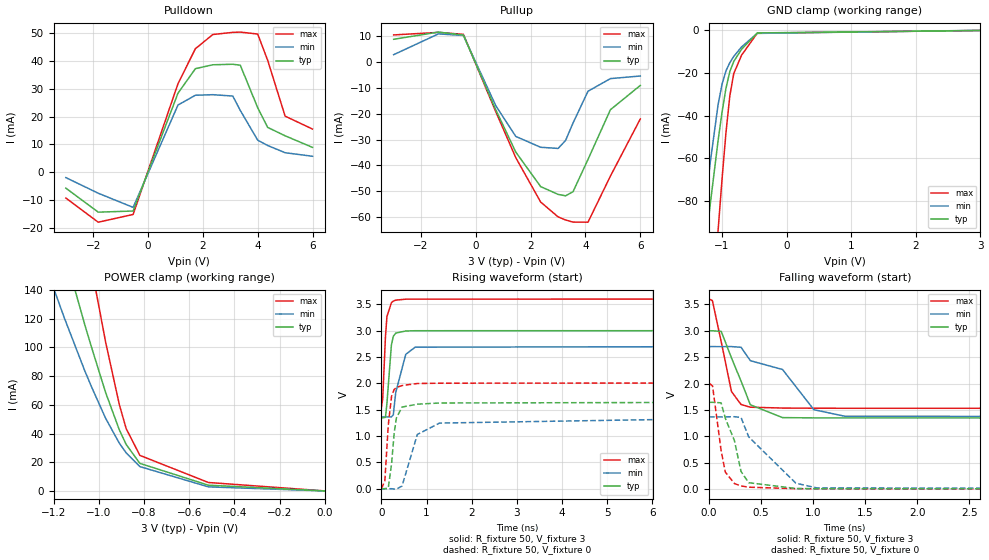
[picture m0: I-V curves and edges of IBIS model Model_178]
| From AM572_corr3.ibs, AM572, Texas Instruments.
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| Model based on original model for SDIO1833PB_H
|   Sub model 50OHMS_3
[model]   Model_178
|[Description]  [3V-I/O-X-X]
|   , ,
|[Input Load]
|[Output Drive]
|Voltage   3V
|Mode   I/O
Model_type   I/O
Polarity   Non-Inverting
Enable   Active-Low
Vinl =   0.75
Vinh =   1.875
Cref =   15.0000pF
Rref =   100.0000M
Vref =   0V
Vmeas =   1.5
C_comp   5p   5p   5p
[Model Spec]
Vinl   0.75   0.675   0.9
Vinh   1.875   1.6875   2.25
[Temperature Range]   25   125   -40
[Voltage Range]   3   2.7   3.6
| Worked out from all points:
|   slope of the pulldown table from 0 to 0.45 V, typ, clamps not added: 35 ohm
|   slope of the pullup table from 0 to 0.45 V, typ, clamps not added: 38.8 ohm
|   GND clamp passes 1 mA (typ) near -0.44 V on its own axis
|   POWER clamp passes 1 mA (typ) near -0.35 V on its own axis
|   rising waveform, R_fixture 50, V_fixture 3: 20-80 % time 86.4ps typ, 191ps min, 68.5ps max; typ from 1.35 V to 3 V
|   rising waveform, R_fixture 50, V_fixture 0: 20-80 % time 115ps typ, 302ps min, 99.1ps max; typ from 0 V to 1.64 V
|   falling waveform, R_fixture 50, V_fixture 3: 20-80 % time 208ps typ, 533ps min, 119ps max; typ from 3 V to 1.35 V
|   falling waveform, R_fixture 50, V_fixture 0: 20-80 % time 148ps typ, 403ps min, 85.5ps max; typ from 1.64 V to 0 V
[POWER_clamp]
-3V       1.325A     1.067A     2.083A
-1.273V   237.5mA    173.3mA    376.8mA
-1.242V   219.5mA    159.8mA    348.1mA
-1.152V   166.4mA    120.5mA    263mA
-1.061V   115.4mA    83.39mA    180.6mA
-1.03V    99.16mA    71.83mA    154.1mA
-969.7mV  68.62mA    50.64mA    103.8mA
-909.1mV  42.6mA     33.3mA     60.24mA
-878.8mV  32.4mA     26.56mA    43.46mA
-818.2mV  19.2mA     16.96mA    24.78mA
-515.2mV  4.001mA    2.832mA    5.883mA
0V        300.2nA    570.8nA    4.935uA
[Pulldown]
-3V       -5.757mA   -1.961mA   -9.316mA
-1.818V   -14.39mA   -7.583mA   -18mA
-545.5mV  -13.98mA   -12.67mA   -15.22mA
1.091V    28.41mA    24.15mA    31.82mA
1.727V    37.23mA    27.67mA    44.43mA
2.364V    38.63mA    27.87mA    49.52mA
3.091V    38.82mA    27.38mA    50.29mA
3.364V    38.48mA    22.21mA    50.39mA
4V        23.17mA    11.51mA    49.68mA
4.364V    16.1mA     9.581mA    40.22mA
5V        13.08mA    6.998mA    20.15mA
6V        8.913mA    5.713mA    15.5mA
[Pullup]
-3V       8.892mA    2.914mA    10.58mA
-1.364V   11.68mA    10.99mA    11.56mA
-454.5mV  10.52mA    10.35mA    10.8mA
727.3mV   -18.47mA   -16.87mA   -19.22mA
1.455V    -34.83mA   -28.77mA   -36.99mA
2.364V    -48.23mA   -32.98mA   -54.22mA
3V        -51.25mA   -33.43mA   -59.97mA
3.273V    -51.81mA   -30.34mA   -61.17mA
3.545V    -50.21mA   -23.58mA   -61.99mA
4.091V    -37.71mA   -11.25mA   -62.03mA
4.909V    -18.42mA   -6.357mA   -44.15mA
6V        -8.996mA   -5.343mA   -22mA
[GND_clamp]
-3V       -611.3mA   -669.6mA   -1.002A
-1.303V   -113.3mA   -94.63mA   -198.1mA
-1.242V   -97.2mA    -77.77mA   -171.3mA
-1.182V   -81.45mA   -61.83mA   -144.9mA
-1.061V   -51.68mA   -34.78mA   -93.82mA
-1V       -38.37mA   -25.24mA   -69.83mA
-939.4mV  -27.14mA   -18.97mA   -48.01mA
-878.8mV  -19.2mA    -15.02mA   -30.51mA
-818.2mV  -14.5mA    -12.17mA   -20.19mA
-697mV    -8.773mA   -7.671mA   -11.56mA
-454.5mV  -1.145mA   -1.361mA   -1.238mA
3V        300.2nA    80.94uA    4.624uA
[Ramp]
dV/dt_f 0.99180644/0.20793772n 0.80195524/0.53341113n  1.2409451/0.11904976n
dV/dt_r 0.99111033/0.11518039n 0.82531613/0.30221099n  1.2090524/99.36045p
R_load =  50
[Rising Waveform]
R_fixture =  50
V_fixture =  3
V_fixture_min =  2.7
V_fixture_max =  3.6
0s        1.347V     1.363V     1.532V
30.6ps    1.346V     1.363V     1.703V
91.9ps    1.355V     1.363V     2.889V
124.4ps   1.623V     1.363V     3.27V
223.2ps   2.729V     1.364V     3.53V
265.2ps   2.893V     1.402V     3.56V
319ps     2.954V     1.827V     3.58V
540.8ps   2.994V     2.551V     3.598V
750.5ps   2.999V     2.687V     3.599V
10.02ns   3V         2.7V       3.6V
[Rising Waveform]
R_fixture =  50
V_fixture =  0
V_fixture_min =  0
V_fixture_max =  0
0s        0V         0V         0V
78.1ps    0V         0V         146.3mV
153.8ps   12.6mV     0V         1.207V
227.2ps   473.7mV    0V         1.758V
283.9ps   1.052V     -6.132mV   1.884V
332.5ps   1.34V      -8.553mV   1.919V
458.1ps   1.55V      50.31mV    1.959V
797.1ps   1.605V     1.03V      1.997V
1.288ns   1.627V     1.246V     2.003V
10.01ns   1.644V     1.367V     2.008V
[Falling Waveform]
R_fixture =  50
V_fixture =  3
V_fixture_min =  2.7
V_fixture_max =  3.6
0s        3V         2.7V       3.6V
31.6ps    3V         2.7V       3.571V
116.6ps   2.987V     2.699V     2.789V
214.8ps   2.485V     2.7V       1.848V
306.7ps   2.047V     2.687V     1.604V
396.2ps   1.598V     2.433V     1.552V
705.3ps   1.355V     2.266V     1.536V
1.006ns   1.35V      1.505V     1.533V
1.303ns   1.349V     1.381V     1.532V
10.02ns   1.347V     1.363V     1.532V
[Falling Waveform]
R_fixture =  50
V_fixture =  0
V_fixture_min =  0
V_fixture_max =  0
0s        1.644V     1.368V     2.007V
33.1ps    1.645V     1.368V     1.955V
115.1ps   1.635V     1.368V     732.8mV
155.8ps   1.343V     1.37V      322.1mV
243.4ps   917.1mV    1.372V     105.7mV
306.6ps   334.9mV    1.357V     60.74mV
380.1ps   122.4mV    990.7mV    37.71mV
833.5ps   13.31mV    112.8mV    8.495mV
1.035ns   8.855mV    23.78mV    7.318mV
10.01ns   0V         0V         0V
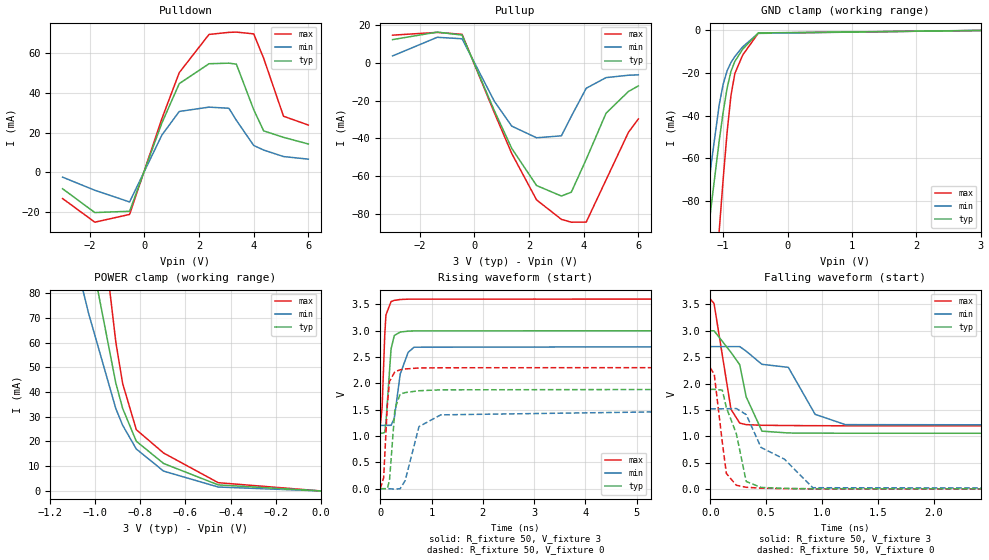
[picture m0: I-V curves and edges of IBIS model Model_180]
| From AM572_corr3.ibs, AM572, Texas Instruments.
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| Model based on original model for SDIO1833PB_H
|   Sub model 33OHMS_3
[model]   Model_180
|[Description]  [3V-I/O-X-X]
|   , ,
|[Input Load]
|[Output Drive]
|Voltage   3V
|Mode   I/O
Model_type   I/O
Polarity   Non-Inverting
Enable   Active-Low
Vinl =   0.75
Vinh =   1.875
Cref =   15.0000pF
Rref =   100.0000M
Vref =   0V
Vmeas =   1.5
C_comp   5p   5p   5p
[Model Spec]
Vinl   0.75   0.675   0.9
Vinh   1.875   1.6875   2.25
[Temperature Range]   25   125   -40
[Voltage Range]   3   2.7   3.6
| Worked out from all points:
|   slope of the pulldown table from 0 to 0.45 V, typ, clamps not added: 25.1 ohm
|   slope of the pullup table from 0 to 0.45 V, typ, clamps not added: 28.2 ohm
|   GND clamp passes 1 mA (typ) near -0.44 V on its own axis
|   POWER clamp passes 1 mA (typ) near -0.38 V on its own axis
|   rising waveform, R_fixture 50, V_fixture 3: 20-80 % time 79.3ps typ, 175ps min, 54.3ps max; typ from 1.05 V to 3 V
|   rising waveform, R_fixture 50, V_fixture 0: 20-80 % time 83.3ps typ, 249ps min, 73ps max; typ from 0 V to 1.89 V
|   falling waveform, R_fixture 50, V_fixture 3: 20-80 % time 174ps typ, 503ps min, 103ps max; typ from 3 V to 1.05 V
|   falling waveform, R_fixture 50, V_fixture 0: 20-80 % time 144ps typ, 386ps min, 73ps max; typ from 1.89 V to 0 V
[POWER_clamp]
-3V       1.325A     1.067A     2.083A
-1.273V   239mA      173.3mA    376.8mA
-1.242V   221mA      159.8mA    348.1mA
-1.152V   167.8mA    120.5mA    263mA
-1.061V   116.6mA    83.39mA    180.6mA
-1.03V    100.4mA    71.83mA    154.1mA
-909.1mV  43.62mA    33.3mA     60.24mA
-878.8mV  33.38mA    26.56mA    43.46mA
-818.2mV  20.09mA    16.96mA    24.78mA
-697mV    11.1mA     8.01mA     15.33mA
-454.5mV  2.435mA    1.581mA    3.331mA
0V        300.3nA    570.8nA    4.935uA
[Pulldown]
-3V       -8.17mA    -2.34mA    -13.08mA
-1.818V   -20.15mA   -8.943mA   -24.99mA
-545.5mV  -19.5mA    -14.82mA   -21.08mA
636.4mV   24.87mA    18.8mA     27.04mA
1.273V    44.68mA    30.69mA    50.22mA
2.364V    54.69mA    32.87mA    69.43mA
3.091V    54.97mA    32.3mA     70.46mA
3.364V    54.49mA    26.26mA    70.6mA
4V        31.57mA    13.58mA    69.7mA
4.364V    20.93mA    11.29mA    57.43mA
5.091V    17.67mA    8.008mA    28.29mA
6V        14.33mA    6.719mA    23.86mA
[Pullup]
-3V       12.07mA    3.483mA    14.42mA
-1.364V   16.04mA    13.3mA     15.88mA
-454.5mV  14.46mA    12.53mA    14.86mA
727.3mV   -25.36mA   -20.41mA   -26.43mA
1.364V    -45.21mA   -33.49mA   -47.91mA
2.273V    -64.78mA   -39.62mA   -72.34mA
3.182V    -70.31mA   -38.61mA   -82.6mA
3.545V    -68.29mA   -28.36mA   -84.09mA
4.091V    -50.99mA   -13.54mA   -84.05mA
4.818V    -26.68mA   -7.937mA   -61.81mA
5.636V    -15.26mA   -6.689mA   -36.83mA
6V        -12.31mA   -6.483mA   -29.7mA
[GND_clamp]
-3V       -611.3mA   -669.6mA   -1.002A
-1.303V   -113.3mA   -94.63mA   -198.1mA
-1.242V   -97.2mA    -77.77mA   -171.3mA
-1.182V   -81.45mA   -61.83mA   -144.9mA
-1.061V   -51.68mA   -34.78mA   -93.82mA
-1V       -38.37mA   -25.24mA   -69.83mA
-939.4mV  -27.14mA   -18.97mA   -48.01mA
-878.8mV  -19.2mA    -15.02mA   -30.51mA
-818.2mV  -14.5mA    -12.17mA   -20.19mA
-697mV    -8.773mA   -7.671mA   -11.56mA
-454.5mV  -1.145mA   -1.361mA   -1.238mA
3V        300.3nA    80.94uA    4.624uA
[Ramp]
dV/dt_f  1.1669541/0.17415037n 0.89851794/0.50291385n  1.4405989/0.10347378n
dV/dt_r  1.1401744/83.802642p 0.91858973/0.24989395n  1.3849437/73.222635p
R_load =  50
[Rising Waveform]
R_fixture =  50
V_fixture =  3
V_fixture_min =  2.7
V_fixture_max =  3.6
0s        1.055V     1.202V     1.2V
36.2ps    1.055V     1.202V     1.547V
87ps      1.068V     1.202V     2.915V
110.6ps   1.257V     1.202V     3.299V
210ps     2.651V     1.203V     3.552V
273ps     2.908V     1.334V     3.575V
389.1ps   2.974V     2.178V     3.592V
542.9ps   2.991V     2.588V     3.598V
659.2ps   2.996V     2.686V     3.599V
10.01ns   3V         2.7V       3.6V
[Rising Waveform]
R_fixture =  50
V_fixture =  0
V_fixture_min =  0
V_fixture_max =  0
0s        0V         0V         0V
66.2ps    0V         0V         208.2mV
136.4ps   0V         0V         1.565V
179.7ps   155.3mV    0V         2.038V
285.9ps   1.515V     -8.565mV   2.222V
387.1ps   1.796V     0V         2.257V
485.8ps   1.825V     155mV      2.273V
755ps     1.86V      1.179V     2.292V
1.18ns    1.877V     1.402V     2.296V
10.02ns   1.89V      1.521V     2.3V
[Falling Waveform]
R_fixture =  50
V_fixture =  3
V_fixture_min =  2.7
V_fixture_max =  3.6
0s        3V         2.7V       3.6V
33.9ps    2.999V     2.7V       3.515V
185.5ps   2.59V      2.7V       1.512V
263.9ps   2.356V     2.7V       1.251V
321.4ps   1.75V      2.614V     1.222V
462.8ps   1.099V     2.364V     1.21V
699.2ps   1.064V     2.307V     1.205V
939.6ps   1.061V     1.416V     1.202V
1.211ns   1.059V     1.222V     1.2V
10.01ns   1.055V     1.202V     1.199V
[Falling Waveform]
R_fixture =  50
V_fixture =  0
V_fixture_min =  0
V_fixture_max =  0
0s        1.89V      1.522V     2.299V
35.8ps    1.89V      1.522V     2.173V
107.8ps   1.875V     1.522V     887.4mV
144.1ps   1.546V     1.523V     297.9mV
233.6ps   1.049V     1.527V     73.27mV
321.9ps   145.4mV    1.413V     35.62mV
454.8ps   33.09mV    789.8mV    19.28mV
664ps     14.72mV    568.4mV    10.41mV
918.6ps   8.438mV    27.46mV    6.076mV
10.02ns   0V         0V         0V
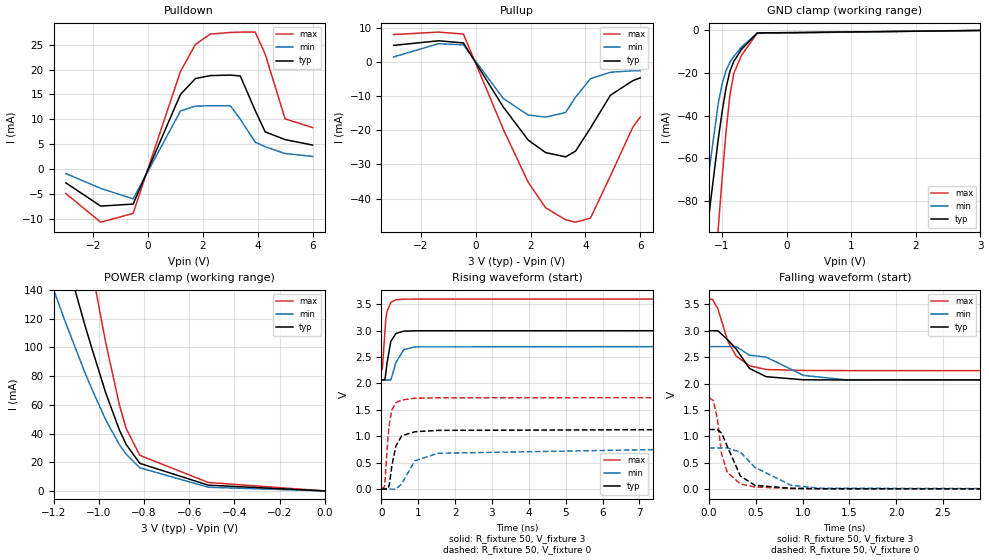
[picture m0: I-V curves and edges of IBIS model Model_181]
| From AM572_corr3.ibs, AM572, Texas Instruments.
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| Model based on original model for SDIO1833PB_H
|   Sub model 100OHMS_3
[model]   Model_181
|[Description]  [3V-I/O-X-X]
|   , ,
|[Input Load]
|[Output Drive]
|Voltage   3V
|Mode   I/O
Model_type   I/O
Polarity   Non-Inverting
Enable   Active-Low
Vinl =   0.75
Vinh =   1.875
Cref =   15.0000pF
Rref =   100.0000M
Vref =   0V
Vmeas =   1.5
C_comp   5p   5p   5p
[Model Spec]
Vinl   0.75   0.675   0.9
Vinh   1.875   1.6875   2.25
[Temperature Range]   25   125   -40
[Voltage Range]   3   2.7   3.6
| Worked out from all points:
|   slope of the pulldown table from 0 to 0.45 V, typ, clamps not added: 69.5 ohm
|   slope of the pullup table from 0 to 0.45 V, typ, clamps not added: 73.5 ohm
|   GND clamp passes 1 mA (typ) near -0.44 V on its own axis
|   rising waveform, R_fixture 50, V_fixture 3: 20-80 % time 135ps typ, 229ps min, 95.9ps max; typ from 2.06 V to 3 V
|   rising waveform, R_fixture 50, V_fixture 0: 20-80 % time 199ps typ, 546ps min, 132ps max; typ from 0 V to 1.13 V
|   falling waveform, R_fixture 50, V_fixture 3: 20-80 % time 239ps typ, 574ps min, 182ps max; typ from 3 V to 2.06 V
|   falling waveform, R_fixture 50, V_fixture 0: 20-80 % time 179ps typ, 430ps min, 104ps max; typ from 1.13 V to 0 V
[POWER_clamp]
-3V       1.325A     1.066A     2.083A
-1.273V   237.5mA    172.4mA    376.8mA
-1.242V   219.5mA    158.9mA    348.1mA
-1.152V   166.4mA    119.5mA    263mA
-1.061V   115.4mA    82.4mA     180.6mA
-1.03V    99.16mA    70.84mA    154.1mA
-969.7mV  68.62mA    49.67mA    103.8mA
-909.1mV  42.6mA     32.36mA    60.24mA
-878.8mV  32.4mA     25.65mA    43.46mA
-818.2mV  19.2mA     16.11mA    24.78mA
-515.2mV  4.001mA    2.562mA    5.883mA
0V        300.2nA    570.7nA    4.935uA
[Pulldown]
-3V       -2.807mA   -942.1uA   -4.958mA
-1.727V   -7.49mA    -3.919mA   -10.73mA
-545.5mV  -7.082mA   -6.034mA   -8.964mA
1.182V    15mA       11.67mA    19.62mA
1.727V    18.19mA    12.64mA    25.07mA
2.273V    18.79mA    12.72mA    27.15mA
3V        18.89mA    12.71mA    27.48mA
3.364V    18.71mA    10.01mA    27.54mA
3.909V    11.75mA    5.369mA    27.55mA
4.273V    7.462mA    4.465mA    23.11mA
5V        5.896mA    3.105mA    10.07mA
6V        4.801mA    2.514mA    8.333mA
[Pullup]
-3V       4.821mA    1.443mA    7.993mA
-1.364V   6.173mA    5.312mA    8.713mA
-454.5mV  5.546mA    4.984mA    8.133mA
1V        -13.19mA   -10.71mA   -19.68mA
1.909V    -22.87mA   -15.54mA   -35.22mA
2.545V    -26.52mA   -16.14mA   -42.66mA
3.273V    -27.78mA   -14.82mA   -46.17mA
3.636V    -26.11mA   -10.33mA   -46.88mA
4.182V    -19.33mA   -4.906mA   -45.69mA
4.909V    -9.77mA    -3.025mA   -33.32mA
5.727V    -5.482mA   -2.603mA   -19.09mA
6V        -4.667mA   -2.545mA   -16.11mA
[GND_clamp]
-3V       -611.3mA   -669.6mA   -1.002A
-1.303V   -113.3mA   -94.63mA   -198.1mA
-1.242V   -97.2mA    -77.77mA   -171.3mA
-1.182V   -81.45mA   -61.83mA   -144.9mA
-1.061V   -51.68mA   -34.78mA   -93.82mA
-1V       -38.37mA   -25.24mA   -69.83mA
-939.4mV  -27.14mA   -18.97mA   -48.01mA
-878.8mV  -19.2mA    -15.02mA   -30.51mA
-818.2mV  -14.5mA    -12.17mA   -20.19mA
-697mV    -8.773mA   -7.671mA   -11.56mA
-454.5mV  -1.145mA   -1.361mA   -1.238mA
3V        300.2nA    77.91uA    4.624uA
[Ramp]
dV/dt_f 0.56076448/0.23901519n 0.38113518/0.5736575n 0.81359504/0.18240224n
dV/dt_r  0.6799911/0.1994388n 0.46884724/0.54483569n  1.0428012/0.13174299n
R_load =  50
[Rising Waveform]
R_fixture =  50
V_fixture =  3
V_fixture_min =  2.7
V_fixture_max =  3.6
0s        2.065V     2.065V     2.245V
28ps      2.065V     2.065V     2.28V
97.3ps    2.071V     2.065V     2.972V
119.7ps   2.183V     2.065V     3.2V
153.4ps   2.383V     2.065V     3.361V
258.1ps   2.798V     2.067V     3.537V
396.7ps   2.949V     2.398V     3.587V
609.4ps   2.991V     2.643V     3.598V
919.7ps   2.999V     2.693V     3.599V
10.03ns   3V         2.7V       3.6V
[Rising Waveform]
R_fixture =  50
V_fixture =  0
V_fixture_min =  0
V_fixture_max =  0
0s        0V         0V         0V
89.8ps    0V         0V         44.77mV
180.6ps   0V         0V         987.3mV
219.1ps   89.98mV    0V         1.229V
283.6ps   428.7mV    -2.578mV   1.494V
395.8ps   816.7mV    -3.516mV   1.639V
555.3ps   1.009V     103mV      1.687V
910.8ps   1.085V     535.2mV    1.721V
1.545ns   1.111V     677.2mV    1.728V
10.01ns   1.129V     777.4mV    1.733V
[Falling Waveform]
R_fixture =  50
V_fixture =  3
V_fixture_min =  2.7
V_fixture_max =  3.6
0s        3V         2.7V       3.6V
35.7ps    3V         2.7V       3.597V
93.2ps    3V         2.7V       3.416V
200.9ps   2.826V     2.7V       2.797V
290.3ps   2.651V     2.699V     2.518V
431.5ps   2.286V     2.537V     2.337V
609.9ps   2.13V      2.501V     2.266V
1.011ns   2.071V     2.154V     2.248V
1.45ns    2.068V     2.073V     2.245V
10.03ns   2.065V     2.065V     2.244V
[Falling Waveform]
R_fixture =  50
V_fixture =  0
V_fixture_min =  0
V_fixture_max =  0
0s        1.129V     778.2mV    1.732V
44.7ps    1.13V      778.1mV    1.679V
88.1ps    1.13V      778.5mV    1.334V
133.6ps   1.062V     779.7mV    663.3mV
192.9ps   816.2mV    781.7mV    324.8mV
333.9ps   250.3mV    702.3mV    98.43mV
488.6ps   73.47mV    413.2mV    41.54mV
876.1ps   16.15mV    74.03mV    12.08mV
1.19ns    8.337mV    16.17mV    9.17mV
10.01ns   0V         0V         0V
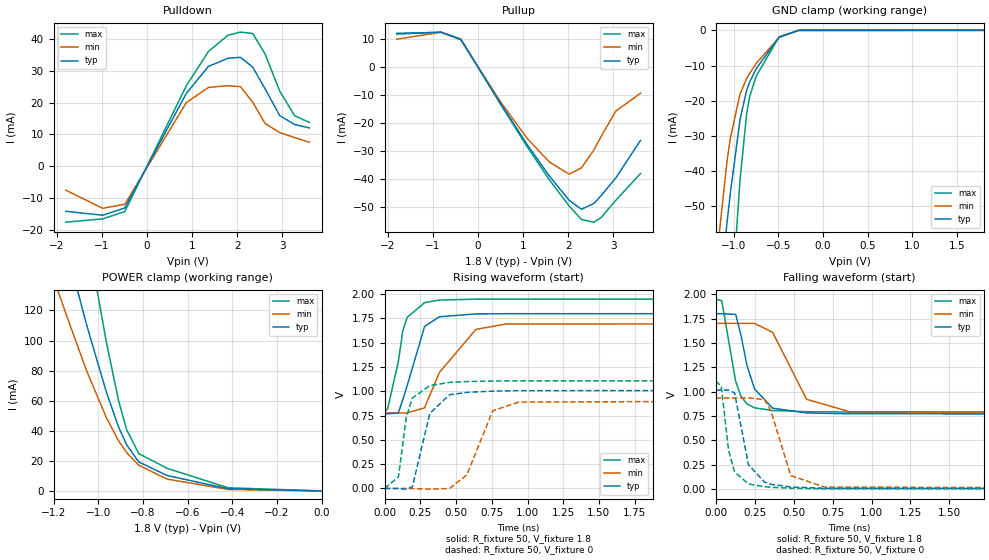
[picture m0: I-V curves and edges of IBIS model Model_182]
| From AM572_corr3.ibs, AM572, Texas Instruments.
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| Model based on original model for SDIO1833PB_H
|   Sub model 50OHMS_1P8
[model]   Model_182
|[Description]  [1.8V-I/O-X-X]
|   , ,
|[Input Load]
|[Output Drive]
|Voltage   1.8V
|Mode   I/O
Model_type   I/O
Polarity   Non-Inverting
Enable   Active-Low
Vinl =   0.58
Vinh =   1.27
Cref =   15.0000pF
Rref =   100.0000M
Vref =   0V
Vmeas =   0.9
C_comp   5p   5p   5p
[Model Spec]
Vinl   0.58   0.58   0.58
Vinh   1.27   1.27   1.27
[Temperature Range]   25   125   -40
[Voltage Range]   1.8   1.7   1.95
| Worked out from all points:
|   slope of the pulldown table from 0 to 0.27 V, typ, clamps not added: 35.1 ohm
|   slope of the pullup table from 0 to 0.27 V, typ, clamps not added: 37.8 ohm
|   GND clamp passes 1 mA (typ) near -0.44 V on its own axis
|   POWER clamp passes 1 mA (typ) near -0.39 V on its own axis
|   rising waveform, R_fixture 50, V_fixture 1.8: 20-80 % time 122ps typ, 260ps min, 91.6ps max; typ from 0.769 V to 1.8 V
|   rising waveform, R_fixture 50, V_fixture 0: 20-80 % time 89.3ps typ, 140ps min, 70.1ps max; typ from 0 V to 1.02 V
|   falling waveform, R_fixture 50, V_fixture 1.8: 20-80 % time 105ps typ, 172ps min, 84.4ps max; typ from 1.8 V to 0.769 V
|   falling waveform, R_fixture 50, V_fixture 0: 20-80 % time 78.8ps typ, 101ps min, 60.7ps max; typ from 1.02 V to 0 V
[POWER_clamp]
-1.8V     561.4mA    419.9mA    888.8mA
-1.255V   226.8mA    165.3mA    359.5mA
-1.145V   163mA      118mA      257.5mA
-1.055V   112.2mA    81.16mA    175.3mA
-1.036V   102.4mA    74.22mA    159.4mA
-963.6mV  65.82mA    48.82mA    99.04mA
-909.1mV  42.63mA    33.4mA     60.25mA
-872.7mV  30.7mA     25.48mA    40.71mA
-818.2mV  19.23mA    17.04mA    24.79mA
-690.9mV  10.22mA    7.829mA    15mA
-418.2mV  1.448mA    990.1uA    2.08mA
0V        129.6nA    360.7nA    629.8nA
[Pulldown]
-1.8V     -14.22mA   -7.539mA   -17.66mA
-981.8mV  -15.47mA   -13.27mA   -16.62mA
-490.9mV  -13.17mA   -12.02mA   -14.32mA
872.7mV   22.95mA    20.06mA    25.36mA
1.364V    31.49mA    24.85mA    36.2mA
1.8V      34.05mA    25.39mA    41.32mA
2.073V    34.34mA    25.07mA    42.3mA
2.345V    31.24mA    20.17mA    41.86mA
2.618V    24.41mA    13.49mA    35.39mA
2.945V    15.93mA    10.58mA    23.64mA
3.273V    13.16mA    9.054mA    15.94mA
3.6V      12.07mA    7.555mA    13.81mA
[Pullup]
-1.8V     11.88mA    9.79mA     11.59mA
-818.2mV  12.23mA    12.27mA    12.32mA
-381.8mV  9.685mA    9.599mA    9.837mA
490.9mV   -12.87mA   -12.31mA   -13.15mA
1.091V    -27.77mA   -25.57mA   -28.54mA
1.582V    -38.92mA   -33.92mA   -40.26mA
2.018V    -47.51mA   -38.24mA   -49.51mA
2.291V    -50.75mA   -36.02mA   -54.36mA
2.564V    -48.7mA    -29.74mA   -55.34mA
2.727V    -45.91mA   -24.86mA   -53.71mA
3.055V    -39.56mA   -15.76mA   -47.5mA
3.6V      -26.24mA   -9.461mA   -38.06mA
[GND_clamp]
-1.8V     -253.4mA   -247.4mA   -423.2mA
-1.291V   -110mA     -91.19mA   -190.6mA
-1.218V   -90.83mA   -71.25mA   -158.7mA
-1.073V   -54.5mA    -37.07mA   -96.88mA
-1.036V   -46.17mA   -30.57mA   -82.18mA
-927.3mV  -25.27mA   -18.03mA   -42.33mA
-854.5mV  -17.03mA   -13.79mA   -23.85mA
-818.2mV  -14.52mA   -12.16mA   -18.62mA
-745.5mV  -10.85mA   -9.341mA   -12.96mA
-490.9mV  -1.928mA   -2.053mA   -1.836mA
-272.7mV  -6.492uA   -27.59uA   -4.834uA
1.8V      129.6nA    593.1nA    619.7nA
[Ramp]
dV/dt_f 0.62018161/0.10533019n 0.55416185/0.17208208n 0.69916283/84.490648p
dV/dt_r  0.6141271/89.642437p 0.56544079/0.14078334n 0.67152837/70.234001p
R_load =  50
[Rising Waveform]
R_fixture =  50
V_fixture =  1.8
V_fixture_min =  1.7
V_fixture_max =  1.95
0s        768.6mV    777.8mV    789.5mV
21.1ps    768.3mV    777.8mV    821.1mV
95.7ps    777.6mV    777.4mV    1.304V
126.8ps   912.7mV    777.6mV    1.619V
157.1ps   1.055V     777.9mV    1.761V
279.6ps   1.668V     830.4mV    1.913V
383.5ps   1.768V     1.195V     1.94V
639.4ps   1.797V     1.638V     1.949V
848.5ps   1.799V     1.693V     1.949V
10.02ns   1.8V       1.7V       1.95V
[Rising Waveform]
R_fixture =  50
V_fixture =  0
V_fixture_min =  0
V_fixture_max =  0
0s        0V         0V         0V
96.8ps    0V         0V         119.4mV
151ps     -7.159mV   0V         731.1mV
194.4ps   18.44mV    0V         932.2mV
316.3ps   772.8mV    -7.172mV   1.059V
453.6ps   964.6mV    0V         1.092V
575.1ps   989.4mV    139mV      1.101V
756.9ps   1.002V     800.4mV    1.106V
937.9ps   1.007V     889.4mV    1.108V
10.01ns   1.016V     935.2mV    1.112V
[Falling Waveform]
R_fixture =  50
V_fixture =  1.8
V_fixture_min =  1.7
V_fixture_max =  1.95
0s        1.8V       1.7V       1.95V
38.5ps    1.8V       1.7V       1.933V
128ps     1.793V     1.7V       1.106V
162ps     1.578V     1.7V       954.1mV
201.1ps   1.265V     1.7V       874.8mV
249.1ps   1.028V     1.7V       834.6mV
365ps     830.7mV    1.609V     806.4mV
583.2ps   782.2mV    921.7mV    795.1mV
860.1ps   772.9mV    793.7mV    791.1mV
10.02ns   768.6mV    777.8mV    788.6mV
[Falling Waveform]
R_fixture =  50
V_fixture =  0
V_fixture_min =  0
V_fixture_max =  0
0s        1.016V     935.3mV    1.112V
35.7ps    1.016V     935.2mV    1.051V
82.5ps    1.016V     935.1mV    397.8mV
120.4ps   989.9mV    935mV      177.7mV
210.2ps   250.4mV    935.8mV    53.39mV
312.9ps   72.73mV    919.6mV    25.18mV
353.9ps   50mV       804mV      19.67mV
481.8ps   22.32mV    138.7mV    9.934mV
700.1ps   8.792mV    20.64mV    3.279mV
10.01ns   0V         0V         0V
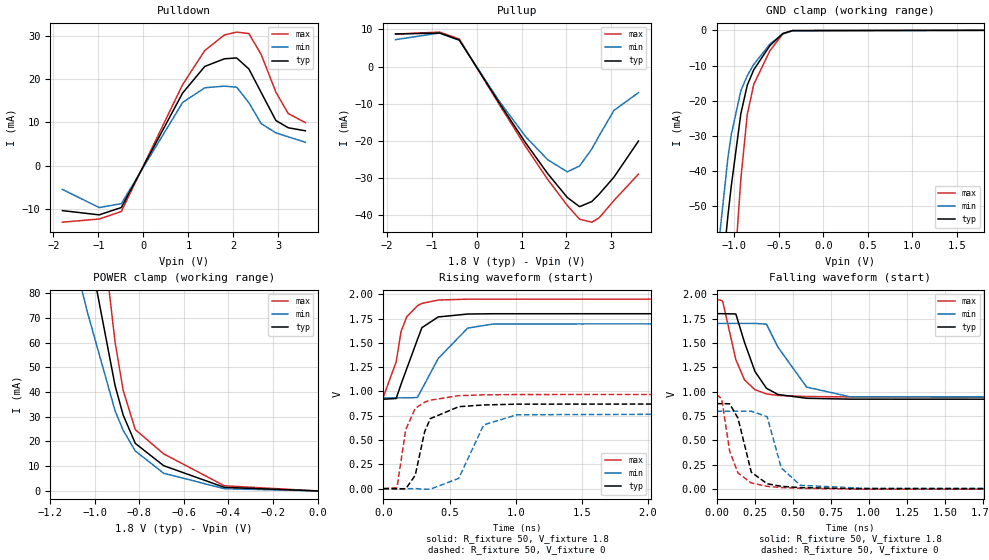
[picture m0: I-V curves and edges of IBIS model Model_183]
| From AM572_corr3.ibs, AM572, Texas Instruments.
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| Model based on original model for SDIO1833PB_H
|   Sub model 66OHMS_1P8
[model]   Model_183
|[Description]  [1.8V-I/O-X-X]
|   , ,
|[Input Load]
|[Output Drive]
|Voltage   1.8V
|Mode   I/O
Model_type   I/O
Polarity   Non-Inverting
Enable   Active-Low
Vinl =   0.58
Vinh =   1.27
Cref =   15.0000pF
Rref =   100.0000M
Vref =   0V
Vmeas =   0.9
C_comp   5p   5p   5p
[Model Spec]
Vinl   0.58   0.58   0.58
Vinh   1.27   1.27   1.27
[Temperature Range]   25   125   -40
[Voltage Range]   1.8   1.7   1.95
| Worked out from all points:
|   slope of the pulldown table from 0 to 0.27 V, typ, clamps not added: 47.7 ohm
|   slope of the pullup table from 0 to 0.27 V, typ, clamps not added: 51.3 ohm
|   GND clamp passes 1 mA (typ) near -0.46 V on its own axis
|   POWER clamp passes 1 mA (typ) near -0.39 V on its own axis
|   rising waveform, R_fixture 50, V_fixture 1.8: 20-80 % time 140ps typ, 247ps min, 112ps max; typ from 0.92 V to 1.8 V
|   rising waveform, R_fixture 50, V_fixture 0: 20-80 % time 96.9ps typ, 156ps min, 90.3ps max; typ from 0 V to 0.877 V
|   falling waveform, R_fixture 50, V_fixture 1.8: 20-80 % time 131ps typ, 184ps min, 111ps max; typ from 1.8 V to 0.92 V
|   falling waveform, R_fixture 50, V_fixture 0: 20-80 % time 84.3ps typ, 89.9ps min, 80.3ps max; typ from 0.877 V to 0 V
[POWER_clamp]
-1.8V     561.4mA    419.3mA    888.8mA
-1.273V   237.6mA    172.5mA    376.8mA
-1.255V   226.8mA    164.4mA    359.5mA
-1.145V   163mA      117mA      257.5mA
-1.055V   112.2mA    80.12mA    175.3mA
-1.036V   102.4mA    73.18mA    159.4mA
-909.1mV  42.63mA    32.42mA    60.25mA
-872.7mV  30.7mA     24.53mA    40.71mA
-818.2mV  19.23mA    16.16mA    24.79mA
-690.9mV  10.22mA    7.161mA    15mA
-418.2mV  1.448mA    900uA      2.08mA
0V        88.35nA    275.1nA    629.8nA
[Pulldown]
-1.8V     -10.43mA   -5.517mA   -13.11mA
-981.8mV  -11.41mA   -9.722mA   -12.37mA
-490.9mV  -9.711mA   -8.814mA   -10.64mA
872.7mV   16.83mA    14.63mA    18.78mA
1.364V    22.97mA    18.03mA    26.66mA
1.8V      24.74mA    18.41mA    30.26mA
2.073V    24.94mA    18.17mA    30.93mA
2.345V    22.38mA    14.57mA    30.58mA
2.618V    16.93mA    9.72mA     25.73mA
2.945V    10.45mA    7.591mA    17.02mA
3.218V    8.772mA    6.671mA    12.07mA
3.6V      8.062mA    5.415mA    9.957mA
[Pullup]
-1.8V     8.781mA    7.249mA    8.735mA
-818.2mV  9.015mA    9.033mA    9.281mA
-381.8mV  7.142mA    7.066mA    7.41mA
490.9mV   -9.498mA   -9.067mA   -9.907mA
1.091V    -20.52mA   -18.86mA   -21.51mA
1.582V    -28.8mA    -25.06mA   -30.36mA
2.018V    -35.22mA   -28.32mA   -37.37mA
2.291V    -37.7mA    -26.74mA   -41.07mA
2.564V    -36.3mA    -22.15mA   -41.87mA
2.727V    -34.31mA   -18.58mA   -40.68mA
3.055V    -29.75mA   -11.79mA   -36.04mA
3.6V      -20.04mA   -7.011mA   -28.93mA
[GND_clamp]
-1.8V     -252.8mA   -247.1mA   -423.2mA
-1.291V   -108.7mA   -90.74mA   -190.6mA
-1.218V   -89.33mA   -70.75mA   -158.7mA
-1.073V   -52.9mA    -36.41mA   -96.88mA
-1.036V   -44.57mA   -29.87mA   -82.18mA
-927.3mV  -23.73mA   -17.18mA   -42.33mA
-854.5mV  -15.56mA   -12.86mA   -23.85mA
-781.8mV  -11.2mA    -9.702mA   -15.35mA
-600mV    -4.319mA   -3.878mA   -5.753mA
-454.5mV  -880.5uA   -1.003mA   -1.003mA
-345.5mV  -65.08uA   -135.9uA   -58.35uA
1.8V      88.35nA    506.3nA    619.7nA
[Ramp]
dV/dt_f 0.52946335/0.13095725n 0.46059468/0.1842488n 0.60590696/0.11075695n
dV/dt_r 0.52987435/97.376733p 0.48274722/0.15735585n 0.58638127/90.174543p
R_load =  50
[Rising Waveform]
R_fixture =  50
V_fixture =  1.8
V_fixture_min =  1.7
V_fixture_max =  1.95
0s        919.8mV    933.7mV    944.2mV
96.5ps    927.3mV    933.4mV    1.305V
133.6ps   1.075V     933.7mV    1.617V
176.2ps   1.233V     934.2mV    1.767V
256.8ps   1.532V     937.1mV    1.881V
291.1ps   1.656V     1.024V     1.905V
414ps     1.766V     1.338V     1.94V
636.7ps   1.796V     1.651V     1.949V
833.1ps   1.799V     1.694V     1.949V
10.02ns   1.8V       1.7V       1.95V
[Rising Waveform]
R_fixture =  50
V_fixture =  0
V_fixture_min =  0
V_fixture_max =  0
0s        0V         0V         0V
102.8ps   -2.476mV   0V         11.12mV
168.9ps   -2.176mV   0V         607.6mV
240.7ps   137.6mV    0V         826.2mV
311.6ps   585.2mV    -5.487mV   889.4mV
354.8ps   720.2mV    -5.215mV   910.2mV
569.4ps   842.9mV    105.5mV    956.5mV
758.1ps   860.7mV    656.3mV    964.7mV
1.01ns    869mV      760mV      967.9mV
10.01ns   877.2mV    799.1mV    971.5mV
[Falling Waveform]
R_fixture =  50
V_fixture =  1.8
V_fixture_min =  1.7
V_fixture_max =  1.95
0s        1.8V       1.7V       1.95V
40ps      1.8V       1.7V       1.93V
126.9ps   1.797V     1.7V       1.328V
183.9ps   1.506V     1.7V       1.121V
252.4ps   1.208V     1.7V       1.02V
328.2ps   1.035V     1.693V     977.7mV
403.8ps   971.1mV    1.456V     961.2mV
592.3ps   932.2mV    1.047V     950.3mV
878.1ps   923.4mV    947.3mV    946mV
10.02ns   919.8mV    933.7mV    943.6mV
[Falling Waveform]
R_fixture =  50
V_fixture =  0
V_fixture_min =  0
V_fixture_max =  0
0s        877.2mV    799.1mV    970.7mV
34ps      877.2mV    799.1mV    926.6mV
86ps      876mV      799mV      391.3mV
140.7ps   729.7mV    799.2mV    166.2mV
228.4ps   174.2mV    799.8mV    63.74mV
332.5ps   55.61mV    743.1mV    28.97mV
425.7ps   29.48mV    217.6mV    16.76mV
551.3ps   16.11mV    39.57mV    8.755mV
951.3ps   3.773mV    9.908mV    0V
10.01ns   0V         0V         0V
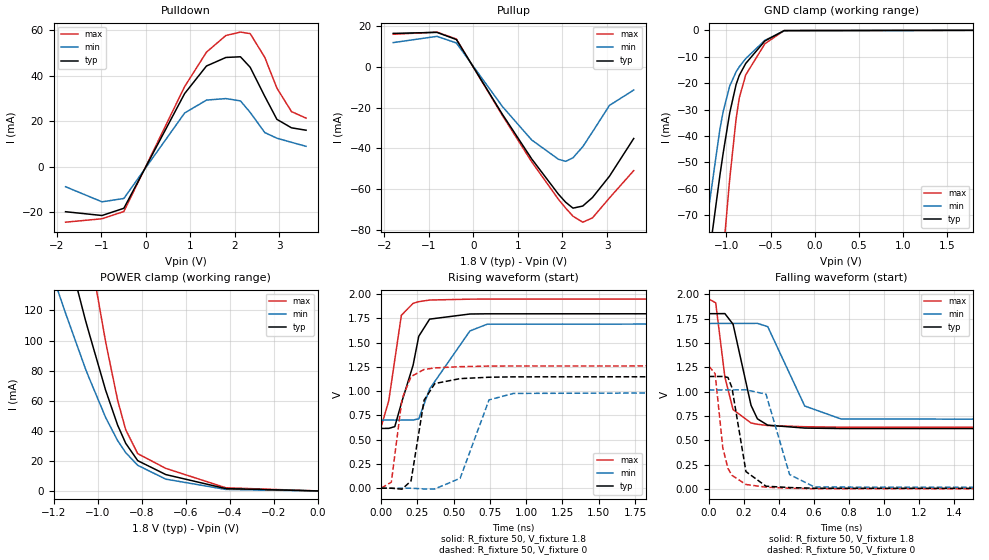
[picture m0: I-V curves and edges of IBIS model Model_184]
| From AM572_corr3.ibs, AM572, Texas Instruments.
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| Model based on original model for SDIO1833PB_H
|   Sub model 33OHMS_1P8
[model]   Model_184
|[Description]  [1.8V-I/O-X-X]
|   , ,
|[Input Load]
|[Output Drive]
|Voltage   1.8V
|Mode   I/O
Model_type   I/O
Polarity   Non-Inverting
Enable   Active-Low
Vinl =   0.58
Vinh =   1.27
Cref =   15.0000pF
Rref =   100.0000M
Vref =   0V
Vmeas =   0.9
C_comp   5p   5p   5p
[Model Spec]
Vinl   0.58   0.58   0.58
Vinh   1.27   1.27   1.27
[Temperature Range]   25   125   -40
[Voltage Range]   1.8   1.7   1.95
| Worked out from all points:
|   slope of the pulldown table from 0 to 0.27 V, typ, clamps not added: 25.1 ohm
|   slope of the pullup table from 0 to 0.27 V, typ, clamps not added: 27.5 ohm
|   GND clamp passes 1 mA (typ) near -0.44 V on its own axis
|   POWER clamp passes 1 mA (typ) near -0.39 V on its own axis
|   rising waveform, R_fixture 50, V_fixture 1.8: 20-80 % time 123ps typ, 252ps min, 71.2ps max; typ from 0.616 V to 1.8 V
|   rising waveform, R_fixture 50, V_fixture 0: 20-80 % time 63.3ps typ, 124ps min, 64ps max; typ from 0 V to 1.16 V
|   falling waveform, R_fixture 50, V_fixture 1.8: 20-80 % time 89ps typ, 149ps min, 65.5ps max; typ from 1.8 V to 0.616 V
|   falling waveform, R_fixture 50, V_fixture 0: 20-80 % time 61.4ps typ, 89ps min, 52.7ps max; typ from 1.16 V to 0 V
[POWER_clamp]
-1.8V     563.3mA    419.9mA    888.8mA
-1.255V   228.3mA    165.3mA    359.5mA
-1.145V   164.4mA    118mA      257.5mA
-1.055V   113.4mA    81.16mA    175.3mA
-1.036V   103.6mA    74.22mA    159.4mA
-963.6mV  66.94mA    48.82mA    99.04mA
-909.1mV  43.68mA    33.4mA     60.25mA
-872.7mV  31.69mA    25.48mA    40.71mA
-818.2mV  20.14mA    17.04mA    24.79mA
-690.9mV  10.88mA    7.829mA    15mA
-418.2mV  1.535mA    990.1uA    2.08mA
0V        129.7nA    360.7nA    948.9nA
[Pulldown]
-1.8V     -19.89mA   -8.889mA   -24.5mA
-981.8mV  -21.56mA   -15.53mA   -22.99mA
-490.9mV  -18.37mA   -14.06mA   -19.8mA
872.7mV   32.1mA     23.54mA    35.17mA
1.364V    44.26mA    29.26mA    50.36mA
1.8V      48.02mA    29.92mA    57.69mA
2.127V    48.32mA    28.89mA    59.19mA
2.345V    43.7mA     23.84mA    58.52mA
2.673V    30.9mA     14.95mA    48.06mA
2.945V    20.77mA    12.47mA    34.53mA
3.273V    17.04mA    10.66mA    24.18mA
3.6V      15.99mA    8.9mA      21.32mA
[Pullup]
-1.8V     16.31mA    11.82mA    15.89mA
-818.2mV  16.8mA     14.86mA    16.95mA
-381.8mV  13.31mA    11.62mA    13.54mA
654.5mV   -23.4mA    -19.56mA   -23.97mA
1.309V    -45.12mA   -35.85mA   -46.53mA
1.909V    -62.39mA   -45.3mA    -64.89mA
2.073V    -66.36mA   -46.32mA   -69.24mA
2.236V    -69.23mA   -44.58mA   -73.18mA
2.455V    -68.21mA   -39.18mA   -76.11mA
2.673V    -64.05mA   -31.96mA   -74.02mA
3.055V    -53.6mA    -18.93mA   -64.24mA
3.6V      -35.14mA   -11.42mA   -50.86mA
[GND_clamp]
-1.8V     -253.4mA   -247.4mA   -424.3mA
-1.291V   -110mA     -91.19mA   -192.7mA
-1.218V   -90.83mA   -71.25mA   -160.7mA
-1.073V   -54.5mA    -37.07mA   -98.78mA
-1.036V   -46.17mA   -30.57mA   -84.05mA
-963.6mV  -31.31mA   -21.12mA   -56.4mA
-890.9mV  -20.5mA    -15.68mA   -33.54mA
-854.5mV  -17.03mA   -13.79mA   -25.52mA
-781.8mV  -12.55mA   -10.7mA    -16.88mA
-563.6mV  -3.985mA   -3.756mA   -5.048mA
-345.5mV  -86.26uA   -192.9uA   -70.11uA
1.8V      129.7nA    593.1nA    940.3nA
[Ramp]
dV/dt_f 0.71155912/89.020681p 0.59931452/0.14953833n  0.7924595/65.623142p
dV/dt_r 0.69958495/63.973555p 0.61604585/0.1252934n 0.76320418/64.338284p
R_load =  50
[Rising Waveform]
R_fixture =  50
V_fixture =  1.8
V_fixture_min =  1.7
V_fixture_max =  1.95
0s        616.4mV    702.5mV    634mV
52.4ps    616.7mV    702.4mV    902.7mV
93.9ps    634.9mV    702.2mV    1.325V
139.1ps   874.5mV    702.6mV    1.783V
220.1ps   1.269V     703.1mV    1.906V
258.9ps   1.566V     715mV      1.923V
333.8ps   1.743V     1.023V     1.94V
611.7ps   1.796V     1.621V     1.949V
730.9ps   1.798V     1.691V     1.95V
10.01ns   1.8V       1.7V       1.95V
[Rising Waveform]
R_fixture =  50
V_fixture =  0
V_fixture_min =  0
V_fixture_max =  0
0s        0V         0V         0V
70ps      0V         0V         62.19mV
143.8ps   -9.916mV   0V         921mV
205.8ps   75.35mV    0V         1.151V
295.8ps   907.5mV    -7.911mV   1.224V
370ps     1.079V     -7.473mV   1.24V
544.4ps   1.13V      102.3mV    1.253V
743.4ps   1.144V     910.4mV    1.259V
912ps     1.148V     977.3mV    1.26V
10.01ns   1.156V     1.018V     1.262V
[Falling Waveform]
R_fixture =  50
V_fixture =  1.8
V_fixture_min =  1.7
V_fixture_max =  1.95
0s        1.8V       1.7V       1.95V
39.1ps    1.8V       1.7V       1.912V
91.5ps    1.801V     1.7V       1.149V
138.3ps   1.691V     1.7V       815.6mV
240.6ps   860.2mV    1.7V       679.4mV
276.8ps   721.8mV    1.701V     665.6mV
335.8ps   656.3mV    1.667V     652.9mV
546.6ps   626.7mV    853mV      640.5mV
754.3ps   621.8mV    719.8mV    635.8mV
10.01ns   616.4mV    702.5mV    633.3mV
[Falling Waveform]
R_fixture =  50
V_fixture =  0
V_fixture_min =  0
V_fixture_max =  0
0s        1.156V     1.018V     1.262V
35.8ps    1.156V     1.018V     1.185V
79.7ps    1.156V     1.018V     421.6mV
109ps     1.146V     1.018V     212.3mV
131.7ps   1.042V     1.018V     142.1mV
211.6ps   180.2mV    1.019V     47.9mV
326ps     30.39mV    974.3mV    20.2mV
460.3ps   16.68mV    150.1mV    9.455mV
602.9ps   9.372mV    21.76mV    4.541mV
10.01ns   0V         0V         0V
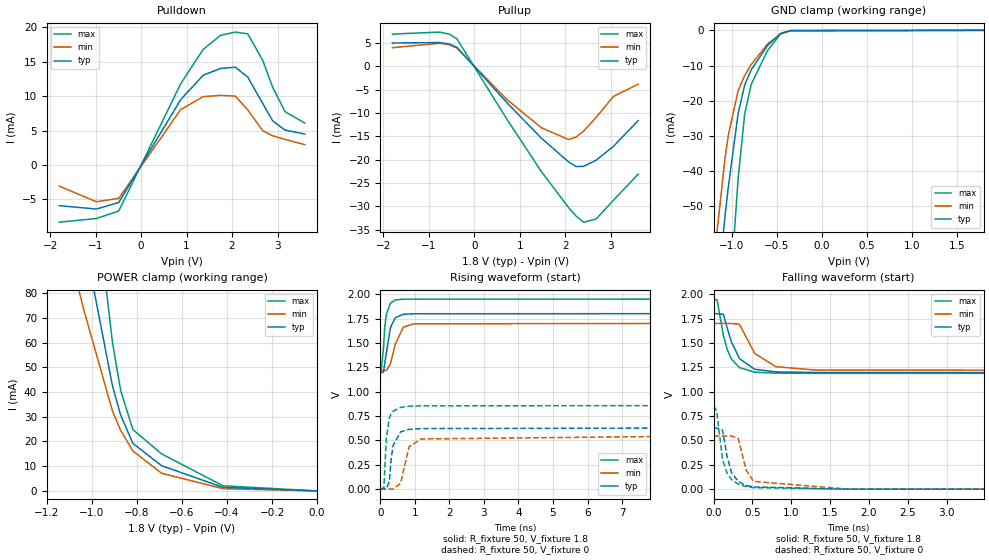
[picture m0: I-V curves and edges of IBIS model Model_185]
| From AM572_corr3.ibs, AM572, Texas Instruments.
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| Model based on original model for SDIO1833PB_H
|   Sub model 100OHMS_1P8
[model]   Model_185
|[Description]  [1.8V-I/O-X-X]
|   , ,
|[Input Load]
|[Output Drive]
|Voltage   1.8V
|Mode   I/O
Model_type   I/O
Polarity   Non-Inverting
Enable   Active-Low
Vinl =   0.58
Vinh =   1.27
Cref =   15.0000pF
Rref =   100.0000M
Vref =   0V
Vmeas =   0.9
C_comp   5p   5p   5p
[Model Spec]
Vinl   0.58   0.58   0.58
Vinh   1.27   1.27   1.27
[Temperature Range]   25   125   -40
[Voltage Range]   1.8   1.7   1.95
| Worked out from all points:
|   slope of the pulldown table from 0 to 0.27 V, typ, clamps not added: 84.6 ohm
|   slope of the pullup table from 0 to 0.27 V, typ, clamps not added: 90.2 ohm
|   GND clamp passes 1 mA (typ) near -0.46 V on its own axis
|   POWER clamp passes 1 mA (typ) near -0.39 V on its own axis
|   rising waveform, R_fixture 50, V_fixture 1.8: 20-80 % time 173ps typ, 262ps min, 120ps max; typ from 1.2 V to 1.8 V
|   rising waveform, R_fixture 50, V_fixture 0: 20-80 % time 142ps typ, 221ps min, 108ps max; typ from 0 V to 0.626 V
|   falling waveform, R_fixture 50, V_fixture 1.8: 20-80 % time 189ps typ, 255ps min, 152ps max; typ from 1.8 V to 1.2 V
|   falling waveform, R_fixture 50, V_fixture 0: 20-80 % time 120ps typ, 130ps min, 115ps max; typ from 0.626 V to 0 V
[POWER_clamp]
-1.8V     561.4mA    419.3mA    888.8mA
-1.273V   237.6mA    172.5mA    376.8mA
-1.255V   226.8mA    164.4mA    359.5mA
-1.145V   163mA      117mA      257.5mA
-1.055V   112.2mA    80.12mA    175.3mA
-1.036V   102.4mA    73.18mA    159.4mA
-909.1mV  42.63mA    32.42mA    60.25mA
-872.7mV  30.7mA     24.53mA    40.71mA
-818.2mV  19.23mA    16.16mA    24.79mA
-690.9mV  10.22mA    7.161mA    15mA
-418.2mV  1.448mA    900uA      2.08mA
0V        88.35nA    275.1nA    629.8nA
[Pulldown]
-1.8V     -5.927mA   -3.084mA   -8.331mA
-981.8mV  -6.419mA   -5.362mA   -7.794mA
-490.9mV  -5.465mA   -4.858mA   -6.7mA
872.7mV   9.517mA    8.065mA    11.83mA
1.364V    13.04mA    9.934mA    16.8mA
1.745V    14.04mA    10.13mA    18.86mA
2.073V    14.22mA    10.01mA    19.33mA
2.345V    12.78mA    8.021mA    19.07mA
2.673V    8.963mA    4.982mA    15.24mA
2.891V    6.423mA    4.243mA    11.34mA
3.164V    5.075mA    3.72mA     7.752mA
3.6V      4.496mA    2.944mA    6.092mA
[Pullup]
-1.8V     5mA        4.01mA     6.923mA
-763.6mV  5.116mA    4.954mA    7.351mA
-545.5mV  4.781mA    4.64mA     6.89mA
-381.8mV  4.057mA    3.887mA    5.865mA
709.1mV   -7.729mA   -7.064mA   -11.25mA
1.473V    -15.4mA    -13.17mA   -22.57mA
2.073V    -20.51mA   -15.71mA   -30.31mA
2.236V    -21.47mA   -15.16mA   -32.11mA
2.4V      -21.45mA   -13.89mA   -33.42mA
2.673V    -20.15mA   -10.99mA   -32.77mA
3.055V    -17.17mA   -6.461mA   -28.73mA
3.6V      -11.65mA   -3.809mA   -23.13mA
[GND_clamp]
-1.8V     -252.8mA   -247.1mA   -423.2mA
-1.291V   -108.7mA   -90.74mA   -190.6mA
-1.218V   -89.33mA   -70.75mA   -158.7mA
-1.073V   -52.9mA    -36.41mA   -96.88mA
-1.036V   -44.57mA   -29.87mA   -82.18mA
-927.3mV  -23.73mA   -17.18mA   -42.33mA
-854.5mV  -15.56mA   -12.86mA   -23.85mA
-781.8mV  -11.2mA    -9.702mA   -15.35mA
-600mV    -4.319mA   -3.878mA   -5.753mA
-454.5mV  -880.5uA   -1.003mA   -1.003mA
-345.5mV  -65.08uA   -135.9uA   -58.35uA
1.8V      88.35nA    506.3nA    619.7nA
[Ramp]
dV/dt_f 0.36344474/0.1886875n 0.29034501/0.25518667n 0.46008109/0.15210703n
dV/dt_r 0.37751083/0.14151511n  0.3289809/0.2209787n 0.51572755/0.10798331n
R_load =  50
[Rising Waveform]
R_fixture =  50
V_fixture =  1.8
V_fixture_min =  1.7
V_fixture_max =  1.95
0s        1.196V     1.217V     1.187V
22.8ps    1.195V     1.217V     1.199V
97.2ps    1.201V     1.217V     1.456V
130.8ps   1.29V      1.217V     1.664V
180.4ps   1.403V     1.217V     1.796V
295.7ps   1.656V     1.284V     1.908V
434.1ps   1.758V     1.485V     1.941V
667ps     1.794V     1.661V     1.949V
977.7ps   1.799V     1.696V     1.949V
10.01ns   1.8V       1.7V       1.95V
[Rising Waveform]
R_fixture =  50
V_fixture =  0
V_fixture_min =  0
V_fixture_max =  0
0s        0V         0V         0V
104.4ps   0V         0V         9.232mV
175.5ps   -2.848mV   0V         511.5mV
264.9ps   77.07mV    0V         729.5mV
315.3ps   304.4mV    -2.901mV   772.6mV
373.5ps   445.2mV    -2.635mV   797.6mV
588.8ps   585.8mV    57.74mV    837.1mV
837.3ps   611.1mV    433.6mV    849.5mV
1.19ns    619.3mV    513.1mV    853.2mV
10.01ns   626mV      545.4mV    856mV
[Falling Waveform]
R_fixture =  50
V_fixture =  1.8
V_fixture_min =  1.7
V_fixture_max =  1.95
0s        1.8V       1.7V       1.95V
45.5ps    1.8V       1.7V       1.942V
128.1ps   1.793V     1.7V       1.573V
175.9ps   1.654V     1.7V       1.434V
228.2ps   1.515V     1.7V       1.338V
333.7ps   1.339V     1.691V     1.247V
530ps     1.23V      1.392V     1.2V
799.6ps   1.203V     1.257V     1.19V
1.305ns   1.197V     1.222V     1.188V
10.01ns   1.196V     1.217V     1.187V
[Falling Waveform]
R_fixture =  50
V_fixture =  0
V_fixture_min =  0
V_fixture_max =  0
0s        626mV      545.4mV    856mV
39.8ps    626.1mV    545.4mV    803.7mV
116.4ps   606.4mV    545.4mV    303mV
172.1ps   343.8mV    545.7mV    168.2mV
231.3ps   170.9mV    545.5mV    98.56mV
319.3ps   78.26mV    518.3mV    50.28mV
420.7ps   38.88mV    195mV      26.79mV
516.2ps   23.12mV    79.53mV    15.38mV
1.739ns   0V         0V         0V
10.01ns   0V         0V         0V
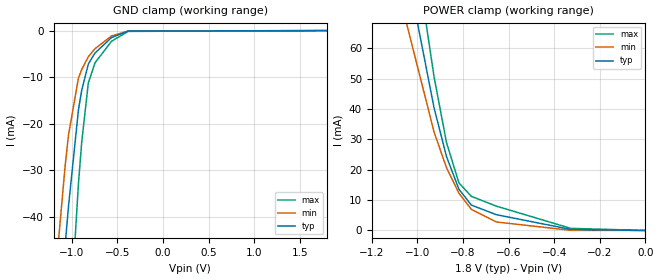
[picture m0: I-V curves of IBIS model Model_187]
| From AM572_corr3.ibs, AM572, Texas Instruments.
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| Model based on original model for IQ1833DVTCKPBFBP18LL_SSCEV
|   Sub model IQ1833_V_5P_1P8
[model]   Model_187
|[Description]  [1.8V-INPUT-X-1.8V MODE, IND, 5 PERCENT%]
|   1.8V MODE, ,IND,5 PERCENT%
|[Input Load]
|[Output Drive] 1.8V MODE
|Voltage   1.8V
|Mode   INPUT
Model_type   Input
Polarity   Non-Inverting
Vinl =   0.306
Vinh =   1.206
C_comp   628.403f   564.553f   692.253f
[Model Spec]
Vinl   0.306   0.2907   0.3213
Vinh   1.206   1.1457   1.2663
D_overshoot_ampl_h 0.36 0.36 0.36
D_overshoot_ampl_l 0.36 0.36 0.36
D_overshoot_area_h 0.33n 0.33n 0.33n
D_overshoot_area_l 0.33n 0.33n 0.33n
D_overshoot_high 2.16 2.16 2.16
D_overshoot_low -0.36 -0.36 -0.36
D_overshoot_time 1n 1n 1n
S_overshoot_high 1.8 1.8 1.8
S_overshoot_low 0 0 0
[Temperature Range]   25   125   -40
[Voltage Range]   1.8   1.71   1.89
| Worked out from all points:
|   GND clamp passes 1 mA (typ) near -0.52 V on its own axis
|   POWER clamp passes 1 mA (typ) near -0.39 V on its own axis
[POWER_clamp]
-1.8V     435.3mA    358.7mA    550.4mA
-1.182V   145.1mA    115.2mA    186mA
-1.164V   136.9mA    108.6mA    175.7mA
-1.109V   112.9mA    89.05mA    145.1mA
-1.055V   89.59mA    70.36mA    115.1mA
-927.3mV  40.44mA    32.49mA    50.68mA
-872.7mV  24.38mA    20.7mA     29mA
-818.2mV  13.61mA    12.29mA    15.69mA
-763.6mV  8.369mA    6.958mA    11.24mA
-654.5mV  5.219mA    2.811mA    8.041mA
-327.3mV  349.6uA    49.46uA    691.6uA
0V        2.268uA    902.8nA    4.994uA
[GND_clamp]
-1.8V     -241.7mA   -231.6mA   -367.4mA
-1.255V   -91.62mA   -71.7mA    -149.9mA
-1.182V   -72.85mA   -53.19mA   -122mA
-1.073V   -46.19mA   -29.16mA   -81.51mA
-1.036V   -37.83mA   -22.49mA   -68.45mA
-927.3mV  -17.13mA   -10.25mA   -33.06mA
-890.9mV  -12.84mA   -8.372mA   -24.01mA
-818.2mV  -7.187mA   -5.618mA   -11.22mA
-745.5mV  -4.828mA   -3.893mA   -6.943mA
-563.6mV  -1.493mA   -1.147mA   -2.288mA
-381.8mV  -98.54uA   -88.42uA   -167.6uA
1.8V      2.268uA    1.016uA    4.793uA
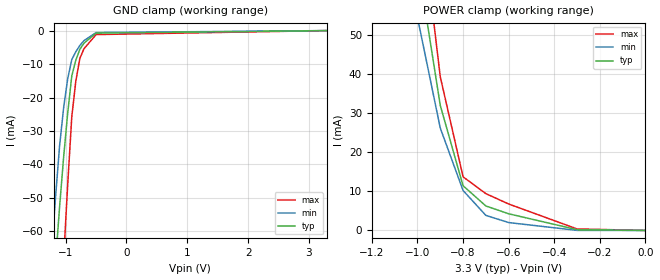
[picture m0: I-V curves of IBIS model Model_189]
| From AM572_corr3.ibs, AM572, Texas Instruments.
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| Model based on original model for IQ1833DVTCKPBFBP18LL_SSCEV
|   Sub model IQ1833_V_5P_3P3
[model]   Model_189
|[Description]  [3.3V-INPUT-X-3.3V MODE, IND, 5 PERCENT%]
|   3.3V MODE, ,IND,5 PERCENT%
|[Input Load]
|[Output Drive] 3.3V MODE
|Voltage   3.3V
|Mode   INPUT
Model_type   Input
Polarity   Non-Inverting
Vinl =   0.561
Vinh =   2.211
C_comp   469.037f   410.952f   527.122f
[Model Spec]
Vinl   0.561   0.53295   0.58905
Vinh   2.211   2.10045   2.32155
D_overshoot_ampl_h 0.66 0.66 0.66
D_overshoot_ampl_l 0.66 0.66 0.66
D_overshoot_area_h 0.33n 0.33n 0.33n
D_overshoot_area_l 0.33n 0.33n 0.33n
D_overshoot_high 3.96 3.96 3.96
D_overshoot_low -0.66 -0.66 -0.66
D_overshoot_time 1n 1n 1n
S_overshoot_high 3.3 3.3 3.3
S_overshoot_low 0 0 0
[Temperature Range]   25   125   -40
[Voltage Range]   3.3   3.135   3.465
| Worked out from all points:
|   GND clamp passes 1 mA (typ) near -0.52 V on its own axis
|   POWER clamp passes 1 mA (typ) near -0.39 V on its own axis
[POWER_clamp]
-3.3V     1.165A     1.199A     1.459A
-1.2V     153.4mA    122mA      196.7mA
-1.167V   138.6mA    109.9mA    177.9mA
-1.1V     109.1mA    85.82mA    140.3mA
-1.067V   95.17mA    74.81mA    122.3mA
-1.033V   81.28mA    63.8mA     104.4mA
-900mV    31.99mA    26.2mA     39.32mA
-800mV    11.44mA    10.23mA    13.72mA
-700mV    6.266mA    3.859mA    9.425mA
-600mV    4.272mA    2.025mA    6.774mA
-300mV    202.9uA    25.89uA    394.5uA
0V        3.057uA    1.331uA    6.945uA
[GND_clamp]
-3.3V     -675.1mA   -831.9mA   -985.9mA
-1.233V   -86.22mA   -66.38mA   -141.8mA
-1.167V   -69.2mA    -49.86mA   -116.5mA
-1.1V     -52.6mA    -34.38mA   -91.44mA
-1.033V   -37.65mA   -22.95mA   -67.83mA
-966.7mV  -24.63mA   -14.38mA   -45.95mA
-900mV    -13.56mA   -8.682mA   -25.81mA
-833.3mV  -8.843mA   -6.325mA   -15.09mA
-766.7mV  -5.582mA   -4.435mA   -8.297mA
-700mV    -3.779mA   -3.012mA   -5.442mA
-500mV    -752.8uA   -575.1uA   -1.188mA
3.3V      3.057uA    1.928uA    6.853uA
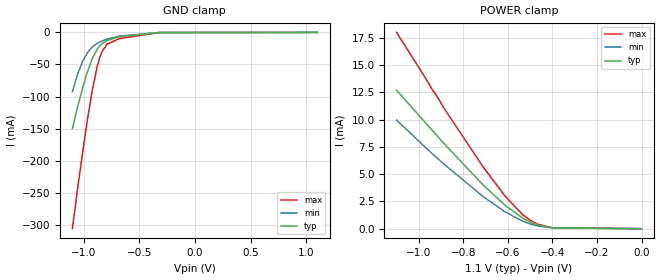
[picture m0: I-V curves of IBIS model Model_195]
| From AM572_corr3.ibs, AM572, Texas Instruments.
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| Model based on original model for USB3_PCIEGEN1_PCIEGEN2_TX
|   Sub model PCIEGEN1_TX_FS_NO_DEEMPHASIS_0p6v
[model]   Model_195
|[Description]  [1.1V-3-STATE-X-X]
|   , ,
|[Input Load]
|[Output Drive]
|Voltage   1.1V
|Mode   3-STATE
Model_type   3-state
Polarity   Non-Inverting
Enable   Active-Low
Cref =   15.0000pF
Rref =   100.0000M
Vref =   0V
Vmeas =   0.55
C_comp   0.4p   0.4p   0.4p
[Temperature Range]   25   125   -40
[Voltage Range]   1.1   1.078   1.122
[Driver Schedule]
DRIVER_LVL0   NA   1ps   NA   1ps
DRIVER_LVL1   NA   1ps   NA   1ps
DRIVER_LVL2   NA   1ps   NA   1ps
DRIVER_LVL3   0ps   NA   0ps   NA
DRIVER_LVL4   NA   1ps   NA   1ps
DRIVER_LVL5   0ps   NA   0ps   NA
DRIVER_LVL6   0ps   NA   0ps   NA
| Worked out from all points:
|   GND clamp passes 1 mA (typ) near -0.41 V on its own axis
|   POWER clamp passes 1 mA (typ) near -0.54 V on its own axis
[POWER_clamp]
-1.1V     12.7mA     9.96mA     18mA
-966.7mV  9.63mA     7.38mA     13.7mA
-944.4mV  9.12mA     6.96mA     12.9mA
-911.1mV  8.36mA     6.35mA     11.9mA
-888.9mV  7.85mA     5.95mA     11.1mA
-711.1mV  4mA        2.94mA     5.66mA
-611.1mV  2.12mA     1.52mA     2.94mA
-533.3mV  961uA      684uA      1.27mA
-500mV    598uA      429uA      765uA
-466.7mV  333uA      246uA      410uA
-400mV    69.4uA     61.7uA     78uA
0V        120nA      895nA      288nA
[Pulldown]
-1.1V     0A         0A         0A
-1.067V   0A         0A         0A
-1.033V   0A         0A         0A
2.2V      0A         0A         0A
[Pullup]
-1.1V     0A         0A         0A
-1.067V   0A         0A         0A
-1.033V   0A         0A         0A
2.2V      0A         0A         0A
[GND_clamp]
-1.1V     -150mA     -92.3mA    -306mA
-1.056V   -118mA     -66.6mA    -247mA
-1.011V   -88.7mA    -46.3mA    -191mA
-966.7mV  -62.4mA    -32mA      -138mA
-922.2mV  -41.1mA    -22.9mA    -91.2mA
-877.8mV  -26.3mA    -17.2mA    -53.6mA
-855.6mV  -21.3mA    -15.2mA    -39.8mA
-833.3mV  -17.6mA    -13.4mA    -29.7mA
-788.9mV  -12.7mA    -10.5mA    -18.3mA
-677.8mV  -6.75mA    -5.74mA    -9.67mA
-322.2mV  -147uA     -254uA     -266uA
1.1V      120nA      909nA      272nA
[Ramp]
dV/dt_f 55m/24.496914p  54m/31.970054p  56m/18.193627p
dV/dt_r 55m/24.267571p  54m/32.968711p  56m/17.881799p
R_load =  50
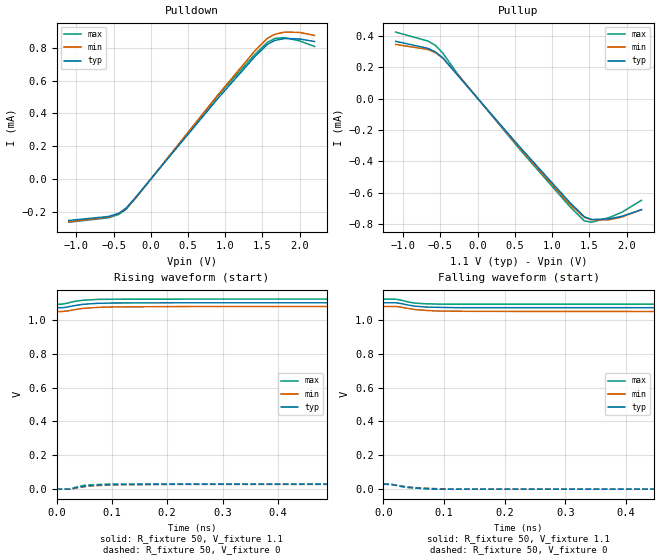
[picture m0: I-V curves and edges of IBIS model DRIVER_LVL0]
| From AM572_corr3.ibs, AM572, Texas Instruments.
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| Model based on original model for USB3_PCIEGEN1_PCIEGEN2_TX
|   Sub model DRIVER_LVL0
[model]   DRIVER_LVL0
|[Description]  [1.1V-3-STATE-X-X]
|   , ,
|[Input Load]
|[Output Drive]
|Voltage   1.1V
|Mode   3-STATE
Model_type   3-state
Polarity   Non-Inverting
Enable   Active-Low
Cref =   15.0000pF
Rref =   100.0000M
Vref =   0V
Vmeas =   0.55
C_comp   0   0   0
[Temperature Range]   25   125   -40
[Voltage Range]   1.1   1.078   1.122
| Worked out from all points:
|   slope of the pulldown table from 0 to 0.165 V, typ, clamps not added: 1.8 kohm
|   slope of the pullup table from 0 to 0.165 V, typ, clamps not added: 1.82 kohm
[Pulldown]
-1.1V     -254.4uA   -262.2uA   -264.9uA
-566.7mV  -230.1uA   -233.8uA   -237.9uA
-433.3mV  -211.3uA   -212.9uA   -218.1uA
-333.3mV  -180.2uA   -182.7uA   -187.8uA
-200mV    -111.1uA   -115.3uA   -116.1uA
900mV     490.6uA    512.1uA    506.8uA
1.4V      748.5uA    783.5uA    762uA
1.567V    822.3uA    859.2uA    834.6uA
1.667V    846.5uA    884uA      858.7uA
1.8V      857.9uA    897.2uA    863uA
2V        855uA      895.1uA    843.2uA
2.2V      839.6uA    876.8uA    809.1uA
[Pullup]
-1.1V     365uA      345.1uA    423.8uA
-666.7mV  319.9uA    312.8uA    366.6uA
-566.7mV  297.4uA    292uA      339.2uA
-466.7mV  259.3uA    257.4uA    289.4uA
-266.7mV  147.2uA    151.4uA    155.1uA
566.7mV   -309.3uA   -317.4uA   -324.6uA
1.233V    -660.5uA   -673uA     -686.8uA
1.433V    -754.4uA   -758.2uA   -780.9uA
1.533V    -772.2uA   -774.8uA   -789.1uA
1.767V    -767.6uA   -773.5uA   -759.5uA
1.933V    -752.1uA   -756.7uA   -726.6uA
2.2V      -709.4uA   -708.9uA   -649.5uA
[Ramp]
dV/dt_f 17.549396m/31.87396p   17.88822m/39.553068p 18.450456m/25.257682p
dV/dt_r 17.452192m/32.777039p 17.394607m/41.861234p 18.628416m/24.811347p
R_load =  50
[Rising Waveform]
R_fixture =  50
V_fixture =  1.1
V_fixture_min =  1.078
V_fixture_max =  1.122
0s        1.071V     1.048V     1.092V
8.4ps     1.071V     1.048V     1.092V
13.4ps    1.072V     1.05V      1.094V
20.8ps    1.076V     1.052V     1.099V
31.9ps    1.083V     1.059V     1.108V
47.8ps    1.091V     1.067V     1.115V
74.7ps    1.097V     1.073V     1.12V
108.1ps   1.099V     1.076V     1.121V
244.2ps   1.1V       1.078V     1.122V
1.014ns   1.1V       1.078V     1.122V
[Rising Waveform]
R_fixture =  50
V_fixture =  0
V_fixture_min =  0
V_fixture_max =  0
0s        0V         0V         0V
22.7ps    0V         0V         0V
25.6ps    0V         0V         3.108mV
29.2ps    3.559mV    0V         6.18mV
29.8ps    3.946mV    2.152mV    6.797mV
42.1ps    13.26mV    9.932mV    18.54mV
56.7ps    20.64mV    17.47mV    25.53mV
98.4ps    27.34mV    25.64mV    30.16mV
208.8ps   28.85mV    28.33mV    30.68mV
1.012ns   28.85mV    28.89mV    30.63mV
[Falling Waveform]
R_fixture =  50
V_fixture =  1.1
V_fixture_min =  1.078
V_fixture_max =  1.122
0s        1.1V       1.078V     1.122V
20.9ps    1.1V       1.078V     1.121V
30ps      1.095V     1.074V     1.115V
41.7ps    1.086V     1.066V     1.104V
52.5ps    1.08V      1.06V      1.098V
70.4ps    1.075V     1.055V     1.094V
92.3ps    1.073V     1.051V     1.092V
126.7ps   1.071V     1.05V      1.092V
222.8ps   1.071V     1.049V     1.092V
1.014ns   1.071V     1.048V     1.092V
[Falling Waveform]
R_fixture =  50
V_fixture =  0
V_fixture_min =  0
V_fixture_max =  0
0s        28.85mV    28.89mV    30.63mV
6ps       28.85mV    28.89mV    30.63mV
14.3ps    27.04mV    26.94mV    27.82mV
29.3ps    17.75mV    18.61mV    15.4mV
41.1ps    11.35mV    12.5mV     9.179mV
61.9ps    5.077mV    6.409mV    3.903mV
82.3ps    2.331mV    3.541mV    0V
90.5ps    0V         2.907mV    0V
107.4ps   0V         0V         0V
1.012ns   0V         0V         0V
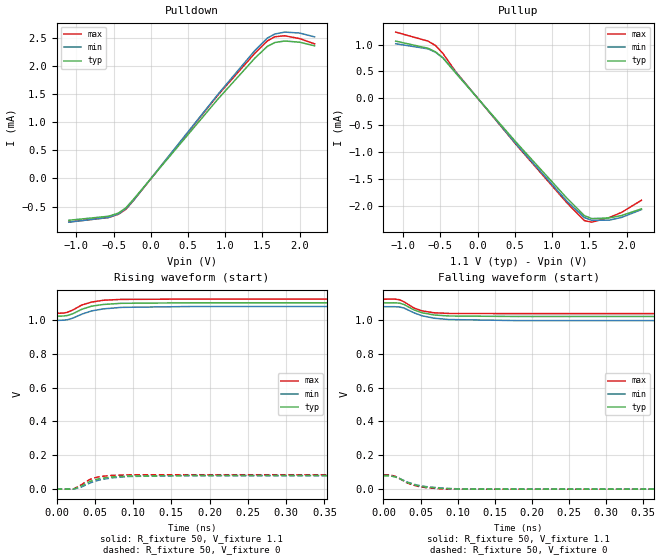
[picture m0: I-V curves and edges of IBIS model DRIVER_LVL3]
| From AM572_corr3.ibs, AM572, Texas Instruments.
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| Model based on original model for USB3_PCIEGEN1_PCIEGEN2_TX
|   Sub model DRIVER_LVL3
[model]   DRIVER_LVL3
|[Description]  [1.1V-3-STATE-X-X]
|   , ,
|[Input Load]
|[Output Drive]
|Voltage   1.1V
|Mode   3-STATE
Model_type   3-state
Polarity   Non-Inverting
Enable   Active-Low
Cref =   15.0000pF
Rref =   100.0000M
Vref =   0V
Vmeas =   0.55
C_comp   0   0   0
[Temperature Range]   25   125   -40
[Voltage Range]   1.1   1.078   1.122
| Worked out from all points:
|   slope of the pulldown table from 0 to 0.165 V, typ, clamps not added: 628 ohm
|   slope of the pullup table from 0 to 0.165 V, typ, clamps not added: 628 ohm
|   rising waveform, R_fixture 50, V_fixture 1.1: 20-80 % time 29.1ps typ, 33.8ps min, 26.1ps max; typ from 1.02 V to 1.1 V
|   rising waveform, R_fixture 50, V_fixture 0: 20-80 % time 26.3ps typ, 33.6ps min, 21.2ps max; typ from 0 V to 0.08 V
|   falling waveform, R_fixture 50, V_fixture 1.1: 20-80 % time 26.4ps typ, 32.3ps min, 22ps max; typ from 1.1 V to 1.02 V
|   falling waveform, R_fixture 50, V_fixture 0: 20-80 % time 29.6ps typ, 34.3ps min, 26.2ps max; typ from 0.08 V to 0 V
[Pulldown]
-1.1V     -742.4uA   -776.3uA   -773uA
-566.7mV  -670.9uA   -692.3uA   -693.9uA
-433.3mV  -614.5uA   -629.2uA   -636.1uA
-333.3mV  -521.1uA   -537.3uA   -547.3uA
-233.3mV  -372.5uA   -391.4uA   -393.8uA
900mV     1.405mA    1.489mA    1.476mA
1.4V      2.137mA    2.273mA    2.225mA
1.567V    2.345mA    2.492mA    2.441mA
1.667V    2.412mA    2.563mA    2.515mA
1.8V      2.439mA    2.597mA    2.532mA
2V        2.417mA    2.58mA     2.481mA
2.2V      2.354mA    2.512mA    2.388mA
[Pullup]
-1.1V     1.066mA    1.017mA    1.234mA
-666.7mV  933.2uA    922.1uA    1.066mA
-566.7mV  866.5uA    860.1uA    985.3uA
-466.7mV  753.4uA    756.5uA    838.4uA
-300mV    480.2uA    498.9uA    507.5uA
533.3mV   -843.4uA   -875.2uA   -888.3uA
1.2V      -1.861mA   -1.918mA   -1.947mA
1.433V    -2.184mA   -2.221mA   -2.277mA
1.533V    -2.24mA    -2.272mA   -2.307mA
1.767V    -2.228mA   -2.269mA   -2.22mA
1.933V    -2.183mA   -2.218mA   -2.125mA
2.2V      -2.058mA   -2.072mA   -1.898mA
[Ramp]
dV/dt_f 48.193485m/26.638344p 49.562247m/32.424333p 51.588263m/22.399251p
dV/dt_r 48.393015m/26.577244p  48.55925m/33.780751p 51.886695m/21.522928p
R_load =  50
[Rising Waveform]
R_fixture =  50
V_fixture =  1.1
V_fixture_min =  1.078
V_fixture_max =  1.122
0s        1.021V     995.8mV    1.038V
9.3ps     1.022V     997.3mV    1.039V
14.3ps    1.025V     1V         1.044V
21.6ps    1.036V     1.01V      1.058V
33.1ps    1.062V     1.033V     1.087V
45.8ps    1.08V      1.052V     1.104V
61ps      1.09V      1.064V     1.115V
84.8ps    1.097V     1.073V     1.12V
176.6ps   1.1V       1.078V     1.122V
1.012ns   1.1V       1.078V     1.122V
[Rising Waveform]
R_fixture =  50
V_fixture =  0
V_fixture_min =  0
V_fixture_max =  0
0s        0V         0V         0V
21.6ps    0V         0V         0V
30.4ps    13.88mV    8.171mV    20.81mV
43ps      44.03mV    34.72mV    56.1mV
48.1ps    52.88mV    43.83mV    65.16mV
56.6ps    62.77mV    54.81mV    74.27mV
71.5ps    72.2mV     66.56mV    81.38mV
94.8ps    77.86mV    75.03mV    84.63mV
174ps     79.87mV    80.47mV    85.08mV
1.013ns   79.63mV    80.51mV    84.85mV
[Falling Waveform]
R_fixture =  50
V_fixture =  1.1
V_fixture_min =  1.078
V_fixture_max =  1.122
0s        1.1V       1.078V     1.122V
14.6ps    1.101V     1.078V     1.123V
21.8ps    1.099V     1.076V     1.119V
27.7ps    1.091V     1.07V      1.107V
41.1ps    1.059V     1.042V     1.07V
52.1ps    1.042V     1.024V     1.053V
68.3ps    1.029V     1.01V      1.042V
88.2ps    1.023V     1.002V     1.038V
182ps     1.02V      995.7mV    1.037V
1.012ns   1.021V     995.8mV    1.037V
[Falling Waveform]
R_fixture =  50
V_fixture =  0
V_fixture_min =  0
V_fixture_max =  0
0s        79.63mV    80.51mV    84.84mV
6.8ps     79.63mV    80.51mV    84.84mV
15.1ps    73.87mV    73.66mV    77.48mV
20.3ps    65.66mV    66mV       66.85mV
31.8ps    39.8mV     42.68mV    36.76mV
44.7ps    21.43mV    24.95mV    18.21mV
57.7ps    11.28mV    14.82mV    8.683mV
83.3ps    3.118mV    5.197mV    0V
110.7ps   0V         0V         0V
1.013ns   0V         0V         0V
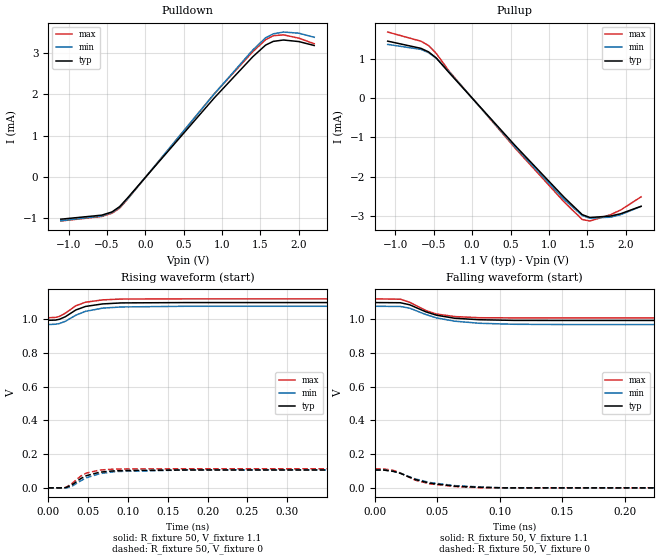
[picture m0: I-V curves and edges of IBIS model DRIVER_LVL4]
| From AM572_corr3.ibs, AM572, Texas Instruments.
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| Model based on original model for USB3_PCIEGEN1_PCIEGEN2_TX
|   Sub model DRIVER_LVL4
[model]   DRIVER_LVL4
|[Description]  [1.1V-3-STATE-X-X]
|   , ,
|[Input Load]
|[Output Drive]
|Voltage   1.1V
|Mode   3-STATE
Model_type   3-state
Polarity   Non-Inverting
Enable   Active-Low
Cref =   15.0000pF
Rref =   100.0000M
Vref =   0V
Vmeas =   0.55
C_comp   0   0   0
[Temperature Range]   25   125   -40
[Voltage Range]   1.1   1.078   1.122
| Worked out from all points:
|   slope of the pulldown table from 0 to 0.165 V, typ, clamps not added: 459 ohm
|   slope of the pullup table from 0 to 0.165 V, typ, clamps not added: 460 ohm
|   rising waveform, R_fixture 50, V_fixture 1.1: 20-80 % time 27.7ps typ, 31.6ps min, 24.9ps max; typ from 0.995 V to 1.1 V
|   rising waveform, R_fixture 50, V_fixture 0: 20-80 % time 25.1ps typ, 31.2ps min, 20.4ps max; typ from 0 V to 0.106 V
|   falling waveform, R_fixture 50, V_fixture 1.1: 20-80 % time 25ps typ, 30ps min, 21.2ps max; typ from 1.1 V to 0.994 V
|   falling waveform, R_fixture 50, V_fixture 0: 20-80 % time 28.2ps typ, 32.1ps min, 25.2ps max; typ from 0.106 V to 0 V
[Pulldown]
-1.1V     -1.018mA   -1.055mA   -1.062mA
-566.7mV  -920.1uA   -941.1uA   -952.9uA
-433.3mV  -842.3uA   -855uA     -873.1uA
-333.3mV  -713.3uA   -729.3uA   -750.4uA
-233.3mV  -509.4uA   -530.7uA   -539.5uA
900mV     1.919mA    2.017mA    2.019mA
1.4V      2.912mA    3.075mA    3.034mA
1.567V    3.194mA    3.371mA    3.324mA
1.667V    3.284mA    3.466mA    3.422mA
1.8V      3.317mA    3.51mA     3.441mA
2V        3.279mA    3.482mA    3.362mA
2.2V      3.184mA    3.383mA    3.227mA
[Pullup]
-1.1V     1.462mA    1.379mA    1.695mA
-666.7mV  1.278mA    1.251mA    1.46mA
-566.7mV  1.186mA    1.166mA    1.349mA
-466.7mV  1.03mA     1.025mA    1.146mA
-300mV    655.7uA    675.2uA    693.9uA
566.7mV   -1.222mA   -1.256mA   -1.288mA
1.2V      -2.534mA   -2.589mA   -2.653mA
1.433V    -2.972mA   -2.995mA   -3.097mA
1.533V    -3.046mA   -3.063mA   -3.136mA
1.8V      -3.01mA    -3.038mA   -2.976mA
1.933V    -2.95mA    -2.973mA   -2.856mA
2.2V      -2.759mA   -2.763mA   -2.518mA
[Ramp]
dV/dt_f 64.356672m/25.404952p 65.459373m/30.095256p 68.840661m/21.605958p
dV/dt_r 64.455818m/25.510027p 64.028124m/31.29472p  69.100295m/20.803061p
R_load =  50
[Rising Waveform]
R_fixture =  50
V_fixture =  1.1
V_fixture_min =  1.078
V_fixture_max =  1.122
0s        994.8mV    969.6mV    1.01V
9.3ps     996.1mV    971.5mV    1.012V
14.3ps    1.001V     975.8mV    1.018V
21.6ps    1.016V     988.8mV    1.037V
34.7ps    1.056V     1.025V     1.081V
46.9ps    1.077V     1.048V     1.102V
68.4ps    1.092V     1.067V     1.116V
91.9ps    1.098V     1.074V     1.121V
172.2ps   1.1V       1.078V     1.122V
1.012ns   1.1V       1.078V     1.122V
[Rising Waveform]
R_fixture =  50
V_fixture =  0
V_fixture_min =  0
V_fixture_max =  0
0s        0V         0V         0V
20.3ps    0V         0V         0V
23.5ps    3.541mV    0V         5.807mV
30.5ps    19.34mV    11.21mV    28.26mV
41.1ps    55.47mV    42.45mV    70.56mV
48.1ps    72.38mV    59.97mV    88.11mV
64.9ps    93.05mV    84.44mV    105.8mV
85ps      102.1mV    97.11mV    111.9mV
174.9ps   106.3mV    106.2mV    113.1mV
1.013ns   105.8mV    106.1mV    112.8mV
[Falling Waveform]
R_fixture =  50
V_fixture =  1.1
V_fixture_min =  1.078
V_fixture_max =  1.122
0s        1.1V       1.078V     1.122V
20.3ps    1.099V     1.077V     1.12V
27.7ps    1.087V     1.067V     1.102V
40.7ps    1.045V     1.029V     1.053V
49.2ps    1.025V     1.009V     1.032V
63.7ps    1.007V     989.5mV    1.017V
83.6ps    998.1mV    977.1mV    1.01V
111.6ps   994.2mV    971.1mV    1.009V
157.1ps   993.8mV    969.4mV    1.009V
1.012ns   994.4mV    969.6mV    1.009V
[Falling Waveform]
R_fixture =  50
V_fixture =  0
V_fixture_min =  0
V_fixture_max =  0
0s        105.8mV    106.1mV    112.8mV
6.8ps     105.8mV    106.1mV    112.8mV
15.1ps    97.7mV     96.8mV     102.8mV
20.3ps    86.23mV    86.34mV    88.31mV
32ps      49.95mV    53.85mV    46.34mV
43.7ps    27.68mV    31.82mV    24.11mV
64ps      9.991mV    12.87mV    7.458mV
85.1ps    3.155mV    4.92mV     0V
103.4ps   0V         0V         0V
1.013ns   0V         0V         0V
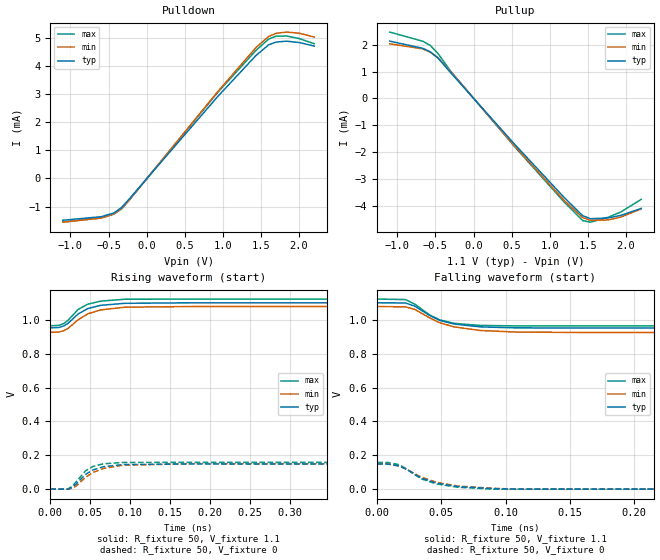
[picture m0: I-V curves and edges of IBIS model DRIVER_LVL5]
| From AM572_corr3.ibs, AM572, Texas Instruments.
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| Model based on original model for USB3_PCIEGEN1_PCIEGEN2_TX
|   Sub model DRIVER_LVL5
[model]   DRIVER_LVL5
|[Description]  [1.1V-3-STATE-X-X]
|   , ,
|[Input Load]
|[Output Drive]
|Voltage   1.1V
|Mode   3-STATE
Model_type   3-state
Polarity   Non-Inverting
Enable   Active-Low
Cref =   15.0000pF
Rref =   100.0000M
Vref =   0V
Vmeas =   0.55
C_comp   0   0   0
[Temperature Range]   25   125   -40
[Voltage Range]   1.1   1.078   1.122
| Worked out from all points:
|   slope of the pulldown table from 0 to 0.165 V, typ, clamps not added: 314 ohm
|   slope of the pullup table from 0 to 0.165 V, typ, clamps not added: 315 ohm
|   rising waveform, R_fixture 50, V_fixture 1.1: 20-80 % time 26.6ps typ, 30ps min, 24ps max; typ from 0.952 V to 1.1 V
|   rising waveform, R_fixture 50, V_fixture 0: 20-80 % time 24ps typ, 29.6ps min, 19.4ps max; typ from 0 V to 0.148 V
|   falling waveform, R_fixture 50, V_fixture 1.1: 20-80 % time 24.1ps typ, 28.3ps min, 20.4ps max; typ from 1.1 V to 0.952 V
|   falling waveform, R_fixture 50, V_fixture 0: 20-80 % time 27.1ps typ, 30.3ps min, 24.4ps max; typ from 0.148 V to 0 V
[Pulldown]
-1.1V     -1.486mA   -1.555mA   -1.547mA
-600mV    -1.361mA   -1.408mA   -1.408mA
-433.3mV  -1.23mA    -1.26mA    -1.273mA
-333.3mV  -1.042mA   -1.075mA   -1.095mA
-233.3mV  -744.3uA   -782.6uA   -787.3uA
933.3mV   2.908mA    3.083mA    3.056mA
1.433V    4.359mA    4.64mA     4.541mA
1.6V      4.741mA    5.039mA    4.944mA
1.7V      4.841mA    5.15mA     5.051mA
1.833V    4.871mA    5.194mA    5.056mA
2V        4.825mA    5.156mA    4.965mA
2.2V      4.697mA    5.018mA    4.781mA
[Pullup]
-1.1V     2.132mA    2.033mA    2.467mA
-666.7mV  1.865mA    1.843mA    2.128mA
-566.7mV  1.731mA    1.719mA    1.967mA
-466.7mV  1.504mA    1.511mA    1.672mA
-300mV    958.4uA    995.6uA    1.012mA
533.3mV   -1.683mA   -1.746mA   -1.772mA
1.2V      -3.711mA   -3.822mA   -3.881mA
1.433V    -4.356mA   -4.425mA   -4.538mA
1.533V    -4.467mA   -4.526mA   -4.597mA
1.767V    -4.439mA   -4.514mA   -4.414mA
1.933V    -4.345mA   -4.407mA   -4.217mA
2.2V      -4.085mA   -4.106mA   -3.75mA
[Ramp]
dV/dt_f 90.289918m/24.547386p 92.378447m/28.462366p 96.493664m/20.830277p
dV/dt_r 90.428667m/24.411612p 90.449569m/29.738401p  96.78171m/19.906454p
R_load =  50
[Rising Waveform]
R_fixture =  50
V_fixture =  1.1
V_fixture_min =  1.078
V_fixture_max =  1.122
0s        951.8mV    925.4mV    964.3mV
10.9ps    954.1mV    927.7mV    966.8mV
16.8ps    963.1mV    935mV      977.4mV
22ps      977.7mV    948.2mV    995.5mV
34.9ps    1.034V     999.7mV    1.061V
47ps      1.066V     1.035V     1.092V
63.1ps    1.085V     1.058V     1.11V
93.2ps    1.097V     1.074V     1.121V
178.2ps   1.1V       1.078V     1.122V
1.012ns   1.1V       1.078V     1.122V
[Rising Waveform]
R_fixture =  50
V_fixture =  0
V_fixture_min =  0
V_fixture_max =  0
0s        0V         0V         0V
22ps      0V         0V         0V
27.8ps    12.58mV    6.293mV    19.08mV
32.1ps    29.39mV    17.4mV     41.88mV
44ps      86.65mV    69.09mV    107.6mV
53.5ps    113.7mV    98.59mV    134.3mV
66.2ps    132.2mV    121.8mV    149.5mV
90.3ps    145.1mV    140.7mV    157.6mV
173.1ps   149.1mV    150mV      158.2mV
1.012ns   148.5mV    149.8mV    157.8mV
[Falling Waveform]
R_fixture =  50
V_fixture =  1.1
V_fixture_min =  1.078
V_fixture_max =  1.122
0s        1.1V       1.078V     1.122V
22ps      1.099V     1.076V     1.119V
29.3ps    1.08V      1.061V     1.092V
40.9ps    1.025V     1.011V     1.028V
49ps      995.8mV    981.5mV    998.5mV
60.1ps    974.5mV    957.6mV    978.6mV
80.4ps    957.8mV    936.4mV    966.3mV
107.7ps   952mV      927.4mV    963.7mV
157.4ps   951.1mV    924.7mV    963.8mV
1.012ns   951.8mV    925.1mV    964.3mV
[Falling Waveform]
R_fixture =  50
V_fixture =  0
V_fixture_min =  0
V_fixture_max =  0
0s        148.5mV    149.8mV    157.8mV
8.4ps     147.9mV    148.6mV    157.4mV
16.8ps    137.3mV    136.8mV    144.7mV
22ps      120.8mV    121.2mV    123.9mV
34.1ps    66.52mV    72.05mV    61.65mV
46ps      35.78mV    40.81mV    31.23mV
62.7ps    15.16mV    18.44mV    11.51mV
90.6ps    3.118mV    4.913mV    0V
109.8ps   0V         0V         0V
1.012ns   0V         0V         0V
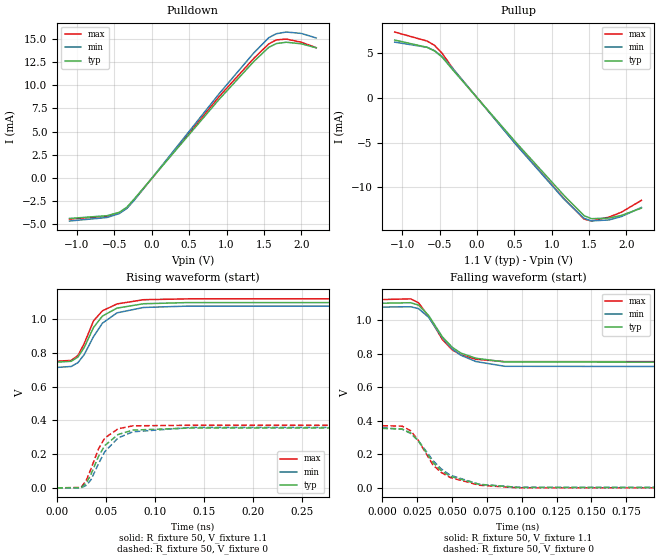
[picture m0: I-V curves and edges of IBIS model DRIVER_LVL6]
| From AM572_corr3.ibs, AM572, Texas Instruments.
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| Model based on original model for USB3_PCIEGEN1_PCIEGEN2_TX
|   Sub model DRIVER_LVL6
[model]   DRIVER_LVL6
|[Description]  [1.1V-3-STATE-X-X]
|   , ,
|[Input Load]
|[Output Drive]
|Voltage   1.1V
|Mode   3-STATE
Model_type   3-state
Polarity   Non-Inverting
Enable   Active-Low
Cref =   15.0000pF
Rref =   100.0000M
Vref =   0V
Vmeas =   0.55
C_comp   0   0   0
[Temperature Range]   25   125   -40
[Voltage Range]   1.1   1.078   1.122
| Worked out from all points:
|   slope of the pulldown table from 0 to 0.165 V, typ, clamps not added: 104 ohm
|   slope of the pullup table from 0 to 0.165 V, typ, clamps not added: 104 ohm
|   rising waveform, R_fixture 50, V_fixture 1.1: 20-80 % time 22.2ps typ, 24.1ps min, 20.2ps max; typ from 0.746 V to 1.1 V
|   rising waveform, R_fixture 50, V_fixture 0: 20-80 % time 19.8ps typ, 23.3ps min, 16.8ps max; typ from 0 V to 0.355 V
|   falling waveform, R_fixture 50, V_fixture 1.1: 20-80 % time 20.6ps typ, 22.9ps min, 18.3ps max; typ from 1.1 V to 0.746 V
|   falling waveform, R_fixture 50, V_fixture 0: 20-80 % time 22.8ps typ, 24.3ps min, 21ps max; typ from 0.355 V to 0 V
[Pulldown]
-1.1V     -4.363mA   -4.638mA   -4.432mA
-600mV    -4.067mA   -4.261mA   -4.127mA
-433.3mV  -3.697mA   -3.832mA   -3.758mA
-333.3mV  -3.144mA   -3.28mA    -3.249mA
-233.3mV  -2.249mA   -2.39mA    -2.341mA
900mV     8.473mA    9.074mA    8.767mA
1.367V    12.58mA    13.51mA    12.92mA
1.567V    14.1mA     15.14mA    14.47mA
1.667V    14.5mA     15.56mA    14.89mA
1.8V      14.64mA    15.74mA    14.98mA
2V        14.47mA    15.59mA    14.64mA
2.2V      14.04mA    15.1mA     14.05mA
[Pullup]
-1.1V     6.463mA    6.229mA    7.36mA
-666.7mV  5.651mA    5.652mA    6.349mA
-566.7mV  5.244mA    5.268mA    5.867mA
-466.7mV  4.555mA    4.627mA    4.988mA
-300mV    2.903mA    3.047mA    3.023mA
533.3mV   -5.097mA   -5.339mA   -5.293mA
1.167V    -10.94mA   -11.36mA   -11.29mA
1.433V    -13.18mA   -13.48mA   -13.56mA
1.533V    -13.52mA   -13.77mA   -13.78mA
1.767V    -13.45mA   -13.66mA   -13.34mA
1.933V    -13.15mA   -13.28mA   -12.79mA
2.2V      -12.34mA   -12.26mA   -11.47mA
[Ramp]
dV/dt_f  0.2152321/20.914676p 0.21948362/23.063461p 0.22628791/18.605806p
dV/dt_r 0.21612722/20.158082p 0.21660639/23.487182p 0.22783576/17.206743p
R_load =  50
[Rising Waveform]
R_fixture =  50
V_fixture =  1.1
V_fixture_min =  1.078
V_fixture_max =  1.122
0s        746.4mV    715.1mV    752.1mV
14.3ps    751.3mV    720.6mV    756.6mV
21.2ps    776.6mV    743.3mV    785.7mV
27.6ps    833.6mV    791.2mV    856.8mV
37.1ps    951.9mV    898mV      991.2mV
46.2ps    1.02V      977.6mV    1.051V
61.1ps    1.067V     1.039V     1.092V
88.2ps    1.093V     1.071V     1.117V
133.3ps   1.1V       1.079V     1.122V
1.012ns   1.1V       1.078V     1.122V
[Rising Waveform]
R_fixture =  50
V_fixture =  0
V_fixture_min =  0
V_fixture_max =  0
0s        0V         0V         0V
24.5ps    0V         0V         2.545mV
30ps      30.92mV    15.56mV    48.25mV
34.5ps    79.88mV    48mV       112.6mV
42.2ps    187.1mV    143.2mV    231.7mV
48.6ps    251.1mV    214.7mV    295.7mV
62.2ps    316.7mV    296.4mV    350.7mV
77.4ps    342.9mV    332.9mV    368.2mV
138.6ps   355.8mV    358.9mV    371.6mV
1.012ns   354.6mV    358.2mV    370.6mV
[Falling Waveform]
R_fixture =  50
V_fixture =  1.1
V_fixture_min =  1.078
V_fixture_max =  1.122
0s        1.101V     1.078V     1.123V
20.3ps    1.104V     1.08V      1.127V
25.9ps    1.09V      1.069V     1.104V
33.2ps    1.028V     1.017V     1.022V
43.1ps    899.9mV    894.1mV    884.2mV
50.2ps    837.7mV    828.2mV    822.1mV
56.3ps    803.9mV    791mV      793.3mV
67.2ps    772.8mV    753.1mV    766.7mV
87.9ps    750.7mV    724.9mV    752.6mV
1.012ns   746.4mV    715.1mV    752.6mV
[Falling Waveform]
R_fixture =  50
V_fixture =  0
V_fixture_min =  0
V_fixture_max =  0
0s        354.6mV    358.2mV    370.6mV
14.1ps    350.7mV    350.3mV    367.9mV
20.3ps    327.5mV    324.5mV    340.9mV
25.8ps    280.6mV    281.5mV    282.3mV
36.4ps    150.5mV    162.2mV    135.4mV
42.2ps    102.7mV    113.1mV    91.98mV
48.7ps    68.78mV    75.41mV    61.59mV
69.5ps    20.67mV    21.31mV    15.73mV
97.4ps    2.782mV    2.917mV    0V
1.012ns   0V         0V         0V
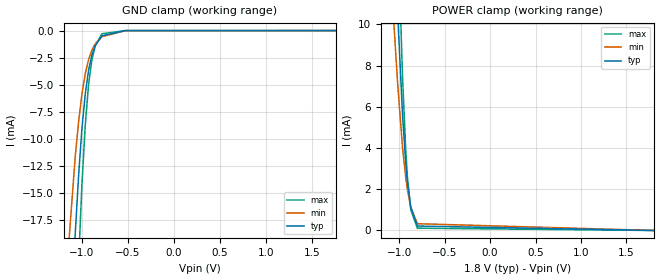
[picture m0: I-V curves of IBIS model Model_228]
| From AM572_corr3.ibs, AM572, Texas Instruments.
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| Model based on original model for ACSPCIE_RX
|   Sub model ACSPCIE_RX
[model]   Model_228
|[Description]  [1.8V-INPUT-X-X]
|   , ,
|[Input Load]
|[Output Drive]
|Voltage   1.8V
|Mode   INPUT
Model_type   Input
Polarity   Non-Inverting
Vinl =   0.150
Vinh =   0.150
C_comp   0.5p   0.3p   0.8p
[Temperature Range]   25   125   -40
[Voltage Range]   1.8   1.35   1.98
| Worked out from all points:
|   GND clamp passes 1 mA (typ) near -0.83 V on its own axis
|   POWER clamp passes 1 mA (typ) near -0.87 V on its own axis
[POWER_clamp]
-1.8V     129.8mA    93.23mA    181.3mA
-1.127V   23.98mA    15.99mA    34.7mA
-1.073V   16.9mA     11.23mA    24.42mA
-1.055V   14.7mA     9.792mA    21.18mA
-1.036V   12.61mA    8.434mA    18.07mA
-1.018V   10.63mA    7.172mA    15.1mA
-963.6mV  5.613mA    4.033mA    7.46mA
-927.3mV  3.215mA    2.535mA    3.833mA
-909.1mV  2.33mA     1.962mA    2.559mA
-872.7mV  1.13mA     1.126mA    999.4uA
-800mV    214.5uA    328.3uA    111.7uA
1.8V      5.122nA    31.89nA    847.9pA
[GND_clamp]
-1.8V     -193.7mA   -127.3mA   -300.7mA
-1.145V   -32.35mA   -19.9mA    -52.46mA
-1.073V   -18.81mA   -11.65mA   -30.35mA
-1.036V   -13.38mA   -8.412mA   -21.39mA
-1V       -9.056mA   -5.858mA   -14.2mA
-963.6mV  -5.842mA   -3.971mA   -8.723mA
-927.3mV  -3.633mA   -2.658mA   -4.933mA
-890.9mV  -2.235mA   -1.785mA   -2.655mA
-854.5mV  -1.38mA    -1.212mA   -1.379mA
-781.8mV  -487.3uA   -559.5uA   -295.7uA
-527.3mV  -346nA     -7.529uA   -9.988nA
1.764V    4.187nA    50.44nA    371pA
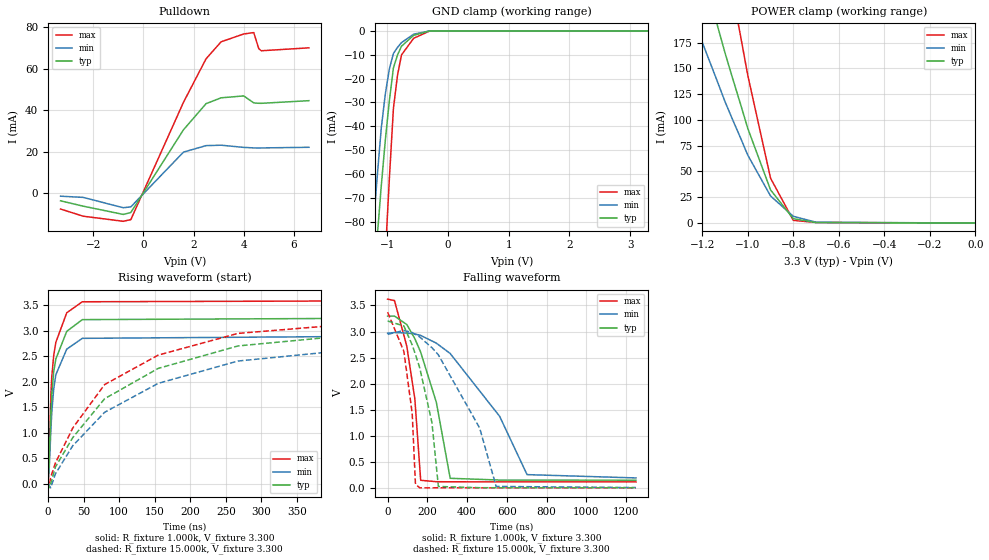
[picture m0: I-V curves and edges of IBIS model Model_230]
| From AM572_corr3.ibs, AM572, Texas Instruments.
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| Model based on original model for BI2C1833DVFZP18_SSCEV
|   Sub model FAST_STD_MODE_3.3V_10P_3P3
[model]   Model_230
|[Description]  [3.3V-I/O_OPEN_DRAIN-X-FAST MODE AND STD MODE, IND, 10 PERCENT%]
|   FAST MODE AND STD MODE, ,IND,10 PERCENT%
|[Input Load]
|[Output Drive] FAST MODE AND STD MODE
|Voltage   3.3V
|Mode   I/O_OPEN_DRAIN
Model_type   I/O_open_drain
Polarity   Non-Inverting
Enable   Active-Low
Vinl =   0.99
Vinh =   2.31
Cref =   15pF
Rref =   1000
Vref =   3.3V
Vmeas =   1.65
C_comp   2.155p   1.84p   2.47p
[Model Spec]
Vinl   0.99   0.891   1.089
Vinh   2.31   2.079   2.541
[Temperature Range]   25   125   -40
[Voltage Range]   3.3   2.97   3.63
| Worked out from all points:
|   slope of the pulldown table from 0 to 0.495 V, typ, clamps not added: 49.9 ohm
|   GND clamp passes 1 mA (typ) near -0.51 V on its own axis
|   POWER clamp passes 1 mA (typ) near -0.71 V on its own axis
|   rising waveform, R_fixture 1.000k, V_fixture 3.300: 20-80 % time 12.8ns typ, 13.6ns min, 11.4ns max; typ from 0.154 V to 3.3 V
|   rising waveform, R_fixture 15.000k, V_fixture 3.300: 20-80 % time 201ns typ, 223ns min, 173ns max; typ from 0.011 V to 3.2 V
|   falling waveform, R_fixture 1.000k, V_fixture 3.300: 20-80 % time 125ns typ, 278ns min, 67.3ns max; typ from 3.3 V to 0.155 V
|   falling waveform, R_fixture 15.000k, V_fixture 3.300: 20-80 % time 101ns typ, 211ns min, 56ns max; typ from 3.2 V to 0.011 V
[POWER_clamp]
-3.3V     2.049A     1.764A     3.216A
-1.233V   270.7mA    195.6mA    431mA
-1.2V     243.7mA    175.4mA    388.1mA
-1.133V   191.3mA    137mA      304.3mA
-1.1V     165.1mA    117.8mA    262.4mA
-1.067V   140.7mA    100.5mA    222.7mA
-1.033V   116.2mA    83.19mA    183mA
-1V       91.83mA    65.88mA    143.4mA
-900mV    32.17mA    26.27mA    43.57mA
-800mV    4.26mA     6.555mA    2.616mA
-700mV    450.3uA    792.2uA    566.6uA
0V        3.221uA    1.533uA    8.765uA
[Pulldown]
-3.3V     -3.73mA    -1.5mA     -7.7mA
-2.4V     -6.31mA    -2.08mA    -11.16mA
-800mV    -10.3mA    -7.071mA   -13.62mA
-500mV    -9.392mA   -6.653mA   -12.82mA
1.6V      30.57mA    19.78mA    43.84mA
2.5V      43.16mA    22.9mA     64.83mA
3.1V      45.98mA    23.11mA    73.02mA
4V        46.9mA     22.05mA    76.79mA
4.4V      43.53mA    21.8mA     77.47mA
4.6V      43.34mA    21.78mA    69.69mA
4.7V      43.32mA    21.79mA    68.69mA
6.6V      44.6mA     22.1mA     70.1mA
[GND_clamp]
-3.3V     -875.5mA   -1.066A    -1.476A
-1.233V   -108.7mA   -83.07mA   -205.1mA
-1.167V   -86.55mA   -61.14mA   -167mA
-1.1V     -65.01mA   -40.77mA   -129.4mA
-1.033V   -45.78mA   -26.43mA   -94.21mA
-966.7mV  -29.29mA   -16.01mA   -61.94mA
-900mV    -15.55mA   -9.513mA   -32.65mA
-833.3mV  -10.16mA   -6.964mA   -18.71mA
-766.7mV  -6.44mA    -4.915mA   -10.09mA
-566.7mV  -1.886mA   -1.406mA   -3.134mA
-300mV    -12.33uA   -22.08uA   -20.18uA
3.3V      3.221uA    4.331uA    8.605uA
[Ramp]
dV/dt_f   0.966/0.26431907u   0.64956/0.75344395u   1.26348/0.133287u
dV/dt_r   26.7972m/2.6466169n  17.85636m/4.6518285n   30.4572m/1.856609n
R_load =  50
[Rising Waveform]
R_fixture =  1.000k
V_fixture =  3.300
V_fixture_min =  2.970
V_fixture_max =  3.630
160fs     154.2mV    194.1mV    121.7mV
438.6ps   128.9mV    194.1mV    106mV
1.356ns   414.4mV    245.3mV    569.8mV
3.918ns   1.395V     1.082V     1.762V
5.061ns   1.73V      1.387V     2.088V
7.764ns   2.194V     1.854V     2.508V
10.83ns   2.447V     2.14V      2.774V
26.16ns   2.989V     2.64V      3.353V
48.07ns   3.219V     2.852V     3.569V
1.25us    3.297V     2.968V     3.621V
[Rising Waveform]
R_fixture =  15.000k
V_fixture =  3.300
V_fixture_min =  2.970
V_fixture_max =  3.630
0s        10.68mV    13.25mV    8.239mV
1.205ns   -76.94mV   -25.92mV   -70.81mV
3.483ns   -1.799mV   -79.78mV   122mV
10.27ns   330.8mV    195.8mV    409.7mV
34.7ns    907mV      747.3mV    1.096V
79.51ns   1.668V     1.402V     1.946V
155ns     2.263V     1.97V      2.524V
267.2ns   2.703V     2.407V     2.949V
578.6ns   3.113V     2.836V     3.306V
1.25us    3.204V     2.942V     3.372V
[Falling Waveform]
R_fixture =  1.000k
V_fixture =  3.300
V_fixture_min =  2.970
V_fixture_max =  3.630
426.9ps   3.297V     2.969V     3.622V
35.07ns   3.297V     2.982V     3.594V
96.83ns   3.136V     2.973V     2.724V
137.5ns   2.865V     2.955V     1.71V
166.8ns   2.606V     2.927V     153.3mV
245.7ns   1.645V     2.779V     126mV
315.2ns   191.4mV    2.581V     124.4mV
564.1ns   157.6mV    1.378V     122.9mV
702ns     156.4mV    261.8mV    123.1mV
1.25us    155.1mV    198.2mV    122.5mV
[Falling Waveform]
R_fixture =  15.000k
V_fixture =  3.300
V_fixture_min =  2.970
V_fixture_max =  3.630
426.9ps   3.204V     2.948V     3.372V
82.32ns   3.108V     3.022V     2.621V
124.1ns   2.744V     2.982V     1.436V
140.6ns   2.559V     2.947V     75.62mV
162ns     2.307V     2.897V     8.766mV
223.5ns   1.257V     2.692V     8.721mV
255.8ns   34.65mV    2.555V     9.96mV
463.4ns   11.06mV    1.155V     8.296mV
546.5ns   10.62mV    35.37mV    8.281mV
1.25us    10.68mV    13.96mV    8.239mV
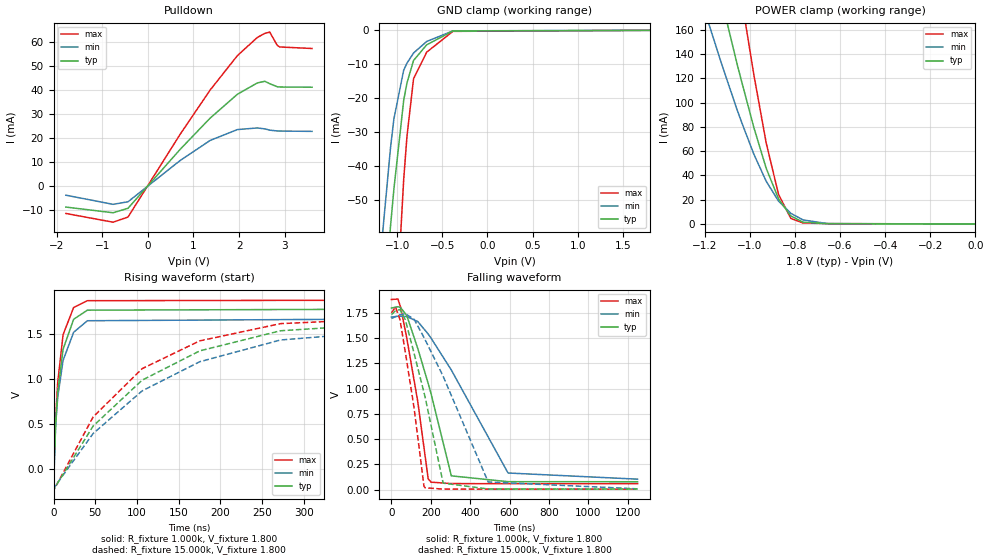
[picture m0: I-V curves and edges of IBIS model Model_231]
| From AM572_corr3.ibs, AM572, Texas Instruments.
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| Model based on original model for BI2C1833DVFZP18_SSCEV
|   Sub model FAST_STD_MODE_1.8V_5P_1P8
[model]   Model_231
|[Description]  [1.8V-I/O_OPEN_DRAIN-X-FAST MODE AND STD MODE, IND, 5 PERCENT%]
|   FAST MODE AND STD MODE, ,IND,5 PERCENT%
|[Input Load]
|[Output Drive] FAST MODE AND STD MODE
|Voltage   1.8V
|Mode   I/O_OPEN_DRAIN
Model_type   I/O_open_drain
Polarity   Non-Inverting
Enable   Active-Low
Vinl =   0.54
Vinh =   1.26
Cref =   15pF
Rref =   1000
Vref =   1.8V
Vmeas =   0.9
C_comp   2.29p   1.81p   2.77p
[Model Spec]
Vinl   0.54   0.513   0.567
Vinh   1.26   1.197   1.323
[Temperature Range]   25   125   -40
[Voltage Range]   1.8   1.71   1.89
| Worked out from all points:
|   slope of the pulldown table from 0 to 0.27 V, typ, clamps not added: 45.4 ohm
|   GND clamp passes 1 mA (typ) near -0.49 V on its own axis
|   POWER clamp passes 1 mA (typ) near -0.74 V on its own axis
|   rising waveform, R_fixture 1.000k, V_fixture 1.800: 20-80 % time 12.3ns typ, 14.8ns min, 10.2ns max; typ from 0.077 V to 1.8 V
|   rising waveform, R_fixture 15.000k, V_fixture 1.800: 20-80 % time 164ns typ, 191ns min, 137ns max; typ from 0.005 V to 1.73 V
|   falling waveform, R_fixture 1.000k, V_fixture 1.800: 20-80 % time 144ns typ, 276ns min, 89.2ns max; typ from 1.8 V to 0.077 V
|   falling waveform, R_fixture 15.000k, V_fixture 1.800: 20-80 % time 125ns typ, 235ns min, 78.7ns max; typ from 1.73 V to 0.005 V
[POWER_clamp]
-1.8V     746.5mA    555.3mA    1.181A
-1.218V   258.3mA    186.3mA    411.3mA
-1.127V   186.2mA    133.2mA    296.1mA
-1.055V   130.9mA    93.44mA    207.1mA
-1.036V   117.4mA    83.77mA    185.1mA
-981.8mV  79.41mA    57.45mA    122.8mA
-927.3mV  45.94mA    35.21mA    66.84mA
-872.7mV  20.67mA    18.89mA    24.46mA
-818.2mV  6.579mA    8.765mA    4.59mA
-763.6mV  1.447mA    3.293mA    764.3uA
-654.5mV  205.7uA    269.4uA    283.7uA
0V        2.27uA     927.4nA    5.009uA
[Pulldown]
-1.8V     -8.76mA    -3.81mA    -11.42mA
-763.6mV  -11.13mA   -7.619mA   -15.06mA
-436.4mV  -9.263mA   -6.556mA   -12.92mA
709.1mV   15.31mA    10.65mA    21.6mA
1.364V    28.27mA    18.99mA    39.95mA
1.964V    38.24mA    23.52mA    54.34mA
2.4V      42.94mA    24.2mA     61.89mA
2.564V    43.64mA    23.81mA    63.58mA
2.673V    42.64mA    23.28mA    64.13mA
2.836V    41.36mA    22.95mA    58.64mA
2.891V    41.26mA    22.91mA    57.93mA
3.6V      41.16mA    22.77mA    57.3mA
[GND_clamp]
-1.8V     -312.7mA   -306.1mA   -547.2mA
-1.291V   -129.4mA   -103.7mA   -240.2mA
-1.218V   -104.5mA   -78.02mA   -197.8mA
-1.182V   -92.38mA   -65.92mA   -176.8mA
-1.073V   -57.71mA   -34.59mA   -115.9mA
-1.036V   -46.88mA   -26.15mA   -96.3mA
-927.3mV  -20.64mA   -11.73mA   -43.97mA
-890.9mV  -15.5mA    -9.682mA   -31.24mA
-818.2mV  -8.896mA   -6.689mA   -14.3mA
-672.7mV  -4.275mA   -3.291mA   -6.439mA
-381.8mV  -173.6uA   -151uA     -298.2uA
1.8V      2.27uA     1.006uA    4.805uA
[Ramp]
dV/dt_f   0.559368/0.17752417u   0.433914/0.39360065u   0.685362/0.10705219u
dV/dt_r 75.495456m/79.494821p 57.944682m/0.10992483n 89.662746m/58.534301p
R_load =  50
[Rising Waveform]
R_fixture =  1.000k
V_fixture =  1.800
V_fixture_min =  1.710
V_fixture_max =  1.890
0s        77.11mV    101.8mV    58.22mV
145.1ps   77.11mV    101.8mV    -137.8mV
311.2ps   -98.49mV   101.8mV    -51.8mV
627.4ps   36.68mV    -40.68mV   74.13mV
2.532ns   499.3mV    487.2mV    567.8mV
4.995ns   846.6mV    797mV      960.1mV
11.43ns   1.329V     1.206V     1.49V
24.09ns   1.661V     1.517V     1.792V
40.55ns   1.762V     1.645V     1.867V
1.25us    1.798V     1.709V     1.885V
[Rising Waveform]
R_fixture =  15.000k
V_fixture =  1.800
V_fixture_min =  1.710
V_fixture_max =  1.890
0s        5.398mV    6.57mV     4.007mV
145.1ps   5.398mV    6.57mV     -214.3mV
349ps     -210.8mV   6.57mV     -218mV
914.4ps   -212.2mV   -200mV     -220.1mV
47.47ns   478.9mV    396.2mV    579.9mV
106.1ns   986.5mV    867.9mV    1.114V
175.1ns   1.311V     1.191V     1.422V
271.9ns   1.534V     1.432V     1.613V
571.9ns   1.71V      1.653V     1.738V
1.25us    1.734V     1.695V     1.75V
[Falling Waveform]
R_fixture =  1.000k
V_fixture =  1.800
V_fixture_min =  1.710
V_fixture_max =  1.890
32.02ps   1.799V     1.709V     1.884V
33.16ns   1.812V     1.718V     1.888V
46.64ns   1.804V     1.718V     1.808V
78.21ns   1.724V     1.714V     1.5V
134ns     1.398V     1.665V     871.3mV
186.8ns   1.052V     1.542V     107.8mV
201.3ns   951.6mV    1.501V     73.43mV
304.3ns   136mV      1.185V     59.38mV
592.3ns   78.14mV    164.2mV    58.41mV
1.25us    77.47mV    103.1mV    58.36mV
[Falling Waveform]
R_fixture =  15.000k
V_fixture =  1.800
V_fixture_min =  1.710
V_fixture_max =  1.890
450ps     1.734V     1.696V     1.75V
20.83ns   1.772V     1.713V     1.811V
43.51ns   1.784V     1.733V     1.685V
70.78ns   1.682V     1.742V     1.361V
115ns     1.352V     1.689V     812.3mV
165.6ns   961.3mV    1.507V     31.43mV
171.4ns   914.8mV    1.484V     17.85mV
262.8ns   63.66mV    1.123V     4.254mV
491.4ns   5.572mV    75.18mV    4.03mV
1.25us    5.398mV    7.258mV    4.007mV
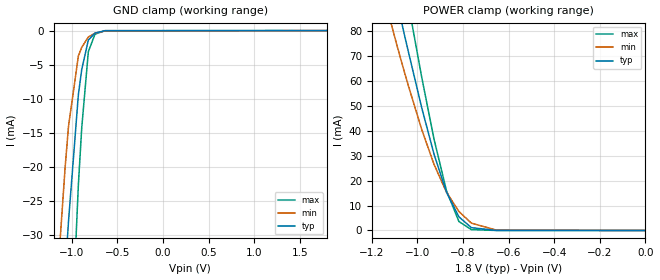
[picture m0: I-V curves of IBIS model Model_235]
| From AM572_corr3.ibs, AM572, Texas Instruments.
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| Model based on original model for IHHV1833DVHYP1811_SSCEV
|   Sub model IHHV1833_V_5P_1P8
[model]   Model_235
|[Description]  [1.8V-INPUT-X-1.8V MODE, IND, 5 PERCENT%]
|   1.8V MODE, ,IND,5 PERCENT%
|[Input Load]
|[Output Drive] 1.8V MODE
|Voltage   1.8V
|Mode   INPUT
Model_type   Input
Polarity   Non-Inverting
Vinl =   0.63
Vinh =   1.17
C_comp   0.318832p   0.222249p   0.415414p
[Model Spec]
Vinl   0.63   0.5985   0.6615
Vinh   1.17   1.1115   1.2285
D_overshoot_ampl_h 0.36 0.36 0.36
D_overshoot_ampl_l 0.36 0.36 0.36
D_overshoot_area_h 0.33n 0.33n 0.33n
D_overshoot_area_l 0.33n 0.33n 0.33n
D_overshoot_high 2.16 2.16 2.16
D_overshoot_low -0.36 -0.36 -0.36
D_overshoot_time 1n 1n 1n
S_overshoot_high 1.8 1.8 1.8
S_overshoot_low 0 0 0
[Temperature Range]   25   125   -40
[Voltage Range]   1.8   1.71   1.89
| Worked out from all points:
|   GND clamp passes 1 mA (typ) near -0.79 V on its own axis
|   POWER clamp passes 1 mA (typ) near -0.76 V on its own axis
[POWER_clamp]
-1.8V     409.4mA    341mA      516mA
-1.145V   115.1mA    93.15mA    146.5mA
-1.091V   92.29mA    74.56mA    117.3mA
-1.055V   77.56mA    62.77mA    98.35mA
-1.036V   70.2mA     56.88mA    88.86mA
-981.8mV  49.37mA    40.63mA    61.66mA
-927.3mV  30.58mA    26.48mA    36.6mA
-872.7mV  15.37mA    15.35mA    15.94mA
-818.2mV  5.459mA    7.61mA     3.59mA
-763.6mV  1.13mA     2.946mA    355.5uA
-654.5mV  18.67uA    168.3uA    2.267uA
0V        117pA      1.358nA    126pA
[GND_clamp]
-1.8V     -216mA     -208.9mA   -335mA
-1.255V   -77.55mA   -59.42mA   -131.6mA
-1.182V   -60.24mA   -42.23mA   -105.5mA
-1.145V   -51.76mA   -34.07mA   -92.6mA
-1.073V   -35.71mA   -20.13mA   -67.62mA
-1.036V   -28.05mA   -14.09mA   -55.43mA
-927.3mV  -9.363mA   -3.716mA   -22.57mA
-890.9mV  -5.722mA   -2.463mA   -14.31mA
-818.2mV  -1.393mA   -946.3uA   -3.094mA
-745.5mV  -368.6uA   -381.4uA   -532.5uA
-636.4mV  -20.54uA   -56.12uA   -10.9uA
1.8V      159.4pA    1.892nA    114pA
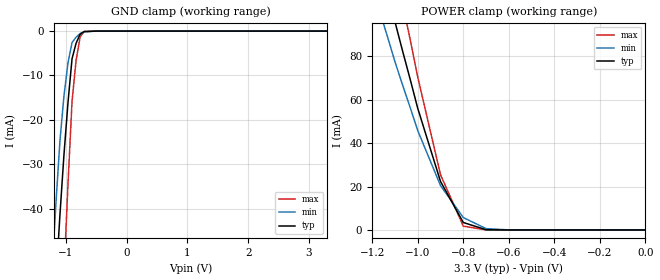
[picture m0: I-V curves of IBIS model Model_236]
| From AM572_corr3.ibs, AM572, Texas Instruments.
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| Model based on original model for IHHV1833DVHYP1811_SSCEV
|   Sub model IHHV1833_V_5P_3P3
[model]   Model_236
|[Description]  [3.3V-INPUT-X-3.3V MODE, IND, 5 PERCENT%]
|   3.3V MODE, ,IND,5 PERCENT%
|[Input Load]
|[Output Drive] 3.3V MODE
|Voltage   3.3V
|Mode   INPUT
Model_type   Input
Polarity   Non-Inverting
Vinl =   0.8V
Vinh =   2V
C_comp   0.273416p   0.188648p   0.358184p
[Model Spec]
Vinl   0.8V   0.8V   0.8V
Vinh   2V   2V   2V
D_overshoot_ampl_h 0.66 0.66 0.66
D_overshoot_ampl_l 0.66 0.66 0.66
D_overshoot_area_h 0.33n 0.33n 0.33n
D_overshoot_area_l 0.33n 0.33n 0.33n
D_overshoot_high 3.96 3.96 3.96
D_overshoot_low -0.66 -0.66 -0.66
D_overshoot_time 1n 1n 1n
S_overshoot_high 3.3 3.3 3.3
S_overshoot_low 0 0 0
[Temperature Range]   25   125   -40
[Voltage Range]   3.3   3.135   3.465
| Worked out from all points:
|   GND clamp passes 1 mA (typ) near -0.78 V on its own axis
|   POWER clamp passes 1 mA (typ) near -0.73 V on its own axis
[POWER_clamp]
-3.3V     1.11A      1.162A     1.387A
-1.167V   124.4mA    100.8mA    158.2mA
-1.133V   110.2mA    89.21mA    140.2mA
-1.1V     96.05mA    77.6mA     122.1mA
-1.067V   82.74mA    67.01mA    104.9mA
-1.033V   69.44mA    56.43mA    87.74mA
-1V       56.13mA    45.84mA    70.54mA
-900mV    22.41mA    20.49mA    25.51mA
-800mV    3.453mA    5.739mA    1.775mA
-700mV    106.2uA    622.6uA    18.17uA
-600mV    2.376uA    32.87uA    192.5nA
0V        301.4pA    6.894nA    543.3pA
[GND_clamp]
-3.3V     -613.4mA   -781.4mA   -911.2mA
-1.233V   -72.53mA   -54.47mA   -124mA
-1.167V   -56.83mA   -39.15mA   -100.2mA
-1.1V     -41.54mA   -24.86mA   -76.83mA
-1.033V   -27.85mA   -14.57mA   -54.79mA
-966.7mV  -16.08mA   -7.152mA   -34.46mA
-900mV    -6.224mA   -2.597mA   -15.84mA
-833.3mV  -2.73mA    -1.371mA   -6.574mA
-766.7mV  -691.9uA   -562.2uA   -1.327mA
-700mV    -110.6uA   -172.2uA   -95.31uA
-500mV    -180.1nA   -2.485uA   -47.11nA
3.3V      302pA      10.65nA    424.5pA
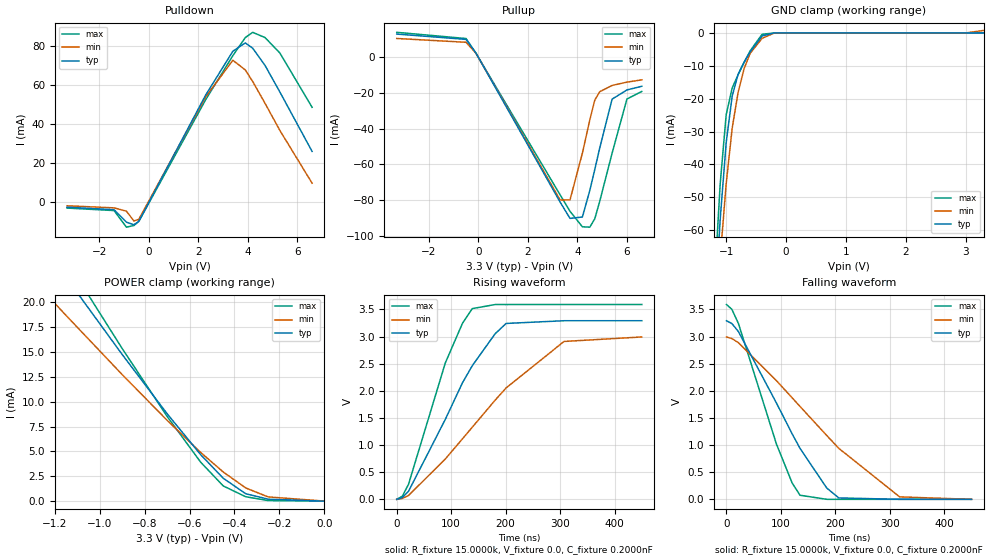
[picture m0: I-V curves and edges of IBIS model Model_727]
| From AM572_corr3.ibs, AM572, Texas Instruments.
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| Model based on original model for USB2PHYCORE_HMAV10GS80
|   Sub model lsdm_200pf_tx
[model]   Model_727
|[Description]  [3.3000V-3-STATE-X-X]
|   , ,
|[Input Load]
|[Output Drive]
|Voltage   3.3000V
|Mode   3-STATE
Model_type   3-state
Polarity   Inverting
Enable   Active-Low
C_comp   7.0000pF   7.0000pF   7.0000pF
[Model Spec]
Vmeas 1.65 1.5 1.8
[Temperature Range]   27.0000   0.1250k   -40.0000
[Voltage Range]   3.3000V   3.0000V   3.6000V
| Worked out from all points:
|   slope of the pulldown table from 0 to 0.495 V, typ, clamps not added: 39.8 ohm
|   slope of the pullup table from 0 to 0.495 V, typ, clamps not added: 40.7 ohm
|   GND clamp passes 1 mA (typ) near -0.40 V on its own axis
|   POWER clamp passes 1 mA (typ) near -0.37 V on its own axis
|   rising waveform, R_fixture 15.0000k, V_fixture 0.0, C_fixture 0.2000nF: 20-80 % time 99.9ns typ, 161ns min, 67.1ns max; typ from 0 V to 3.29 V
|   falling waveform, R_fixture 15.0000k, V_fixture 0.0, C_fixture 0.2000nF: 20-80 % time 105ns typ, 170ns min, 68.5ns max; typ from 3.29 V to 0 V
[Pulldown]
-3.3V     -2.401mA   -1.67mA    -2.857mA
-1.4V     -3.695mA   -2.753mA   -4.133mA
-900mV    -10.07mA   -4.442mA   -12.64mA
-600mV    -11.42mA   -9.457mA   -11.81mA
-400mV    -9.699mA   -8.629mA   -9.649mA
2.3V      55.06mA    54.16mA    52.67mA
3.4V      77.55mA    72.9mA     75.3mA
3.9V      81.79mA    67.98mA    84.5mA
4.2V      79.09mA    62.05mA    87.23mA
4.7V      70.25mA    50.81mA    84.54mA
5.3V      56.6mA     36.92mA    76.61mA
6.6V      26.2mA     9.903mA    48.81mA
[Pullup]
-3.3V     13.1mA     10.64mA    14.09mA
-500mV    10.12mA    8.492mA    10.61mA
-100mV    2.446mA    2.373mA    2.323mA
3.3V      -81.22mA   -80.03mA   -77.15mA
3.7V      -90.41mA   -79.99mA   -86.42mA
4.2V      -89.61mA   -53.77mA   -95.13mA
4.5V      -74.71mA   -35.11mA   -95.31mA
4.7V      -62.98mA   -24.03mA   -90.63mA
4.9V      -50.92mA   -19.26mA   -80.83mA
5.4V      -23.44mA   -15.74mA   -53.79mA
6V        -18.25mA   -13.89mA   -23.35mA
6.6V      -16.21mA   -12.59mA   -19.12mA
[GND_clamp]
-3.3V     -840.3mA   -734.3mA   -920.6mA
-1.2V     -86.68mA   -94.57mA   -77.88mA
-1.1V     -56.77mA   -68.53mA   -45.9mA
-1V       -33.38mA   -45.87mA   -24.89mA
-900mV    -19.23mA   -29mA      -16.73mA
-800mV    -12.52mA   -18.04mA   -12.67mA
-700mV    -8.862mA   -10.78mA   -8.95mA
-600mV    -5.755mA   -6.231mA   -5.45mA
-400mV    -896.9uA   -1.614mA   -397.4uA
-200mV    -8.59uA    -49.41uA   -5.163uA
3V        2.546uA    8.612uA    1.975uA
3.3V      3.54uA     771.7uA    2.816uA
[POWER_clamp]
-3.3V     110.9mA    96.85mA    135.1mA
-1.4V     30.43mA    24.76mA    33.43mA
-1.25V    25.67mA    21.1mA     27.93mA
-1.2V     24.09mA    19.89mA    26.11mA
-1.15V    22.51mA    18.68mA    24.29mA
-900mV    14.75mA    12.73mA    15.35mA
-700mV    8.795mA    8.133mA    8.526mA
-550mV    4.663mA    4.89mA     3.906mA
-450mV    2.303mA    2.932mA    1.531mA
-350mV    747.8uA    1.329mA    444.6uA
-250mV    199.2uA    426.7uA    62.4uA
0V        3.54uA     8.612uA    3.643uA
[Ramp]
dV/dt_r   1.9746/98.5463n   1.7950/0.1600u   2.1537/65.0865n
dV/dt_f   1.9747/0.1006u   1.7952/0.1645u   2.1539/65.1122n
R_load =   15.0000k
[Rising Waveform]
R_fixture =   15.0000k
V_fixture =   0.0
V_fixture_min =   0.0
V_fixture_max =   0.0
C_fixture =   0.2000nF
0s        63.74uV    44.73uV    95.15uV
10.36ns   32.23mV    17.26mV    58.35mV
21.62ns   148mV      70.43mV    277.4mV
89.19ns   1.473V     743.1mV    2.513V
120.7ns   2.147V     1.115V     3.243V
138.7ns   2.462V     1.329V     3.514V
180.6ns   3.05V      1.826V     3.589V
200.9ns   3.241V     2.053V     3.589V
307.2ns   3.291V     2.909V     3.59V
450ns     3.291V     2.992V     3.59V
[Falling Waveform]
R_fixture =   15.0000k
V_fixture =   0.0
V_fixture_min =   0.0
V_fixture_max =   0.0
C_fixture =   0.2000nF
0s        3.291V     2.992V     3.59V
9.91ns    3.24V      2.963V     3.502V
22.07ns   3.09V      2.886V     3.238V
91.89ns   1.773V     2.186V     1.016V
120.7ns   1.205V     1.87V      300.8mV
135.1ns   939.5mV    1.712V     75.21mV
184.2ns   208.2mV    1.176V     385.9uV
206.3ns   26.11mV    939.6mV    117uV
318ns     62.64uV    45.17mV    95.37uV
450ns     63.69uV    53.55uV    95.18uV
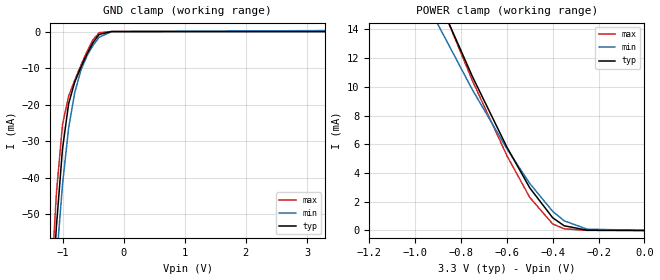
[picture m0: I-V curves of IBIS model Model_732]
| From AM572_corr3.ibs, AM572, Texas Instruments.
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| Model based on original model for USB2PHYCORE_HMAV10GS80
|   Sub model fsrx
[model]   Model_732
|[Description]  [3.3V-INPUT-X-X]
|   , ,
|[Input Load]
|[Output Drive]
|Voltage   3.3V
|Mode   INPUT
Model_type   Input
C_comp   7.0000pF   7.0000pF   7.0000pF
Vinl =  1.6
Vinh =  1.7
[Temperature Range]   27.0000   0.1250k   -40.0000
[Voltage Range]   3.3V   3.0V   3.6V
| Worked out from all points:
|   GND clamp passes 1 mA (typ) near -0.41 V on its own axis
|   POWER clamp passes 1 mA (typ) near -0.41 V on its own axis
[GND_clamp]
-3.3V     -782mA     -691.8mA   -849.7mA
-1.2V     -81.21mA   -87.89mA   -73.74mA
-1.1V     -53.46mA   -63.22mA   -44.36mA
-1V       -32.12mA   -41.94mA   -25.46mA
-900mV    -19.78mA   -26.42mA   -17.7mA
-800mV    -13.86mA   -16.76mA   -13.31mA
-700mV    -9.821mA   -10.67mA   -9.261mA
-600mV    -6.194mA   -6.67mA    -5.473mA
-500mV    -3.012mA   -3.762mA   -2.229mA
-400mV    -781.4uA   -1.558mA   -310.6uA
-200mV    -1.921uA   -32.16uA   -238.5nA
3.3V      198.9nA    275.2uA    240.3nA
[POWER_clamp]
-3.3V     128.2mA    118.7mA    139.8mA
-1.3V     30.83mA    26.64mA    31.9mA
-1.25V    28.94mA    25.04mA    29.88mA
-1.2V     27.06mA    23.45mA    27.87mA
-1.15V    25.18mA    21.88mA    25.87mA
-750mV    10.71mA    9.793mA    10.42mA
-600mV    5.81mA     5.697mA    5.218mA
-500mV    2.966mA    3.271mA    2.299mA
-400mV    885uA      1.333mA    454.5uA
-350mV    328.3uA    673uA      118.8uA
-250mV    20.25uA    94.06uA    3.223uA
0V        198.9nA    574.7nA    247.2nA
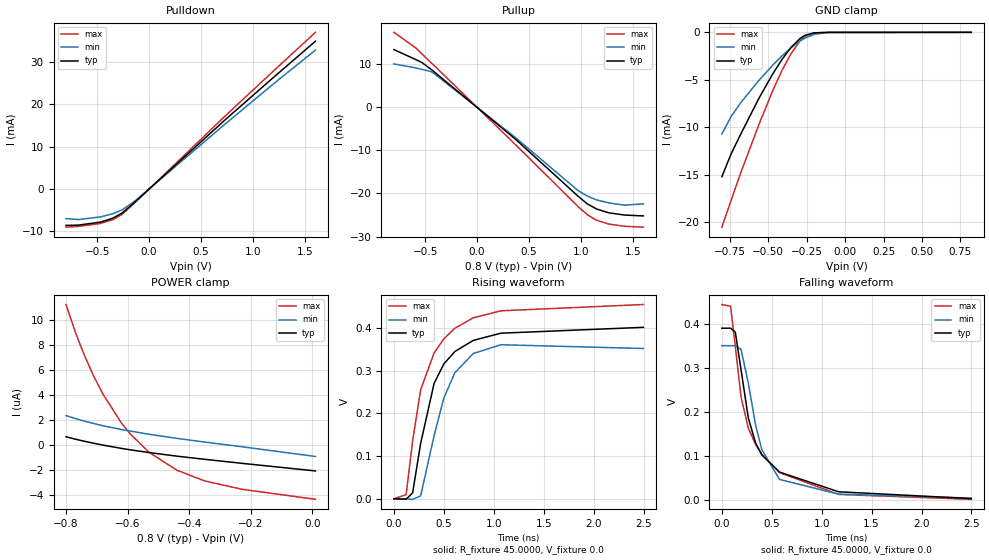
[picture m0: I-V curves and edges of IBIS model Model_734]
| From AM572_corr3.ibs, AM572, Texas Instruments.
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| Model based on original model for USB2PHYCORE_HMAV10GS80
|   Sub model hsdm_tx
[model]   Model_734
|[Description]  [0.8000V-3-STATE-X-X]
|   , ,
|[Input Load]
|[Output Drive]
|Voltage   0.8000V
|Mode   3-STATE
Model_type   3-state
Polarity   Inverting
Enable   Active-Low
C_comp   7.0000pF   7.0000pF   7.0000pF
[Model Spec]
Vmeas 0.2 0.19 0.22
[Temperature Range]   27.0000   0.1250k   -40.0000
[Voltage Range]   0.8000V   0.7920V   0.8100V
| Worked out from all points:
|   slope of the pulldown table from 0 to 0.12 V, typ, clamps not added: 44.4 ohm
|   slope of the pullup table from 0 to 0.12 V, typ, clamps not added: 50.1 ohm
|   GND clamp passes 1 mA (typ) near -0.32 V on its own axis
|   rising waveform, R_fixture 45.0000, V_fixture 0.0: 20-80 % time 280ps typ, 242ps min, 298ps max; typ from 0 V to 0.402 V
|   falling waveform, R_fixture 45.0000, V_fixture 0.0: 20-80 % time 297ps typ, 224ps min, 317ps max; typ from 0.39 V to 0.003 V
[Pulldown]
-800mV    -8.63mA    -7.02mA    -9.04mA
-680mV    -8.56mA    -7.24mA    -8.86mA
-470mV    -7.85mA    -6.62mA    -8.18mA
-350mV    -6.93mA    -5.87mA    -7.27mA
-260mV    -5.69mA    -4.95mA    -6.02mA
-140mV    -3.17mA    -2.93mA    -3.34mA
730mV     16.3mA     15.3mA     17.2mA
1.18V     26mA       24.5mA     27.5mA
1.6V      34.9mA     32.8mA     37mA
[Pullup]
-800mV    13.3mA     9.99mA     17.3mA
-590mV    11mA       9.06mA     13.7mA
-530mV    10.3mA     8.72mA     12.3mA
-440mV    8.69mA     8.19mA     10.2mA
-410mV    8.1mA      7.7mA      9.55mA
370mV     -7.45mA    -7.08mA    -8.71mA
970mV     -20.6mA    -19.3mA    -23mA
1.06V     -22.4mA    -20.6mA    -24.9mA
1.15V     -23.6mA    -21.5mA    -26.2mA
1.27V     -24.5mA    -22.2mA    -27.1mA
1.42V     -25mA      -22.7mA    -27.6mA
1.6V      -25.2mA    -22.4mA    -27.8mA
[GND_clamp]
-800mV    -15.2mA    -10.7mA    -20.5mA
-740mV    -12.8mA    -8.87mA    -17.7mA
-680mV    -10.8mA    -7.46mA    -14.9mA
-560mV    -6.97mA    -5.07mA    -9.74mA
-470mV    -4.39mA    -3.47mA    -6.16mA
-410mV    -2.87mA    -2.49mA    -4.03mA
-350mV    -1.58mA    -1.62mA    -2.23mA
-290mV    -621uA     -893uA     -862uA
-260mV    -317uA     -604uA     -418uA
-200mV    -55.8uA    -211uA     -57.2uA
-110mV    -6.78uA    -26.4uA    -8.85uA
820mV     -2.02uA    -835nA     -4.27uA
[POWER_clamp]
-800mV    628nA      2.32uA     11.2uA
-770mV    441nA      2.09uA     9.01uA
-740mV    269nA      1.88uA     7.12uA
-710mV    111nA      1.69uA     5.47uA
-680mV    -35.8nA    1.51uA     4.04uA
-620mV    -299nA     1.21uA     1.73uA
-590mV    -417nA     1.08uA     821nA
-530mV    -634nA     830nA      -618nA
-440mV    -919nA     503nA      -2.04uA
-350mV    -1.17uA    207nA      -2.9uA
-230mV    -1.49uA    -164nA     -3.56uA
10mV      -2.1uA     -946nA     -4.37uA
[Ramp]
dV/dt_r   0.2370/0.312n   0.2249/0.2162n   0.2454/0.3245n
dV/dt_f   0.2404/0.2810n   0.2345/0.1486n   0.2480/0.3221n
R_load =   45.0000
[Rising Waveform]
R_fixture =   45.0000
V_fixture =   0.0
V_fixture_min =   0.0
V_fixture_max =   0.0
0s        65.75uV    17.07uV    126.2uV
122.5ps   -640.9uV   -43.99uV   9.624mV
187.5ps   14.09mV    -1.171mV   136.1mV
267.5ps   129.8mV    6.726mV    255.5mV
402.5ps   270.5mV    148.1mV    342mV
500ps     316.2mV    236.3mV    374.9mV
610ps     345.1mV    295.4mV    399.7mV
795ps     371.3mV    340.6mV    424.3mV
1.072ns   388.2mV    361.1mV    440.6mV
2.498ns   401.9mV    352.3mV    455.4mV
[Falling Waveform]
R_fixture =   45.0000
V_fixture =   0.0
V_fixture_min =   0.0
V_fixture_max =   0.0
0s        390.1mV    350.4mV    443.9mV
87.5ps    390.1mV    350.4mV    439.8mV
135ps     381.1mV    350.5mV    348.6mV
192.5ps   295.7mV    341.8mV    233.6mV
265ps     186.6mV    266mV      163.4mV
337.5ps   129.6mV    170.6mV    126.3mV
400ps     102.3mV    114.6mV    104.1mV
577.5ps   63.23mV    46.55mV    62.19mV
1.17ns    18.55mV    13.27mV    12.45mV
2.498ns   3.101mV    4.169mV    1.4mV
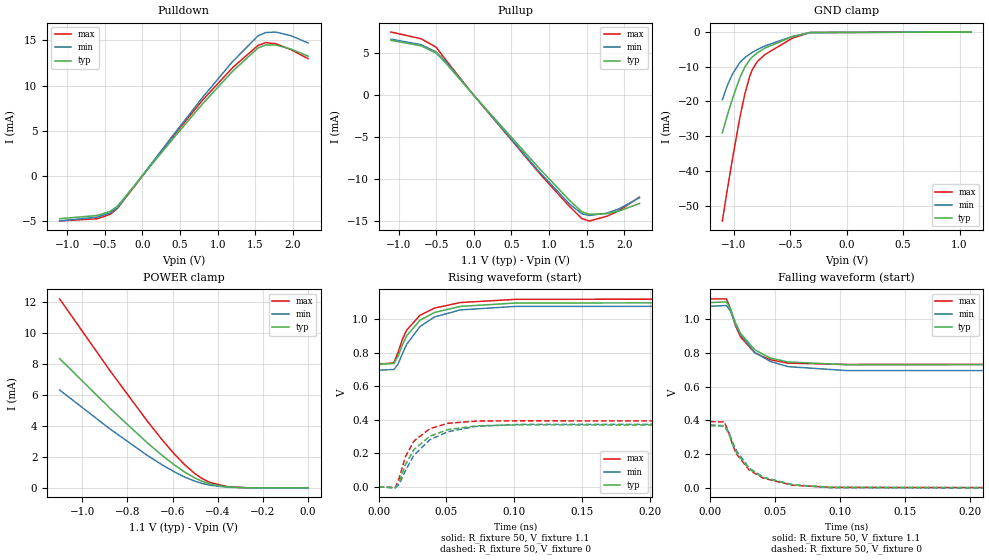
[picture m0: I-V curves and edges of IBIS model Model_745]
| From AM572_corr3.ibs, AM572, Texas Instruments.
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| Model based on original model for SATATX
|   Sub model sata_tx
[model]   Model_745
|[Description]  [1.1V-3-STATE-X-X]
|   , ,
|[Input Load]
|[Output Drive]
|Voltage   1.1V
|Mode   3-STATE
Model_type   3-state
Polarity   Non-Inverting
Enable   Active-Low
Cref =   15.0000pF
Rref =   100.0000M
Vref =   0V
Vmeas =  0.55
C_comp   0.2p   0.2p   0.2p
[Temperature Range]   25   125   -40
[Voltage Range]   1.1   1.078   1.122
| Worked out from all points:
|   slope of the pulldown table from 0 to 0.165 V, typ, clamps not added: 97.1 ohm
|   slope of the pullup table from 0 to 0.165 V, typ, clamps not added: 97.8 ohm
|   GND clamp passes 1 mA (typ) near -0.45 V on its own axis
|   POWER clamp passes 1 mA (typ) near -0.54 V on its own axis
|   rising waveform, R_fixture 50, V_fixture 1.1: 20-80 % time 21.4ps typ, 21.9ps min, 20.1ps max; typ from 0.732 V to 1.1 V
|   rising waveform, R_fixture 50, V_fixture 0: 20-80 % time 19.1ps typ, 23.1ps min, 15ps max; typ from 0 V to 0.369 V
|   falling waveform, R_fixture 50, V_fixture 1.1: 20-80 % time 19.7ps typ, 22.2ps min, 16.6ps max; typ from 1.1 V to 0.732 V
|   falling waveform, R_fixture 50, V_fixture 0: 20-80 % time 21.7ps typ, 22ps min, 20.3ps max; typ from 0.369 V to 0 V
[POWER_clamp]
-1.1V     8.325mA    6.301mA    12.17mA
-877.8mV  5.131mA    3.801mA    7.559mA
-711.1mV  2.888mA    2.081mA    4.28mA
-644.4mV  2.066mA    1.464mA    3.062mA
-588.9mV  1.44mA     1.003mA    2.126mA
-544.4mV  997.7uA    684.2uA    1.459mA
-500mV    626.5uA    423.4uA    900.1uA
-466.7mV  408.3uA    274.1uA    576.5uA
-433.3mV  245.3uA    164.7uA    341.2uA
-355.6mV  50.88uA    36.63uA    71.48uA
-266.7mV  3.44uA     4.06uA     4.564uA
0V        48.94nA    255.6nA    153.1nA
[Pulldown]
-1.1V     -4.711mA   -4.954mA   -4.967mA
-600mV    -4.355mA   -4.537mA   -4.712mA
-433.3mV  -3.915mA   -4.085mA   -4.244mA
-333.3mV  -3.34mA    -3.53mA    -3.587mA
400mV     4.085mA    4.44mA     4.337mA
800mV     8.002mA    8.717mA    8.412mA
1.2V      11.62mA    12.7mA     12.02mA
1.533V    14.16mA    15.49mA    14.44mA
1.633V    14.49mA    15.87mA    14.76mA
1.767V    14.5mA     15.93mA    14.64mA
1.967V    14.06mA    15.54mA    14mA
2.2V      13.26mA    14.72mA    12.98mA
[Pullup]
-1.1V     6.574mA    6.712mA    7.561mA
-700mV    5.912mA    6.056mA    6.759mA
-500mV    5.045mA    5.165mA    5.745mA
-366.7mV  3.802mA    3.976mA    4.165mA
0V        -20.5nA    -207.1nA   41.42nA
866.7mV   -8.698mA   -9.109mA   -9.263mA
1.267V    -12.51mA   -12.95mA   -13.24mA
1.433V    -13.9mA    -14.14mA   -14.71mA
1.533V    -14.21mA   -14.35mA   -15.01mA
1.767V    -14.13mA   -14.07mA   -14.44mA
1.933V    -13.81mA   -13.53mA   -13.75mA
2.2V      -12.92mA   -12.23mA   -12.15mA
[GND_clamp]
-1.1V     -29.03mA   -19.49mA   -54.42mA
-1.056V   -23.98mA   -15.43mA   -45.36mA
-1.011V   -19.25mA   -12.13mA   -36.62mA
-944.4mV  -13.13mA   -8.758mA   -24.54mA
-900mV    -10.05mA   -7.336mA   -17.7mA
-855.6mV  -7.92mA    -6.286mA   -12.57mA
-833.3mV  -7.146mA   -5.838mA   -10.78mA
-788.9mV  -5.95mA    -5.033mA   -8.45mA
-722.2mV  -4.619mA   -3.986mA   -6.455mA
-477.8mV  -1.311mA   -1.247mA   -1.736mA
-322.2mV  -118.1uA   -187.6uA   -129.9uA
1.1V      48.94nA    260.8nA    142.2nA
[Ramp]
dV/dt_f 0.22652402/19.804927p 0.23380202/22.235093p 0.24068853/16.703562p
dV/dt_r 0.22722026/19.163825p 0.22885486/23.169209p 0.24362739/15.133972p
R_load =  50
[Rising Waveform]
R_fixture =  50
V_fixture =  1.1
V_fixture_min =  1.078
V_fixture_max =  1.122
0s        732mV      696.2mV    732.7mV
11.3ps    736mV      700.5mV    739.2mV
14.3ps    779mV      731.3mV    801.1mV
17.7ps    849.8mV    796.4mV    883mV
20.8ps    901.9mV    851.4mV    936.2mV
30.6ps    994.7mV    957.2mV    1.024V
41.3ps    1.041V     1.014V     1.067V
60.3ps    1.077V     1.056V     1.1V
100.8ps   1.097V     1.077V     1.119V
345.3ps   1.1V       1.078V     1.122V
[Rising Waveform]
R_fixture =  50
V_fixture =  0
V_fixture_min =  0
V_fixture_max =  0
0s        0V         0V         0V
12.3ps    -5.518mV   -6.022mV   -4.512mV
15.3ps    31.68mV    15.17mV    54.87mV
19.8ps    132.2mV    96.69mV    179.9mV
26.1ps    222.4mV    189.2mV    273.2mV
37.8ps    301.9mV    281mV      347mV
51.1ps    341.5mV    328.9mV    379.3mV
72.5ps    364.2mV    361.2mV    392.5mV
104.9ps   369.9mV    373.1mV    394mV
345.3ps   368.8mV    373.6mV    392.5mV
[Falling Waveform]
R_fixture =  50
V_fixture =  1.1
V_fixture_min =  1.078
V_fixture_max =  1.122
0s        1.1V       1.078V     1.122V
12.7ps    1.104V     1.082V     1.122V
15.5ps    1.069V     1.054V     1.07V
19.5ps    983.8mV    976mV      965.7mV
23.6ps    917.1mV    908.7mV    895.8mV
34.7ps    818.4mV    802.6mV    800.3mV
46.5ps    770.7mV    750.7mV    760.5mV
60ps      747.4mV    719.7mV    740.4mV
105.2ps   731.2mV    696.4mV    732.4mV
345.3ps   732mV      696.2mV    733.6mV
[Falling Waveform]
R_fixture =  50
V_fixture =  0
V_fixture_min =  0
V_fixture_max =  0
0s        369.4mV    373.6mV    393.4mV
11.2ps    366.2mV    368.6mV    390.9mV
14.4ps    323.9mV    332.7mV    330.7mV
17.8ps    252.1mV    265mV      248.1mV
20.6ps    206.5mV    218.3mV    200.3mV
30.3ps    111mV      116.8mV    105.3mV
41.3ps    61.04mV    62.01mV    56.71mV
63.9ps    18.1mV     17.23mV    15.36mV
94.1ps    3.297mV    0V         2.786mV
345.3ps   0V         0V         0V
